VERSION 5.7 ;
  NOWIREEXTENSIONATPIN ON ;
  DIVIDERCHAR "/" ;
  BUSBITCHARS "[]" ;
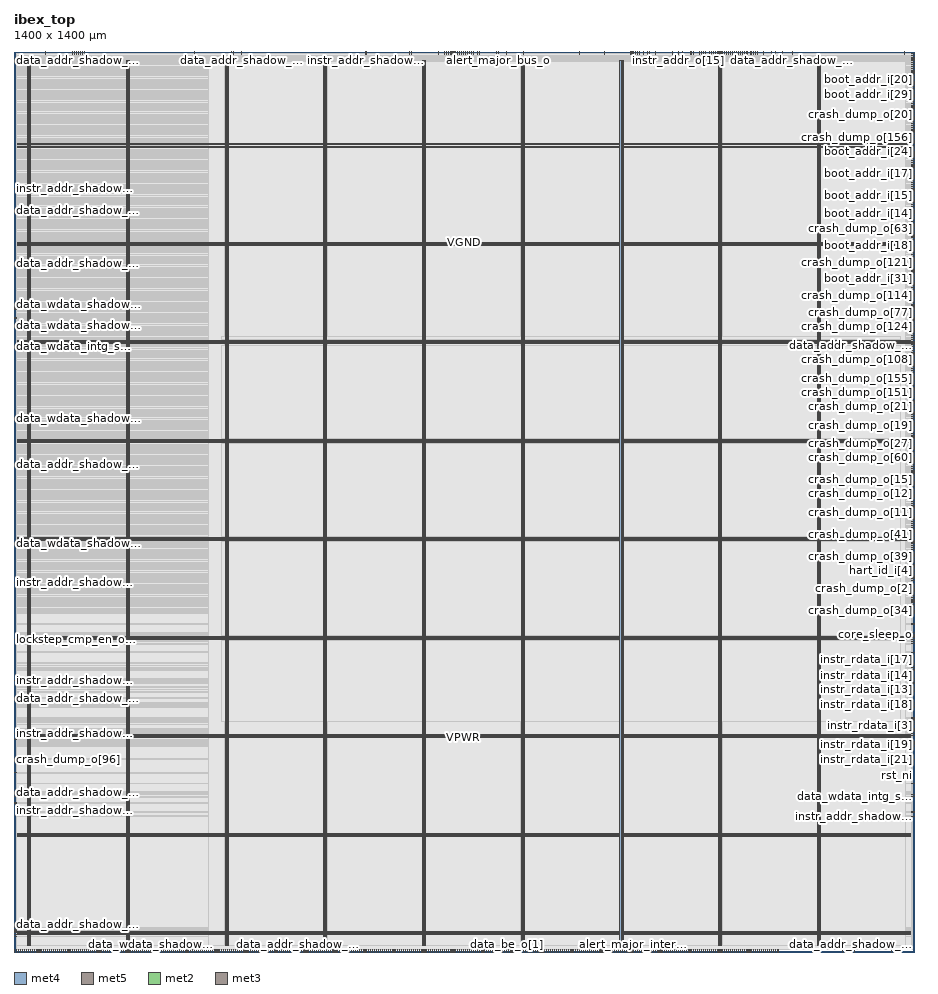
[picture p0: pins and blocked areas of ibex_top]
MACRO ibex_top
  CLASS BLOCK ;
  FOREIGN ibex_top ;
  ORIGIN 0.000 0.000 ;
  SIZE 1400.000 BY 1400.000 ;
  PIN VGND
    DIRECTION INOUT ;
    USE GROUND ;
    PORT
      LAYER met4 ;
        RECT 24.340 10.640 25.940 1387.440 ;
    END
    PORT
      LAYER met4 ;
        RECT 177.940 10.640 179.540 1387.440 ;
    END
    PORT
      LAYER met4 ;
        RECT 331.540 10.640 333.140 1387.440 ;
    END
    PORT
      LAYER met4 ;
        RECT 485.140 10.640 486.740 1387.440 ;
    END
    PORT
      LAYER met4 ;
        RECT 638.740 10.640 640.340 1387.440 ;
    END
    PORT
      LAYER met4 ;
        RECT 792.340 10.640 793.940 1387.440 ;
    END
    PORT
      LAYER met4 ;
        RECT 945.940 10.640 947.540 1387.440 ;
    END
    PORT
      LAYER met4 ;
        RECT 1099.540 10.640 1101.140 1387.440 ;
    END
    PORT
      LAYER met4 ;
        RECT 1253.140 10.640 1254.740 1387.440 ;
    END
    PORT
      LAYER met5 ;
        RECT 5.280 30.030 1394.500 31.630 ;
    END
    PORT
      LAYER met5 ;
        RECT 5.280 183.210 1394.500 184.810 ;
    END
    PORT
      LAYER met5 ;
        RECT 5.280 336.390 1394.500 337.990 ;
    END
    PORT
      LAYER met5 ;
        RECT 5.280 489.570 1394.500 491.170 ;
    END
    PORT
      LAYER met5 ;
        RECT 5.280 642.750 1394.500 644.350 ;
    END
    PORT
      LAYER met5 ;
        RECT 5.280 795.930 1394.500 797.530 ;
    END
    PORT
      LAYER met5 ;
        RECT 5.280 949.110 1394.500 950.710 ;
    END
    PORT
      LAYER met5 ;
        RECT 5.280 1102.290 1394.500 1103.890 ;
    END
    PORT
      LAYER met5 ;
        RECT 5.280 1255.470 1394.500 1257.070 ;
    END
  END VGND
  PIN VPWR
    DIRECTION INOUT ;
    USE POWER ;
    PORT
      LAYER met4 ;
        RECT 21.040 10.640 22.640 1387.440 ;
    END
    PORT
      LAYER met4 ;
        RECT 174.640 10.640 176.240 1387.440 ;
    END
    PORT
      LAYER met4 ;
        RECT 328.240 10.640 329.840 1387.440 ;
    END
    PORT
      LAYER met4 ;
        RECT 481.840 10.640 483.440 1387.440 ;
    END
    PORT
      LAYER met4 ;
        RECT 635.440 10.640 637.040 1387.440 ;
    END
    PORT
      LAYER met4 ;
        RECT 789.040 10.640 790.640 1387.440 ;
    END
    PORT
      LAYER met4 ;
        RECT 942.640 10.640 944.240 1387.440 ;
    END
    PORT
      LAYER met4 ;
        RECT 1096.240 10.640 1097.840 1387.440 ;
    END
    PORT
      LAYER met4 ;
        RECT 1249.840 10.640 1251.440 1387.440 ;
    END
    PORT
      LAYER met5 ;
        RECT 5.280 26.730 1394.500 28.330 ;
    END
    PORT
      LAYER met5 ;
        RECT 5.280 179.910 1394.500 181.510 ;
    END
    PORT
      LAYER met5 ;
        RECT 5.280 333.090 1394.500 334.690 ;
    END
    PORT
      LAYER met5 ;
        RECT 5.280 486.270 1394.500 487.870 ;
    END
    PORT
      LAYER met5 ;
        RECT 5.280 639.450 1394.500 641.050 ;
    END
    PORT
      LAYER met5 ;
        RECT 5.280 792.630 1394.500 794.230 ;
    END
    PORT
      LAYER met5 ;
        RECT 5.280 945.810 1394.500 947.410 ;
    END
    PORT
      LAYER met5 ;
        RECT 5.280 1098.990 1394.500 1100.590 ;
    END
    PORT
      LAYER met5 ;
        RECT 5.280 1252.170 1394.500 1253.770 ;
    END
  END VPWR
  PIN alert_major_bus_o
    DIRECTION OUTPUT ;
    USE SIGNAL ;
    PORT
      LAYER met2 ;
        RECT 753.570 1396.000 753.850 1400.000 ;
    END
  END alert_major_bus_o
  PIN alert_major_internal_o
    DIRECTION OUTPUT ;
    USE SIGNAL ;
    PORT
      LAYER met2 ;
        RECT 962.870 0.000 963.150 4.000 ;
    END
  END alert_major_internal_o
  PIN alert_minor_o
    DIRECTION OUTPUT ;
    USE SIGNAL ;
    PORT
      LAYER met3 ;
        RECT 0.000 278.840 4.000 279.440 ;
    END
  END alert_minor_o
  PIN boot_addr_i[0]
    DIRECTION INPUT ;
    USE SIGNAL ;
    PORT
      LAYER met2 ;
        RECT 9.750 0.000 10.030 4.000 ;
    END
  END boot_addr_i[0]
  PIN boot_addr_i[10]
    DIRECTION INPUT ;
    USE SIGNAL ;
    ANTENNAGATEAREA 0.647700 ;
    ANTENNADIFFAREA 0.434700 ;
    PORT
      LAYER met3 ;
        RECT 1396.000 877.240 1400.000 877.840 ;
    END
  END boot_addr_i[10]
  PIN boot_addr_i[11]
    DIRECTION INPUT ;
    USE SIGNAL ;
    ANTENNAGATEAREA 0.593700 ;
    ANTENNADIFFAREA 0.434700 ;
    PORT
      LAYER met3 ;
        RECT 1396.000 697.040 1400.000 697.640 ;
    END
  END boot_addr_i[11]
  PIN boot_addr_i[12]
    DIRECTION INPUT ;
    USE SIGNAL ;
    ANTENNAGATEAREA 0.647700 ;
    ANTENNADIFFAREA 0.434700 ;
    PORT
      LAYER met3 ;
        RECT 1396.000 945.240 1400.000 945.840 ;
    END
  END boot_addr_i[12]
  PIN boot_addr_i[13]
    DIRECTION INPUT ;
    USE SIGNAL ;
    ANTENNAGATEAREA 0.647700 ;
    ANTENNADIFFAREA 0.434700 ;
    PORT
      LAYER met3 ;
        RECT 1396.000 924.840 1400.000 925.440 ;
    END
  END boot_addr_i[13]
  PIN boot_addr_i[14]
    DIRECTION INPUT ;
    USE SIGNAL ;
    ANTENNAGATEAREA 0.647700 ;
    ANTENNADIFFAREA 0.434700 ;
    PORT
      LAYER met3 ;
        RECT 1396.000 1149.240 1400.000 1149.840 ;
    END
  END boot_addr_i[14]
  PIN boot_addr_i[15]
    DIRECTION INPUT ;
    USE SIGNAL ;
    ANTENNAGATEAREA 0.647700 ;
    ANTENNADIFFAREA 0.434700 ;
    PORT
      LAYER met3 ;
        RECT 1396.000 1176.440 1400.000 1177.040 ;
    END
  END boot_addr_i[15]
  PIN boot_addr_i[16]
    DIRECTION INPUT ;
    USE SIGNAL ;
    ANTENNAGATEAREA 0.682200 ;
    ANTENNADIFFAREA 0.434700 ;
    PORT
      LAYER met3 ;
        RECT 1396.000 1309.040 1400.000 1309.640 ;
    END
  END boot_addr_i[16]
  PIN boot_addr_i[17]
    DIRECTION INPUT ;
    USE SIGNAL ;
    ANTENNAGATEAREA 0.647700 ;
    ANTENNADIFFAREA 0.434700 ;
    PORT
      LAYER met3 ;
        RECT 1396.000 1210.440 1400.000 1211.040 ;
    END
  END boot_addr_i[17]
  PIN boot_addr_i[18]
    DIRECTION INPUT ;
    USE SIGNAL ;
    ANTENNAGATEAREA 0.593700 ;
    ANTENNADIFFAREA 0.434700 ;
    PORT
      LAYER met3 ;
        RECT 1396.000 1098.240 1400.000 1098.840 ;
    END
  END boot_addr_i[18]
  PIN boot_addr_i[19]
    DIRECTION INPUT ;
    USE SIGNAL ;
    ANTENNAGATEAREA 0.593700 ;
    ANTENNADIFFAREA 0.434700 ;
    PORT
      LAYER met3 ;
        RECT 1396.000 1016.640 1400.000 1017.240 ;
    END
  END boot_addr_i[19]
  PIN boot_addr_i[1]
    DIRECTION INPUT ;
    USE SIGNAL ;
    PORT
      LAYER met2 ;
        RECT 12.970 0.000 13.250 4.000 ;
    END
  END boot_addr_i[1]
  PIN boot_addr_i[20]
    DIRECTION INPUT ;
    USE SIGNAL ;
    ANTENNAGATEAREA 0.682200 ;
    ANTENNADIFFAREA 0.434700 ;
    PORT
      LAYER met3 ;
        RECT 1396.000 1356.640 1400.000 1357.240 ;
    END
  END boot_addr_i[20]
  PIN boot_addr_i[21]
    DIRECTION INPUT ;
    USE SIGNAL ;
    ANTENNAGATEAREA 0.682200 ;
    ANTENNADIFFAREA 0.434700 ;
    PORT
      LAYER met3 ;
        RECT 1396.000 1281.840 1400.000 1282.440 ;
    END
  END boot_addr_i[21]
  PIN boot_addr_i[22]
    DIRECTION INPUT ;
    USE SIGNAL ;
    ANTENNAGATEAREA 0.593700 ;
    ANTENNADIFFAREA 0.434700 ;
    PORT
      LAYER met3 ;
        RECT 1396.000 1003.040 1400.000 1003.640 ;
    END
  END boot_addr_i[22]
  PIN boot_addr_i[23]
    DIRECTION INPUT ;
    USE SIGNAL ;
    ANTENNAGATEAREA 0.647700 ;
    ANTENNADIFFAREA 0.434700 ;
    PORT
      LAYER met3 ;
        RECT 1396.000 918.040 1400.000 918.640 ;
    END
  END boot_addr_i[23]
  PIN boot_addr_i[24]
    DIRECTION INPUT ;
    USE SIGNAL ;
    ANTENNAGATEAREA 0.647700 ;
    ANTENNADIFFAREA 0.434700 ;
    PORT
      LAYER met3 ;
        RECT 1396.000 1244.440 1400.000 1245.040 ;
    END
  END boot_addr_i[24]
  PIN boot_addr_i[25]
    DIRECTION INPUT ;
    USE SIGNAL ;
    ANTENNAGATEAREA 0.593700 ;
    ANTENNADIFFAREA 0.434700 ;
    PORT
      LAYER met3 ;
        RECT 1396.000 809.240 1400.000 809.840 ;
    END
  END boot_addr_i[25]
  PIN boot_addr_i[26]
    DIRECTION INPUT ;
    USE SIGNAL ;
    ANTENNAGATEAREA 0.647700 ;
    ANTENNADIFFAREA 0.434700 ;
    PORT
      LAYER met3 ;
        RECT 1396.000 999.640 1400.000 1000.240 ;
    END
  END boot_addr_i[26]
  PIN boot_addr_i[27]
    DIRECTION INPUT ;
    USE SIGNAL ;
    ANTENNAGATEAREA 0.593700 ;
    ANTENNADIFFAREA 0.434700 ;
    PORT
      LAYER met3 ;
        RECT 1396.000 860.240 1400.000 860.840 ;
    END
  END boot_addr_i[27]
  PIN boot_addr_i[28]
    DIRECTION INPUT ;
    USE SIGNAL ;
    ANTENNAGATEAREA 0.647700 ;
    ANTENNADIFFAREA 0.434700 ;
    PORT
      LAYER met3 ;
        RECT 1396.000 744.640 1400.000 745.240 ;
    END
  END boot_addr_i[28]
  PIN boot_addr_i[29]
    DIRECTION INPUT ;
    USE SIGNAL ;
    ANTENNAGATEAREA 0.682200 ;
    ANTENNADIFFAREA 0.434700 ;
    PORT
      LAYER met3 ;
        RECT 1396.000 1346.440 1400.000 1347.040 ;
    END
  END boot_addr_i[29]
  PIN boot_addr_i[2]
    DIRECTION INPUT ;
    USE SIGNAL ;
    PORT
      LAYER met2 ;
        RECT 38.730 0.000 39.010 4.000 ;
    END
  END boot_addr_i[2]
  PIN boot_addr_i[30]
    DIRECTION INPUT ;
    USE SIGNAL ;
    ANTENNAGATEAREA 0.593700 ;
    ANTENNADIFFAREA 0.434700 ;
    PORT
      LAYER met3 ;
        RECT 1396.000 965.640 1400.000 966.240 ;
    END
  END boot_addr_i[30]
  PIN boot_addr_i[31]
    DIRECTION INPUT ;
    USE SIGNAL ;
    ANTENNAGATEAREA 0.647700 ;
    ANTENNADIFFAREA 0.434700 ;
    PORT
      LAYER met3 ;
        RECT 1396.000 1047.240 1400.000 1047.840 ;
    END
  END boot_addr_i[31]
  PIN boot_addr_i[3]
    DIRECTION INPUT ;
    USE SIGNAL ;
    PORT
      LAYER met2 ;
        RECT 315.650 0.000 315.930 4.000 ;
    END
  END boot_addr_i[3]
  PIN boot_addr_i[4]
    DIRECTION INPUT ;
    USE SIGNAL ;
    PORT
      LAYER met2 ;
        RECT 35.510 0.000 35.790 4.000 ;
    END
  END boot_addr_i[4]
  PIN boot_addr_i[5]
    DIRECTION INPUT ;
    USE SIGNAL ;
    PORT
      LAYER met2 ;
        RECT 19.410 0.000 19.690 4.000 ;
    END
  END boot_addr_i[5]
  PIN boot_addr_i[6]
    DIRECTION INPUT ;
    USE SIGNAL ;
    PORT
      LAYER met2 ;
        RECT 41.950 0.000 42.230 4.000 ;
    END
  END boot_addr_i[6]
  PIN boot_addr_i[7]
    DIRECTION INPUT ;
    USE SIGNAL ;
    PORT
      LAYER met2 ;
        RECT 25.850 0.000 26.130 4.000 ;
    END
  END boot_addr_i[7]
  PIN boot_addr_i[8]
    DIRECTION INPUT ;
    USE SIGNAL ;
    ANTENNAGATEAREA 0.682200 ;
    ANTENNADIFFAREA 0.434700 ;
    PORT
      LAYER met3 ;
        RECT 1396.000 1020.040 1400.000 1020.640 ;
    END
  END boot_addr_i[8]
  PIN boot_addr_i[9]
    DIRECTION INPUT ;
    USE SIGNAL ;
    ANTENNAGATEAREA 0.647700 ;
    ANTENNADIFFAREA 0.434700 ;
    PORT
      LAYER met3 ;
        RECT 1396.000 914.640 1400.000 915.240 ;
    END
  END boot_addr_i[9]
  PIN clk_i
    DIRECTION INPUT ;
    USE SIGNAL ;
    ANTENNAGATEAREA 1.286700 ;
    ANTENNADIFFAREA 0.434700 ;
    PORT
      LAYER met3 ;
        RECT 1396.000 482.840 1400.000 483.440 ;
    END
  END clk_i
  PIN core_sleep_o
    DIRECTION OUTPUT ;
    USE SIGNAL ;
    ANTENNADIFFAREA 0.445500 ;
    PORT
      LAYER met3 ;
        RECT 1396.000 493.040 1400.000 493.640 ;
    END
  END core_sleep_o
  PIN crash_dump_o[0]
    DIRECTION OUTPUT ;
    USE SIGNAL ;
    ANTENNADIFFAREA 0.445500 ;
    PORT
      LAYER met3 ;
        RECT 1396.000 622.240 1400.000 622.840 ;
    END
  END crash_dump_o[0]
  PIN crash_dump_o[100]
    DIRECTION OUTPUT ;
    USE SIGNAL ;
    ANTENNADIFFAREA 0.445500 ;
    PORT
      LAYER met2 ;
        RECT 969.310 0.000 969.590 4.000 ;
    END
  END crash_dump_o[100]
  PIN crash_dump_o[101]
    DIRECTION OUTPUT ;
    USE SIGNAL ;
    ANTENNADIFFAREA 0.445500 ;
    PORT
      LAYER met2 ;
        RECT 1043.370 0.000 1043.650 4.000 ;
    END
  END crash_dump_o[101]
  PIN crash_dump_o[102]
    DIRECTION OUTPUT ;
    USE SIGNAL ;
    ANTENNADIFFAREA 0.445500 ;
    PORT
      LAYER met2 ;
        RECT 972.530 0.000 972.810 4.000 ;
    END
  END crash_dump_o[102]
  PIN crash_dump_o[103]
    DIRECTION OUTPUT ;
    USE SIGNAL ;
    ANTENNADIFFAREA 0.445500 ;
    PORT
      LAYER met2 ;
        RECT 1024.050 0.000 1024.330 4.000 ;
    END
  END crash_dump_o[103]
  PIN crash_dump_o[104]
    DIRECTION OUTPUT ;
    USE SIGNAL ;
    ANTENNADIFFAREA 0.445500 ;
    PORT
      LAYER met3 ;
        RECT 1396.000 890.840 1400.000 891.440 ;
    END
  END crash_dump_o[104]
  PIN crash_dump_o[105]
    DIRECTION OUTPUT ;
    USE SIGNAL ;
    ANTENNADIFFAREA 0.445500 ;
    PORT
      LAYER met3 ;
        RECT 1396.000 901.040 1400.000 901.640 ;
    END
  END crash_dump_o[105]
  PIN crash_dump_o[106]
    DIRECTION OUTPUT ;
    USE SIGNAL ;
    ANTENNADIFFAREA 0.445500 ;
    PORT
      LAYER met3 ;
        RECT 1396.000 958.840 1400.000 959.440 ;
    END
  END crash_dump_o[106]
  PIN crash_dump_o[107]
    DIRECTION OUTPUT ;
    USE SIGNAL ;
    ANTENNADIFFAREA 0.445500 ;
    PORT
      LAYER met3 ;
        RECT 1396.000 931.640 1400.000 932.240 ;
    END
  END crash_dump_o[107]
  PIN crash_dump_o[108]
    DIRECTION OUTPUT ;
    USE SIGNAL ;
    ANTENNADIFFAREA 0.445500 ;
    PORT
      LAYER met3 ;
        RECT 1396.000 921.440 1400.000 922.040 ;
    END
  END crash_dump_o[108]
  PIN crash_dump_o[109]
    DIRECTION OUTPUT ;
    USE SIGNAL ;
    ANTENNADIFFAREA 0.445500 ;
    PORT
      LAYER met3 ;
        RECT 1396.000 1037.040 1400.000 1037.640 ;
    END
  END crash_dump_o[109]
  PIN crash_dump_o[10]
    DIRECTION OUTPUT ;
    USE SIGNAL ;
    ANTENNADIFFAREA 0.445500 ;
    PORT
      LAYER met3 ;
        RECT 1396.000 629.040 1400.000 629.640 ;
    END
  END crash_dump_o[10]
  PIN crash_dump_o[110]
    DIRECTION OUTPUT ;
    USE SIGNAL ;
    ANTENNADIFFAREA 0.445500 ;
    PORT
      LAYER met3 ;
        RECT 1396.000 1050.640 1400.000 1051.240 ;
    END
  END crash_dump_o[110]
  PIN crash_dump_o[111]
    DIRECTION OUTPUT ;
    USE SIGNAL ;
    ANTENNADIFFAREA 0.445500 ;
    PORT
      LAYER met3 ;
        RECT 1396.000 1101.640 1400.000 1102.240 ;
    END
  END crash_dump_o[111]
  PIN crash_dump_o[112]
    DIRECTION OUTPUT ;
    USE SIGNAL ;
    ANTENNADIFFAREA 0.445500 ;
    PORT
      LAYER met3 ;
        RECT 1396.000 1026.840 1400.000 1027.440 ;
    END
  END crash_dump_o[112]
  PIN crash_dump_o[113]
    DIRECTION OUTPUT ;
    USE SIGNAL ;
    ANTENNADIFFAREA 0.445500 ;
    PORT
      LAYER met3 ;
        RECT 1396.000 969.040 1400.000 969.640 ;
    END
  END crash_dump_o[113]
  PIN crash_dump_o[114]
    DIRECTION OUTPUT ;
    USE SIGNAL ;
    ANTENNADIFFAREA 0.445500 ;
    PORT
      LAYER met3 ;
        RECT 1396.000 1033.640 1400.000 1034.240 ;
    END
  END crash_dump_o[114]
  PIN crash_dump_o[115]
    DIRECTION OUTPUT ;
    USE SIGNAL ;
    ANTENNADIFFAREA 0.445500 ;
    PORT
      LAYER met3 ;
        RECT 1396.000 952.040 1400.000 952.640 ;
    END
  END crash_dump_o[115]
  PIN crash_dump_o[116]
    DIRECTION OUTPUT ;
    USE SIGNAL ;
    ANTENNADIFFAREA 0.445500 ;
    PORT
      LAYER met3 ;
        RECT 1396.000 1071.040 1400.000 1071.640 ;
    END
  END crash_dump_o[116]
  PIN crash_dump_o[117]
    DIRECTION OUTPUT ;
    USE SIGNAL ;
    ANTENNADIFFAREA 0.445500 ;
    PORT
      LAYER met3 ;
        RECT 1396.000 1105.040 1400.000 1105.640 ;
    END
  END crash_dump_o[117]
  PIN crash_dump_o[118]
    DIRECTION OUTPUT ;
    USE SIGNAL ;
    ANTENNADIFFAREA 0.445500 ;
    PORT
      LAYER met3 ;
        RECT 1396.000 992.840 1400.000 993.440 ;
    END
  END crash_dump_o[118]
  PIN crash_dump_o[119]
    DIRECTION OUTPUT ;
    USE SIGNAL ;
    ANTENNADIFFAREA 0.445500 ;
    PORT
      LAYER met3 ;
        RECT 1396.000 1258.040 1400.000 1258.640 ;
    END
  END crash_dump_o[119]
  PIN crash_dump_o[11]
    DIRECTION OUTPUT ;
    USE SIGNAL ;
    ANTENNADIFFAREA 0.445500 ;
    PORT
      LAYER met3 ;
        RECT 1396.000 683.440 1400.000 684.040 ;
    END
  END crash_dump_o[11]
  PIN crash_dump_o[120]
    DIRECTION OUTPUT ;
    USE SIGNAL ;
    ANTENNADIFFAREA 0.445500 ;
    PORT
      LAYER met3 ;
        RECT 1396.000 996.240 1400.000 996.840 ;
    END
  END crash_dump_o[120]
  PIN crash_dump_o[121]
    DIRECTION OUTPUT ;
    USE SIGNAL ;
    ANTENNADIFFAREA 0.445500 ;
    PORT
      LAYER met3 ;
        RECT 1396.000 1084.640 1400.000 1085.240 ;
    END
  END crash_dump_o[121]
  PIN crash_dump_o[122]
    DIRECTION OUTPUT ;
    USE SIGNAL ;
    ANTENNADIFFAREA 0.445500 ;
    PORT
      LAYER met3 ;
        RECT 1396.000 1186.640 1400.000 1187.240 ;
    END
  END crash_dump_o[122]
  PIN crash_dump_o[123]
    DIRECTION OUTPUT ;
    USE SIGNAL ;
    ANTENNADIFFAREA 0.445500 ;
    PORT
      LAYER met3 ;
        RECT 1396.000 1009.840 1400.000 1010.440 ;
    END
  END crash_dump_o[123]
  PIN crash_dump_o[124]
    DIRECTION OUTPUT ;
    USE SIGNAL ;
    ANTENNADIFFAREA 0.445500 ;
    PORT
      LAYER met3 ;
        RECT 1396.000 972.440 1400.000 973.040 ;
    END
  END crash_dump_o[124]
  PIN crash_dump_o[125]
    DIRECTION OUTPUT ;
    USE SIGNAL ;
    ANTENNADIFFAREA 0.445500 ;
    PORT
      LAYER met3 ;
        RECT 1396.000 1227.440 1400.000 1228.040 ;
    END
  END crash_dump_o[125]
  PIN crash_dump_o[126]
    DIRECTION OUTPUT ;
    USE SIGNAL ;
    ANTENNADIFFAREA 0.445500 ;
    PORT
      LAYER met3 ;
        RECT 1396.000 1057.440 1400.000 1058.040 ;
    END
  END crash_dump_o[126]
  PIN crash_dump_o[127]
    DIRECTION OUTPUT ;
    USE SIGNAL ;
    ANTENNADIFFAREA 0.445500 ;
    PORT
      LAYER met3 ;
        RECT 1396.000 1200.240 1400.000 1200.840 ;
    END
  END crash_dump_o[127]
  PIN crash_dump_o[128]
    DIRECTION OUTPUT ;
    USE SIGNAL ;
    PORT
      LAYER met3 ;
        RECT 1396.000 1377.040 1400.000 1377.640 ;
    END
  END crash_dump_o[128]
  PIN crash_dump_o[129]
    DIRECTION OUTPUT ;
    USE SIGNAL ;
    ANTENNADIFFAREA 0.445500 ;
    PORT
      LAYER met3 ;
        RECT 1396.000 533.840 1400.000 534.440 ;
    END
  END crash_dump_o[129]
  PIN crash_dump_o[12]
    DIRECTION OUTPUT ;
    USE SIGNAL ;
    ANTENNADIFFAREA 0.445500 ;
    PORT
      LAYER met3 ;
        RECT 1396.000 700.440 1400.000 701.040 ;
    END
  END crash_dump_o[12]
  PIN crash_dump_o[130]
    DIRECTION OUTPUT ;
    USE SIGNAL ;
    ANTENNADIFFAREA 0.445500 ;
    PORT
      LAYER met2 ;
        RECT 898.470 0.000 898.750 4.000 ;
    END
  END crash_dump_o[130]
  PIN crash_dump_o[131]
    DIRECTION OUTPUT ;
    USE SIGNAL ;
    ANTENNADIFFAREA 0.445500 ;
    PORT
      LAYER met2 ;
        RECT 901.690 0.000 901.970 4.000 ;
    END
  END crash_dump_o[131]
  PIN crash_dump_o[132]
    DIRECTION OUTPUT ;
    USE SIGNAL ;
    ANTENNADIFFAREA 0.445500 ;
    PORT
      LAYER met2 ;
        RECT 946.770 0.000 947.050 4.000 ;
    END
  END crash_dump_o[132]
  PIN crash_dump_o[133]
    DIRECTION OUTPUT ;
    USE SIGNAL ;
    ANTENNADIFFAREA 0.445500 ;
    PORT
      LAYER met3 ;
        RECT 1396.000 544.040 1400.000 544.640 ;
    END
  END crash_dump_o[133]
  PIN crash_dump_o[134]
    DIRECTION OUTPUT ;
    USE SIGNAL ;
    ANTENNADIFFAREA 0.445500 ;
    PORT
      LAYER met2 ;
        RECT 953.210 0.000 953.490 4.000 ;
    END
  END crash_dump_o[134]
  PIN crash_dump_o[135]
    DIRECTION OUTPUT ;
    USE SIGNAL ;
    ANTENNADIFFAREA 0.445500 ;
    PORT
      LAYER met2 ;
        RECT 1030.490 0.000 1030.770 4.000 ;
    END
  END crash_dump_o[135]
  PIN crash_dump_o[136]
    DIRECTION OUTPUT ;
    USE SIGNAL ;
    ANTENNADIFFAREA 0.445500 ;
    PORT
      LAYER met2 ;
        RECT 956.430 0.000 956.710 4.000 ;
    END
  END crash_dump_o[136]
  PIN crash_dump_o[137]
    DIRECTION OUTPUT ;
    USE SIGNAL ;
    ANTENNADIFFAREA 0.445500 ;
    PORT
      LAYER met2 ;
        RECT 940.330 0.000 940.610 4.000 ;
    END
  END crash_dump_o[137]
  PIN crash_dump_o[138]
    DIRECTION OUTPUT ;
    USE SIGNAL ;
    ANTENNADIFFAREA 0.445500 ;
    PORT
      LAYER met2 ;
        RECT 1033.710 0.000 1033.990 4.000 ;
    END
  END crash_dump_o[138]
  PIN crash_dump_o[139]
    DIRECTION OUTPUT ;
    USE SIGNAL ;
    ANTENNADIFFAREA 0.445500 ;
    PORT
      LAYER met2 ;
        RECT 1027.270 0.000 1027.550 4.000 ;
    END
  END crash_dump_o[139]
  PIN crash_dump_o[13]
    DIRECTION OUTPUT ;
    USE SIGNAL ;
    ANTENNADIFFAREA 0.445500 ;
    PORT
      LAYER met3 ;
        RECT 1396.000 717.440 1400.000 718.040 ;
    END
  END crash_dump_o[13]
  PIN crash_dump_o[140]
    DIRECTION OUTPUT ;
    USE SIGNAL ;
    ANTENNADIFFAREA 0.445500 ;
    PORT
      LAYER met2 ;
        RECT 949.990 0.000 950.270 4.000 ;
    END
  END crash_dump_o[140]
  PIN crash_dump_o[141]
    DIRECTION OUTPUT ;
    USE SIGNAL ;
    ANTENNADIFFAREA 0.445500 ;
    PORT
      LAYER met3 ;
        RECT 1396.000 737.840 1400.000 738.440 ;
    END
  END crash_dump_o[141]
  PIN crash_dump_o[142]
    DIRECTION OUTPUT ;
    USE SIGNAL ;
    ANTENNADIFFAREA 0.445500 ;
    PORT
      LAYER met3 ;
        RECT 1396.000 880.640 1400.000 881.240 ;
    END
  END crash_dump_o[142]
  PIN crash_dump_o[143]
    DIRECTION OUTPUT ;
    USE SIGNAL ;
    ANTENNADIFFAREA 0.445500 ;
    PORT
      LAYER met3 ;
        RECT 1396.000 873.840 1400.000 874.440 ;
    END
  END crash_dump_o[143]
  PIN crash_dump_o[144]
    DIRECTION OUTPUT ;
    USE SIGNAL ;
    ANTENNADIFFAREA 0.445500 ;
    PORT
      LAYER met3 ;
        RECT 1396.000 839.840 1400.000 840.440 ;
    END
  END crash_dump_o[144]
  PIN crash_dump_o[145]
    DIRECTION OUTPUT ;
    USE SIGNAL ;
    ANTENNADIFFAREA 0.445500 ;
    PORT
      LAYER met3 ;
        RECT 1396.000 911.240 1400.000 911.840 ;
    END
  END crash_dump_o[145]
  PIN crash_dump_o[146]
    DIRECTION OUTPUT ;
    USE SIGNAL ;
    ANTENNADIFFAREA 0.445500 ;
    PORT
      LAYER met3 ;
        RECT 1396.000 1122.040 1400.000 1122.640 ;
    END
  END crash_dump_o[146]
  PIN crash_dump_o[147]
    DIRECTION OUTPUT ;
    USE SIGNAL ;
    ANTENNADIFFAREA 0.445500 ;
    PORT
      LAYER met3 ;
        RECT 1396.000 979.240 1400.000 979.840 ;
    END
  END crash_dump_o[147]
  PIN crash_dump_o[148]
    DIRECTION OUTPUT ;
    USE SIGNAL ;
    ANTENNADIFFAREA 0.445500 ;
    PORT
      LAYER met3 ;
        RECT 1396.000 833.040 1400.000 833.640 ;
    END
  END crash_dump_o[148]
  PIN crash_dump_o[149]
    DIRECTION OUTPUT ;
    USE SIGNAL ;
    ANTENNADIFFAREA 0.445500 ;
    PORT
      LAYER met3 ;
        RECT 1396.000 948.640 1400.000 949.240 ;
    END
  END crash_dump_o[149]
  PIN crash_dump_o[14]
    DIRECTION OUTPUT ;
    USE SIGNAL ;
    ANTENNADIFFAREA 0.445500 ;
    PORT
      LAYER met3 ;
        RECT 1396.000 720.840 1400.000 721.440 ;
    END
  END crash_dump_o[14]
  PIN crash_dump_o[150]
    DIRECTION OUTPUT ;
    USE SIGNAL ;
    ANTENNADIFFAREA 0.445500 ;
    PORT
      LAYER met3 ;
        RECT 1396.000 1067.640 1400.000 1068.240 ;
    END
  END crash_dump_o[150]
  PIN crash_dump_o[151]
    DIRECTION OUTPUT ;
    USE SIGNAL ;
    ANTENNADIFFAREA 0.445500 ;
    PORT
      LAYER met3 ;
        RECT 1396.000 870.440 1400.000 871.040 ;
    END
  END crash_dump_o[151]
  PIN crash_dump_o[152]
    DIRECTION OUTPUT ;
    USE SIGNAL ;
    ANTENNADIFFAREA 0.445500 ;
    PORT
      LAYER met3 ;
        RECT 1396.000 907.840 1400.000 908.440 ;
    END
  END crash_dump_o[152]
  PIN crash_dump_o[153]
    DIRECTION OUTPUT ;
    USE SIGNAL ;
    ANTENNADIFFAREA 0.445500 ;
    PORT
      LAYER met3 ;
        RECT 1396.000 867.040 1400.000 867.640 ;
    END
  END crash_dump_o[153]
  PIN crash_dump_o[154]
    DIRECTION OUTPUT ;
    USE SIGNAL ;
    ANTENNADIFFAREA 0.445500 ;
    PORT
      LAYER met3 ;
        RECT 1396.000 1343.040 1400.000 1343.640 ;
    END
  END crash_dump_o[154]
  PIN crash_dump_o[155]
    DIRECTION OUTPUT ;
    USE SIGNAL ;
    ANTENNADIFFAREA 0.445500 ;
    PORT
      LAYER met3 ;
        RECT 1396.000 904.440 1400.000 905.040 ;
    END
  END crash_dump_o[155]
  PIN crash_dump_o[156]
    DIRECTION OUTPUT ;
    USE SIGNAL ;
    ANTENNADIFFAREA 0.445500 ;
    PORT
      LAYER met3 ;
        RECT 1396.000 1254.640 1400.000 1255.240 ;
    END
  END crash_dump_o[156]
  PIN crash_dump_o[157]
    DIRECTION OUTPUT ;
    USE SIGNAL ;
    ANTENNADIFFAREA 0.445500 ;
    PORT
      LAYER met3 ;
        RECT 1396.000 1077.840 1400.000 1078.440 ;
    END
  END crash_dump_o[157]
  PIN crash_dump_o[158]
    DIRECTION OUTPUT ;
    USE SIGNAL ;
    ANTENNADIFFAREA 0.445500 ;
    PORT
      LAYER met3 ;
        RECT 1396.000 1173.040 1400.000 1173.640 ;
    END
  END crash_dump_o[158]
  PIN crash_dump_o[159]
    DIRECTION OUTPUT ;
    USE SIGNAL ;
    ANTENNADIFFAREA 0.445500 ;
    PORT
      LAYER met3 ;
        RECT 1396.000 1196.840 1400.000 1197.440 ;
    END
  END crash_dump_o[159]
  PIN crash_dump_o[15]
    DIRECTION OUTPUT ;
    USE SIGNAL ;
    ANTENNADIFFAREA 0.445500 ;
    PORT
      LAYER met3 ;
        RECT 1396.000 734.440 1400.000 735.040 ;
    END
  END crash_dump_o[15]
  PIN crash_dump_o[16]
    DIRECTION OUTPUT ;
    USE SIGNAL ;
    ANTENNADIFFAREA 0.445500 ;
    PORT
      LAYER met3 ;
        RECT 1396.000 758.240 1400.000 758.840 ;
    END
  END crash_dump_o[16]
  PIN crash_dump_o[17]
    DIRECTION OUTPUT ;
    USE SIGNAL ;
    ANTENNADIFFAREA 0.445500 ;
    PORT
      LAYER met3 ;
        RECT 1396.000 778.640 1400.000 779.240 ;
    END
  END crash_dump_o[17]
  PIN crash_dump_o[18]
    DIRECTION OUTPUT ;
    USE SIGNAL ;
    ANTENNADIFFAREA 0.445500 ;
    PORT
      LAYER met3 ;
        RECT 1396.000 812.640 1400.000 813.240 ;
    END
  END crash_dump_o[18]
  PIN crash_dump_o[19]
    DIRECTION OUTPUT ;
    USE SIGNAL ;
    ANTENNADIFFAREA 0.445500 ;
    PORT
      LAYER met3 ;
        RECT 1396.000 819.440 1400.000 820.040 ;
    END
  END crash_dump_o[19]
  PIN crash_dump_o[1]
    DIRECTION OUTPUT ;
    USE SIGNAL ;
    ANTENNADIFFAREA 0.445500 ;
    PORT
      LAYER met3 ;
        RECT 1396.000 550.840 1400.000 551.440 ;
    END
  END crash_dump_o[1]
  PIN crash_dump_o[20]
    DIRECTION OUTPUT ;
    USE SIGNAL ;
    ANTENNADIFFAREA 0.445500 ;
    PORT
      LAYER met3 ;
        RECT 1396.000 1302.240 1400.000 1302.840 ;
    END
  END crash_dump_o[20]
  PIN crash_dump_o[21]
    DIRECTION OUTPUT ;
    USE SIGNAL ;
    ANTENNADIFFAREA 0.445500 ;
    PORT
      LAYER met3 ;
        RECT 1396.000 836.440 1400.000 837.040 ;
    END
  END crash_dump_o[21]
  PIN crash_dump_o[22]
    DIRECTION OUTPUT ;
    USE SIGNAL ;
    ANTENNADIFFAREA 0.445500 ;
    PORT
      LAYER met3 ;
        RECT 1396.000 1213.840 1400.000 1214.440 ;
    END
  END crash_dump_o[22]
  PIN crash_dump_o[23]
    DIRECTION OUTPUT ;
    USE SIGNAL ;
    ANTENNADIFFAREA 0.445500 ;
    PORT
      LAYER met3 ;
        RECT 1396.000 863.640 1400.000 864.240 ;
    END
  END crash_dump_o[23]
  PIN crash_dump_o[24]
    DIRECTION OUTPUT ;
    USE SIGNAL ;
    ANTENNADIFFAREA 0.445500 ;
    PORT
      LAYER met3 ;
        RECT 1396.000 795.640 1400.000 796.240 ;
    END
  END crash_dump_o[24]
  PIN crash_dump_o[25]
    DIRECTION OUTPUT ;
    USE SIGNAL ;
    ANTENNADIFFAREA 0.445500 ;
    PORT
      LAYER met3 ;
        RECT 1396.000 853.440 1400.000 854.040 ;
    END
  END crash_dump_o[25]
  PIN crash_dump_o[26]
    DIRECTION OUTPUT ;
    USE SIGNAL ;
    ANTENNADIFFAREA 0.445500 ;
    PORT
      LAYER met3 ;
        RECT 1396.000 1251.240 1400.000 1251.840 ;
    END
  END crash_dump_o[26]
  PIN crash_dump_o[27]
    DIRECTION OUTPUT ;
    USE SIGNAL ;
    ANTENNADIFFAREA 0.445500 ;
    PORT
      LAYER met3 ;
        RECT 1396.000 802.440 1400.000 803.040 ;
    END
  END crash_dump_o[27]
  PIN crash_dump_o[28]
    DIRECTION OUTPUT ;
    USE SIGNAL ;
    ANTENNADIFFAREA 0.445500 ;
    PORT
      LAYER met3 ;
        RECT 1396.000 727.640 1400.000 728.240 ;
    END
  END crash_dump_o[28]
  PIN crash_dump_o[29]
    DIRECTION OUTPUT ;
    USE SIGNAL ;
    ANTENNADIFFAREA 0.445500 ;
    PORT
      LAYER met3 ;
        RECT 1396.000 754.840 1400.000 755.440 ;
    END
  END crash_dump_o[29]
  PIN crash_dump_o[2]
    DIRECTION OUTPUT ;
    USE SIGNAL ;
    ANTENNADIFFAREA 0.445500 ;
    PORT
      LAYER met3 ;
        RECT 1396.000 564.440 1400.000 565.040 ;
    END
  END crash_dump_o[2]
  PIN crash_dump_o[30]
    DIRECTION OUTPUT ;
    USE SIGNAL ;
    ANTENNADIFFAREA 0.445500 ;
    PORT
      LAYER met3 ;
        RECT 1396.000 856.840 1400.000 857.440 ;
    END
  END crash_dump_o[30]
  PIN crash_dump_o[31]
    DIRECTION OUTPUT ;
    USE SIGNAL ;
    ANTENNADIFFAREA 0.445500 ;
    PORT
      LAYER met3 ;
        RECT 1396.000 846.640 1400.000 847.240 ;
    END
  END crash_dump_o[31]
  PIN crash_dump_o[32]
    DIRECTION OUTPUT ;
    USE SIGNAL ;
    ANTENNADIFFAREA 0.445500 ;
    PORT
      LAYER met3 ;
        RECT 1396.000 537.240 1400.000 537.840 ;
    END
  END crash_dump_o[32]
  PIN crash_dump_o[33]
    DIRECTION OUTPUT ;
    USE SIGNAL ;
    ANTENNADIFFAREA 0.445500 ;
    PORT
      LAYER met3 ;
        RECT 1396.000 527.040 1400.000 527.640 ;
    END
  END crash_dump_o[33]
  PIN crash_dump_o[34]
    DIRECTION OUTPUT ;
    USE SIGNAL ;
    ANTENNADIFFAREA 0.445500 ;
    PORT
      LAYER met3 ;
        RECT 1396.000 530.440 1400.000 531.040 ;
    END
  END crash_dump_o[34]
  PIN crash_dump_o[35]
    DIRECTION OUTPUT ;
    USE SIGNAL ;
    ANTENNADIFFAREA 0.445500 ;
    PORT
      LAYER met3 ;
        RECT 1396.000 540.640 1400.000 541.240 ;
    END
  END crash_dump_o[35]
  PIN crash_dump_o[36]
    DIRECTION OUTPUT ;
    USE SIGNAL ;
    ANTENNADIFFAREA 0.445500 ;
    PORT
      LAYER met3 ;
        RECT 1396.000 510.040 1400.000 510.640 ;
    END
  END crash_dump_o[36]
  PIN crash_dump_o[37]
    DIRECTION OUTPUT ;
    USE SIGNAL ;
    ANTENNADIFFAREA 0.445500 ;
    PORT
      LAYER met3 ;
        RECT 1396.000 547.440 1400.000 548.040 ;
    END
  END crash_dump_o[37]
  PIN crash_dump_o[38]
    DIRECTION OUTPUT ;
    USE SIGNAL ;
    ANTENNADIFFAREA 0.445500 ;
    PORT
      LAYER met3 ;
        RECT 1396.000 561.040 1400.000 561.640 ;
    END
  END crash_dump_o[38]
  PIN crash_dump_o[39]
    DIRECTION OUTPUT ;
    USE SIGNAL ;
    ANTENNADIFFAREA 0.445500 ;
    PORT
      LAYER met3 ;
        RECT 1396.000 615.440 1400.000 616.040 ;
    END
  END crash_dump_o[39]
  PIN crash_dump_o[3]
    DIRECTION OUTPUT ;
    USE SIGNAL ;
    ANTENNADIFFAREA 0.445500 ;
    PORT
      LAYER met3 ;
        RECT 1396.000 567.840 1400.000 568.440 ;
    END
  END crash_dump_o[3]
  PIN crash_dump_o[40]
    DIRECTION OUTPUT ;
    USE SIGNAL ;
    ANTENNADIFFAREA 0.445500 ;
    PORT
      LAYER met3 ;
        RECT 1396.000 639.240 1400.000 639.840 ;
    END
  END crash_dump_o[40]
  PIN crash_dump_o[41]
    DIRECTION OUTPUT ;
    USE SIGNAL ;
    ANTENNADIFFAREA 0.445500 ;
    PORT
      LAYER met3 ;
        RECT 1396.000 649.440 1400.000 650.040 ;
    END
  END crash_dump_o[41]
  PIN crash_dump_o[42]
    DIRECTION OUTPUT ;
    USE SIGNAL ;
    ANTENNADIFFAREA 0.445500 ;
    PORT
      LAYER met3 ;
        RECT 1396.000 663.040 1400.000 663.640 ;
    END
  END crash_dump_o[42]
  PIN crash_dump_o[43]
    DIRECTION OUTPUT ;
    USE SIGNAL ;
    ANTENNADIFFAREA 0.445500 ;
    PORT
      LAYER met3 ;
        RECT 1396.000 690.240 1400.000 690.840 ;
    END
  END crash_dump_o[43]
  PIN crash_dump_o[44]
    DIRECTION OUTPUT ;
    USE SIGNAL ;
    ANTENNADIFFAREA 0.445500 ;
    PORT
      LAYER met3 ;
        RECT 1396.000 714.040 1400.000 714.640 ;
    END
  END crash_dump_o[44]
  PIN crash_dump_o[45]
    DIRECTION OUTPUT ;
    USE SIGNAL ;
    ANTENNADIFFAREA 0.445500 ;
    PORT
      LAYER met3 ;
        RECT 1396.000 775.240 1400.000 775.840 ;
    END
  END crash_dump_o[45]
  PIN crash_dump_o[46]
    DIRECTION OUTPUT ;
    USE SIGNAL ;
    ANTENNADIFFAREA 0.445500 ;
    PORT
      LAYER met3 ;
        RECT 1396.000 1030.240 1400.000 1030.840 ;
    END
  END crash_dump_o[46]
  PIN crash_dump_o[47]
    DIRECTION OUTPUT ;
    USE SIGNAL ;
    ANTENNADIFFAREA 0.445500 ;
    PORT
      LAYER met3 ;
        RECT 1396.000 935.040 1400.000 935.640 ;
    END
  END crash_dump_o[47]
  PIN crash_dump_o[48]
    DIRECTION OUTPUT ;
    USE SIGNAL ;
    ANTENNADIFFAREA 0.445500 ;
    PORT
      LAYER met3 ;
        RECT 1396.000 771.840 1400.000 772.440 ;
    END
  END crash_dump_o[48]
  PIN crash_dump_o[49]
    DIRECTION OUTPUT ;
    USE SIGNAL ;
    ANTENNADIFFAREA 0.445500 ;
    PORT
      LAYER met3 ;
        RECT 1396.000 1264.840 1400.000 1265.440 ;
    END
  END crash_dump_o[49]
  PIN crash_dump_o[4]
    DIRECTION OUTPUT ;
    USE SIGNAL ;
    ANTENNADIFFAREA 0.445500 ;
    PORT
      LAYER met3 ;
        RECT 1396.000 554.240 1400.000 554.840 ;
    END
  END crash_dump_o[4]
  PIN crash_dump_o[50]
    DIRECTION OUTPUT ;
    USE SIGNAL ;
    ANTENNADIFFAREA 0.445500 ;
    PORT
      LAYER met3 ;
        RECT 1396.000 1220.640 1400.000 1221.240 ;
    END
  END crash_dump_o[50]
  PIN crash_dump_o[51]
    DIRECTION OUTPUT ;
    USE SIGNAL ;
    ANTENNADIFFAREA 0.445500 ;
    PORT
      LAYER met3 ;
        RECT 1396.000 1183.240 1400.000 1183.840 ;
    END
  END crash_dump_o[51]
  PIN crash_dump_o[52]
    DIRECTION OUTPUT ;
    USE SIGNAL ;
    ANTENNADIFFAREA 0.445500 ;
    PORT
      LAYER met3 ;
        RECT 1396.000 826.240 1400.000 826.840 ;
    END
  END crash_dump_o[52]
  PIN crash_dump_o[53]
    DIRECTION OUTPUT ;
    USE SIGNAL ;
    ANTENNADIFFAREA 0.445500 ;
    PORT
      LAYER met3 ;
        RECT 1396.000 1241.040 1400.000 1241.640 ;
    END
  END crash_dump_o[53]
  PIN crash_dump_o[54]
    DIRECTION OUTPUT ;
    USE SIGNAL ;
    ANTENNADIFFAREA 0.445500 ;
    PORT
      LAYER met3 ;
        RECT 1396.000 986.040 1400.000 986.640 ;
    END
  END crash_dump_o[54]
  PIN crash_dump_o[55]
    DIRECTION OUTPUT ;
    USE SIGNAL ;
    ANTENNADIFFAREA 0.445500 ;
    PORT
      LAYER met3 ;
        RECT 1396.000 1118.640 1400.000 1119.240 ;
    END
  END crash_dump_o[55]
  PIN crash_dump_o[56]
    DIRECTION OUTPUT ;
    USE SIGNAL ;
    ANTENNADIFFAREA 0.445500 ;
    PORT
      LAYER met3 ;
        RECT 1396.000 941.840 1400.000 942.440 ;
    END
  END crash_dump_o[56]
  PIN crash_dump_o[57]
    DIRECTION OUTPUT ;
    USE SIGNAL ;
    ANTENNADIFFAREA 0.445500 ;
    PORT
      LAYER met3 ;
        RECT 1396.000 1319.240 1400.000 1319.840 ;
    END
  END crash_dump_o[57]
  PIN crash_dump_o[58]
    DIRECTION OUTPUT ;
    USE SIGNAL ;
    ANTENNADIFFAREA 0.445500 ;
    PORT
      LAYER met3 ;
        RECT 1396.000 1329.440 1400.000 1330.040 ;
    END
  END crash_dump_o[58]
  PIN crash_dump_o[59]
    DIRECTION OUTPUT ;
    USE SIGNAL ;
    ANTENNADIFFAREA 0.445500 ;
    PORT
      LAYER met3 ;
        RECT 1396.000 1091.440 1400.000 1092.040 ;
    END
  END crash_dump_o[59]
  PIN crash_dump_o[5]
    DIRECTION OUTPUT ;
    USE SIGNAL ;
    ANTENNADIFFAREA 0.445500 ;
    PORT
      LAYER met2 ;
        RECT 959.650 0.000 959.930 4.000 ;
    END
  END crash_dump_o[5]
  PIN crash_dump_o[60]
    DIRECTION OUTPUT ;
    USE SIGNAL ;
    ANTENNADIFFAREA 0.445500 ;
    PORT
      LAYER met3 ;
        RECT 1396.000 768.440 1400.000 769.040 ;
    END
  END crash_dump_o[60]
  PIN crash_dump_o[61]
    DIRECTION OUTPUT ;
    USE SIGNAL ;
    ANTENNADIFFAREA 0.445500 ;
    PORT
      LAYER met3 ;
        RECT 1396.000 975.840 1400.000 976.440 ;
    END
  END crash_dump_o[61]
  PIN crash_dump_o[62]
    DIRECTION OUTPUT ;
    USE SIGNAL ;
    ANTENNADIFFAREA 0.445500 ;
    PORT
      LAYER met3 ;
        RECT 1396.000 1275.040 1400.000 1275.640 ;
    END
  END crash_dump_o[62]
  PIN crash_dump_o[63]
    DIRECTION OUTPUT ;
    USE SIGNAL ;
    ANTENNADIFFAREA 0.445500 ;
    PORT
      LAYER met3 ;
        RECT 1396.000 1125.440 1400.000 1126.040 ;
    END
  END crash_dump_o[63]
  PIN crash_dump_o[64]
    DIRECTION OUTPUT ;
    USE SIGNAL ;
    ANTENNADIFFAREA 0.445500 ;
    PORT
      LAYER met2 ;
        RECT 908.130 0.000 908.410 4.000 ;
    END
  END crash_dump_o[64]
  PIN crash_dump_o[65]
    DIRECTION OUTPUT ;
    USE SIGNAL ;
    ANTENNADIFFAREA 0.445500 ;
    PORT
      LAYER met2 ;
        RECT 911.350 0.000 911.630 4.000 ;
    END
  END crash_dump_o[65]
  PIN crash_dump_o[66]
    DIRECTION OUTPUT ;
    USE SIGNAL ;
    ANTENNADIFFAREA 0.445500 ;
    PORT
      LAYER met2 ;
        RECT 917.790 0.000 918.070 4.000 ;
    END
  END crash_dump_o[66]
  PIN crash_dump_o[67]
    DIRECTION OUTPUT ;
    USE SIGNAL ;
    ANTENNADIFFAREA 0.445500 ;
    PORT
      LAYER met2 ;
        RECT 904.910 0.000 905.190 4.000 ;
    END
  END crash_dump_o[67]
  PIN crash_dump_o[68]
    DIRECTION OUTPUT ;
    USE SIGNAL ;
    ANTENNADIFFAREA 0.445500 ;
    PORT
      LAYER met2 ;
        RECT 914.570 0.000 914.850 4.000 ;
    END
  END crash_dump_o[68]
  PIN crash_dump_o[69]
    DIRECTION OUTPUT ;
    USE SIGNAL ;
    ANTENNADIFFAREA 0.445500 ;
    PORT
      LAYER met2 ;
        RECT 930.670 0.000 930.950 4.000 ;
    END
  END crash_dump_o[69]
  PIN crash_dump_o[6]
    DIRECTION OUTPUT ;
    USE SIGNAL ;
    ANTENNADIFFAREA 0.445500 ;
    PORT
      LAYER met3 ;
        RECT 1396.000 595.040 1400.000 595.640 ;
    END
  END crash_dump_o[6]
  PIN crash_dump_o[70]
    DIRECTION OUTPUT ;
    USE SIGNAL ;
    ANTENNADIFFAREA 0.445500 ;
    PORT
      LAYER met2 ;
        RECT 933.890 0.000 934.170 4.000 ;
    END
  END crash_dump_o[70]
  PIN crash_dump_o[71]
    DIRECTION OUTPUT ;
    USE SIGNAL ;
    ANTENNADIFFAREA 0.445500 ;
    PORT
      LAYER met2 ;
        RECT 924.230 0.000 924.510 4.000 ;
    END
  END crash_dump_o[71]
  PIN crash_dump_o[72]
    DIRECTION OUTPUT ;
    USE SIGNAL ;
    ANTENNADIFFAREA 0.445500 ;
    PORT
      LAYER met2 ;
        RECT 927.450 0.000 927.730 4.000 ;
    END
  END crash_dump_o[72]
  PIN crash_dump_o[73]
    DIRECTION OUTPUT ;
    USE SIGNAL ;
    ANTENNADIFFAREA 0.445500 ;
    PORT
      LAYER met2 ;
        RECT 921.010 0.000 921.290 4.000 ;
    END
  END crash_dump_o[73]
  PIN crash_dump_o[74]
    DIRECTION OUTPUT ;
    USE SIGNAL ;
    ANTENNADIFFAREA 0.445500 ;
    PORT
      LAYER met2 ;
        RECT 943.550 0.000 943.830 4.000 ;
    END
  END crash_dump_o[74]
  PIN crash_dump_o[75]
    DIRECTION OUTPUT ;
    USE SIGNAL ;
    ANTENNADIFFAREA 0.445500 ;
    PORT
      LAYER met2 ;
        RECT 937.110 0.000 937.390 4.000 ;
    END
  END crash_dump_o[75]
  PIN crash_dump_o[76]
    DIRECTION OUTPUT ;
    USE SIGNAL ;
    ANTENNADIFFAREA 0.445500 ;
    PORT
      LAYER met3 ;
        RECT 1396.000 884.040 1400.000 884.640 ;
    END
  END crash_dump_o[76]
  PIN crash_dump_o[77]
    DIRECTION OUTPUT ;
    USE SIGNAL ;
    ANTENNADIFFAREA 0.445500 ;
    PORT
      LAYER met3 ;
        RECT 1396.000 1006.440 1400.000 1007.040 ;
    END
  END crash_dump_o[77]
  PIN crash_dump_o[78]
    DIRECTION OUTPUT ;
    USE SIGNAL ;
    ANTENNADIFFAREA 0.445500 ;
    PORT
      LAYER met3 ;
        RECT 1396.000 887.440 1400.000 888.040 ;
    END
  END crash_dump_o[78]
  PIN crash_dump_o[79]
    DIRECTION OUTPUT ;
    USE SIGNAL ;
    ANTENNADIFFAREA 0.445500 ;
    PORT
      LAYER met3 ;
        RECT 1396.000 761.640 1400.000 762.240 ;
    END
  END crash_dump_o[79]
  PIN crash_dump_o[7]
    DIRECTION OUTPUT ;
    USE SIGNAL ;
    ANTENNADIFFAREA 0.445500 ;
    PORT
      LAYER met2 ;
        RECT 1049.810 0.000 1050.090 4.000 ;
    END
  END crash_dump_o[7]
  PIN crash_dump_o[80]
    DIRECTION OUTPUT ;
    USE SIGNAL ;
    ANTENNADIFFAREA 0.445500 ;
    PORT
      LAYER met3 ;
        RECT 1396.000 785.440 1400.000 786.040 ;
    END
  END crash_dump_o[80]
  PIN crash_dump_o[81]
    DIRECTION OUTPUT ;
    USE SIGNAL ;
    ANTENNADIFFAREA 0.445500 ;
    PORT
      LAYER met3 ;
        RECT 1396.000 1179.840 1400.000 1180.440 ;
    END
  END crash_dump_o[81]
  PIN crash_dump_o[82]
    DIRECTION OUTPUT ;
    USE SIGNAL ;
    ANTENNADIFFAREA 0.445500 ;
    PORT
      LAYER met3 ;
        RECT 1396.000 799.040 1400.000 799.640 ;
    END
  END crash_dump_o[82]
  PIN crash_dump_o[83]
    DIRECTION OUTPUT ;
    USE SIGNAL ;
    ANTENNADIFFAREA 0.445500 ;
    PORT
      LAYER met3 ;
        RECT 1396.000 1040.440 1400.000 1041.040 ;
    END
  END crash_dump_o[83]
  PIN crash_dump_o[84]
    DIRECTION OUTPUT ;
    USE SIGNAL ;
    ANTENNADIFFAREA 0.445500 ;
    PORT
      LAYER met3 ;
        RECT 1396.000 1285.240 1400.000 1285.840 ;
    END
  END crash_dump_o[84]
  PIN crash_dump_o[85]
    DIRECTION OUTPUT ;
    USE SIGNAL ;
    ANTENNADIFFAREA 0.445500 ;
    PORT
      LAYER met3 ;
        RECT 1396.000 1353.240 1400.000 1353.840 ;
    END
  END crash_dump_o[85]
  PIN crash_dump_o[86]
    DIRECTION OUTPUT ;
    USE SIGNAL ;
    ANTENNADIFFAREA 0.445500 ;
    PORT
      LAYER met3 ;
        RECT 1396.000 1193.440 1400.000 1194.040 ;
    END
  END crash_dump_o[86]
  PIN crash_dump_o[87]
    DIRECTION OUTPUT ;
    USE SIGNAL ;
    ANTENNADIFFAREA 0.445500 ;
    PORT
      LAYER met3 ;
        RECT 1396.000 850.040 1400.000 850.640 ;
    END
  END crash_dump_o[87]
  PIN crash_dump_o[88]
    DIRECTION OUTPUT ;
    USE SIGNAL ;
    ANTENNADIFFAREA 0.445500 ;
    PORT
      LAYER met3 ;
        RECT 1396.000 1298.840 1400.000 1299.440 ;
    END
  END crash_dump_o[88]
  PIN crash_dump_o[89]
    DIRECTION OUTPUT ;
    USE SIGNAL ;
    ANTENNADIFFAREA 0.445500 ;
    PORT
      LAYER met3 ;
        RECT 1396.000 1043.840 1400.000 1044.440 ;
    END
  END crash_dump_o[89]
  PIN crash_dump_o[8]
    DIRECTION OUTPUT ;
    USE SIGNAL ;
    ANTENNADIFFAREA 0.445500 ;
    PORT
      LAYER met2 ;
        RECT 1046.590 0.000 1046.870 4.000 ;
    END
  END crash_dump_o[8]
  PIN crash_dump_o[90]
    DIRECTION OUTPUT ;
    USE SIGNAL ;
    ANTENNADIFFAREA 0.445500 ;
    PORT
      LAYER met3 ;
        RECT 1396.000 1261.440 1400.000 1262.040 ;
    END
  END crash_dump_o[90]
  PIN crash_dump_o[91]
    DIRECTION OUTPUT ;
    USE SIGNAL ;
    ANTENNADIFFAREA 0.445500 ;
    PORT
      LAYER met3 ;
        RECT 1396.000 1271.640 1400.000 1272.240 ;
    END
  END crash_dump_o[91]
  PIN crash_dump_o[92]
    DIRECTION OUTPUT ;
    USE SIGNAL ;
    ANTENNADIFFAREA 0.445500 ;
    PORT
      LAYER met3 ;
        RECT 1396.000 1190.040 1400.000 1190.640 ;
    END
  END crash_dump_o[92]
  PIN crash_dump_o[93]
    DIRECTION OUTPUT ;
    USE SIGNAL ;
    ANTENNADIFFAREA 0.445500 ;
    PORT
      LAYER met3 ;
        RECT 1396.000 897.640 1400.000 898.240 ;
    END
  END crash_dump_o[93]
  PIN crash_dump_o[94]
    DIRECTION OUTPUT ;
    USE SIGNAL ;
    ANTENNADIFFAREA 0.445500 ;
    PORT
      LAYER met3 ;
        RECT 1396.000 1278.440 1400.000 1279.040 ;
    END
  END crash_dump_o[94]
  PIN crash_dump_o[95]
    DIRECTION OUTPUT ;
    USE SIGNAL ;
    ANTENNADIFFAREA 0.445500 ;
    PORT
      LAYER met3 ;
        RECT 1396.000 1023.440 1400.000 1024.040 ;
    END
  END crash_dump_o[95]
  PIN crash_dump_o[96]
    DIRECTION OUTPUT ;
    USE SIGNAL ;
    PORT
      LAYER met3 ;
        RECT 0.000 299.240 4.000 299.840 ;
    END
  END crash_dump_o[96]
  PIN crash_dump_o[97]
    DIRECTION OUTPUT ;
    USE SIGNAL ;
    ANTENNADIFFAREA 0.445500 ;
    PORT
      LAYER met2 ;
        RECT 1056.250 0.000 1056.530 4.000 ;
    END
  END crash_dump_o[97]
  PIN crash_dump_o[98]
    DIRECTION OUTPUT ;
    USE SIGNAL ;
    ANTENNADIFFAREA 0.445500 ;
    PORT
      LAYER met2 ;
        RECT 1036.930 0.000 1037.210 4.000 ;
    END
  END crash_dump_o[98]
  PIN crash_dump_o[99]
    DIRECTION OUTPUT ;
    USE SIGNAL ;
    ANTENNADIFFAREA 0.445500 ;
    PORT
      LAYER met2 ;
        RECT 998.290 0.000 998.570 4.000 ;
    END
  END crash_dump_o[99]
  PIN crash_dump_o[9]
    DIRECTION OUTPUT ;
    USE SIGNAL ;
    ANTENNADIFFAREA 0.445500 ;
    PORT
      LAYER met3 ;
        RECT 1396.000 652.840 1400.000 653.440 ;
    END
  END crash_dump_o[9]
  PIN data_addr_o[0]
    DIRECTION OUTPUT ;
    USE SIGNAL ;
    PORT
      LAYER met2 ;
        RECT 615.110 1396.000 615.390 1400.000 ;
    END
  END data_addr_o[0]
  PIN data_addr_o[10]
    DIRECTION OUTPUT ;
    USE SIGNAL ;
    ANTENNADIFFAREA 0.445500 ;
    PORT
      LAYER met3 ;
        RECT 1396.000 1132.240 1400.000 1132.840 ;
    END
  END data_addr_o[10]
  PIN data_addr_o[11]
    DIRECTION OUTPUT ;
    USE SIGNAL ;
    ANTENNADIFFAREA 0.445500 ;
    PORT
      LAYER met3 ;
        RECT 1396.000 1152.640 1400.000 1153.240 ;
    END
  END data_addr_o[11]
  PIN data_addr_o[12]
    DIRECTION OUTPUT ;
    USE SIGNAL ;
    ANTENNADIFFAREA 0.445500 ;
    PORT
      LAYER met3 ;
        RECT 1396.000 1166.240 1400.000 1166.840 ;
    END
  END data_addr_o[12]
  PIN data_addr_o[13]
    DIRECTION OUTPUT ;
    USE SIGNAL ;
    ANTENNADIFFAREA 0.445500 ;
    PORT
      LAYER met3 ;
        RECT 1396.000 1169.640 1400.000 1170.240 ;
    END
  END data_addr_o[13]
  PIN data_addr_o[14]
    DIRECTION OUTPUT ;
    USE SIGNAL ;
    ANTENNADIFFAREA 0.445500 ;
    PORT
      LAYER met3 ;
        RECT 1396.000 1234.240 1400.000 1234.840 ;
    END
  END data_addr_o[14]
  PIN data_addr_o[15]
    DIRECTION OUTPUT ;
    USE SIGNAL ;
    ANTENNADIFFAREA 0.445500 ;
    PORT
      LAYER met3 ;
        RECT 1396.000 1162.840 1400.000 1163.440 ;
    END
  END data_addr_o[15]
  PIN data_addr_o[16]
    DIRECTION OUTPUT ;
    USE SIGNAL ;
    ANTENNADIFFAREA 0.445500 ;
    PORT
      LAYER met3 ;
        RECT 1396.000 1088.040 1400.000 1088.640 ;
    END
  END data_addr_o[16]
  PIN data_addr_o[17]
    DIRECTION OUTPUT ;
    USE SIGNAL ;
    ANTENNADIFFAREA 0.445500 ;
    PORT
      LAYER met3 ;
        RECT 1396.000 1217.240 1400.000 1217.840 ;
    END
  END data_addr_o[17]
  PIN data_addr_o[18]
    DIRECTION OUTPUT ;
    USE SIGNAL ;
    ANTENNADIFFAREA 0.445500 ;
    PORT
      LAYER met3 ;
        RECT 1396.000 1064.240 1400.000 1064.840 ;
    END
  END data_addr_o[18]
  PIN data_addr_o[19]
    DIRECTION OUTPUT ;
    USE SIGNAL ;
    ANTENNADIFFAREA 0.445500 ;
    PORT
      LAYER met3 ;
        RECT 1396.000 1312.440 1400.000 1313.040 ;
    END
  END data_addr_o[19]
  PIN data_addr_o[1]
    DIRECTION OUTPUT ;
    USE SIGNAL ;
    PORT
      LAYER met3 ;
        RECT 1396.000 792.240 1400.000 792.840 ;
    END
  END data_addr_o[1]
  PIN data_addr_o[20]
    DIRECTION OUTPUT ;
    USE SIGNAL ;
    ANTENNADIFFAREA 0.445500 ;
    PORT
      LAYER met3 ;
        RECT 1396.000 1054.040 1400.000 1054.640 ;
    END
  END data_addr_o[20]
  PIN data_addr_o[21]
    DIRECTION OUTPUT ;
    USE SIGNAL ;
    ANTENNADIFFAREA 0.445500 ;
    PORT
      LAYER met3 ;
        RECT 1396.000 1135.640 1400.000 1136.240 ;
    END
  END data_addr_o[21]
  PIN data_addr_o[22]
    DIRECTION OUTPUT ;
    USE SIGNAL ;
    ANTENNADIFFAREA 0.445500 ;
    PORT
      LAYER met3 ;
        RECT 1396.000 1247.840 1400.000 1248.440 ;
    END
  END data_addr_o[22]
  PIN data_addr_o[23]
    DIRECTION OUTPUT ;
    USE SIGNAL ;
    ANTENNADIFFAREA 0.445500 ;
    PORT
      LAYER met3 ;
        RECT 1396.000 1332.840 1400.000 1333.440 ;
    END
  END data_addr_o[23]
  PIN data_addr_o[24]
    DIRECTION OUTPUT ;
    USE SIGNAL ;
    ANTENNADIFFAREA 0.445500 ;
    PORT
      LAYER met3 ;
        RECT 1396.000 1142.440 1400.000 1143.040 ;
    END
  END data_addr_o[24]
  PIN data_addr_o[25]
    DIRECTION OUTPUT ;
    USE SIGNAL ;
    ANTENNADIFFAREA 0.445500 ;
    PORT
      LAYER met3 ;
        RECT 1396.000 1207.040 1400.000 1207.640 ;
    END
  END data_addr_o[25]
  PIN data_addr_o[26]
    DIRECTION OUTPUT ;
    USE SIGNAL ;
    ANTENNADIFFAREA 0.445500 ;
    PORT
      LAYER met3 ;
        RECT 1396.000 1060.840 1400.000 1061.440 ;
    END
  END data_addr_o[26]
  PIN data_addr_o[27]
    DIRECTION OUTPUT ;
    USE SIGNAL ;
    ANTENNADIFFAREA 0.445500 ;
    PORT
      LAYER met3 ;
        RECT 1396.000 1094.840 1400.000 1095.440 ;
    END
  END data_addr_o[27]
  PIN data_addr_o[28]
    DIRECTION OUTPUT ;
    USE SIGNAL ;
    ANTENNADIFFAREA 0.445500 ;
    PORT
      LAYER met3 ;
        RECT 1396.000 1145.840 1400.000 1146.440 ;
    END
  END data_addr_o[28]
  PIN data_addr_o[29]
    DIRECTION OUTPUT ;
    USE SIGNAL ;
    ANTENNADIFFAREA 0.445500 ;
    PORT
      LAYER met3 ;
        RECT 1396.000 1081.240 1400.000 1081.840 ;
    END
  END data_addr_o[29]
  PIN data_addr_o[2]
    DIRECTION OUTPUT ;
    USE SIGNAL ;
    ANTENNADIFFAREA 0.445500 ;
    PORT
      LAYER met3 ;
        RECT 1396.000 1139.040 1400.000 1139.640 ;
    END
  END data_addr_o[2]
  PIN data_addr_o[30]
    DIRECTION OUTPUT ;
    USE SIGNAL ;
    ANTENNADIFFAREA 0.445500 ;
    PORT
      LAYER met3 ;
        RECT 1396.000 1336.240 1400.000 1336.840 ;
    END
  END data_addr_o[30]
  PIN data_addr_o[31]
    DIRECTION OUTPUT ;
    USE SIGNAL ;
    ANTENNADIFFAREA 0.445500 ;
    PORT
      LAYER met3 ;
        RECT 1396.000 1322.640 1400.000 1323.240 ;
    END
  END data_addr_o[31]
  PIN data_addr_o[3]
    DIRECTION OUTPUT ;
    USE SIGNAL ;
    ANTENNADIFFAREA 0.445500 ;
    PORT
      LAYER met3 ;
        RECT 1396.000 1288.640 1400.000 1289.240 ;
    END
  END data_addr_o[3]
  PIN data_addr_o[4]
    DIRECTION OUTPUT ;
    USE SIGNAL ;
    ANTENNADIFFAREA 0.445500 ;
    PORT
      LAYER met3 ;
        RECT 1396.000 1326.040 1400.000 1326.640 ;
    END
  END data_addr_o[4]
  PIN data_addr_o[5]
    DIRECTION OUTPUT ;
    USE SIGNAL ;
    ANTENNADIFFAREA 0.445500 ;
    PORT
      LAYER met3 ;
        RECT 1396.000 1339.640 1400.000 1340.240 ;
    END
  END data_addr_o[5]
  PIN data_addr_o[6]
    DIRECTION OUTPUT ;
    USE SIGNAL ;
    ANTENNADIFFAREA 0.445500 ;
    PORT
      LAYER met3 ;
        RECT 1396.000 928.240 1400.000 928.840 ;
    END
  END data_addr_o[6]
  PIN data_addr_o[7]
    DIRECTION OUTPUT ;
    USE SIGNAL ;
    ANTENNADIFFAREA 0.445500 ;
    PORT
      LAYER met3 ;
        RECT 1396.000 894.240 1400.000 894.840 ;
    END
  END data_addr_o[7]
  PIN data_addr_o[8]
    DIRECTION OUTPUT ;
    USE SIGNAL ;
    ANTENNADIFFAREA 0.445500 ;
    PORT
      LAYER met3 ;
        RECT 1396.000 1268.240 1400.000 1268.840 ;
    END
  END data_addr_o[8]
  PIN data_addr_o[9]
    DIRECTION OUTPUT ;
    USE SIGNAL ;
    ANTENNADIFFAREA 0.445500 ;
    PORT
      LAYER met3 ;
        RECT 1396.000 989.440 1400.000 990.040 ;
    END
  END data_addr_o[9]
  PIN data_addr_shadow_o[0]
    DIRECTION OUTPUT ;
    USE SIGNAL ;
    PORT
      LAYER met3 ;
        RECT 0.000 394.440 4.000 395.040 ;
    END
  END data_addr_shadow_o[0]
  PIN data_addr_shadow_o[10]
    DIRECTION OUTPUT ;
    USE SIGNAL ;
    PORT
      LAYER met3 ;
        RECT 1396.000 1230.840 1400.000 1231.440 ;
    END
  END data_addr_shadow_o[10]
  PIN data_addr_shadow_o[11]
    DIRECTION OUTPUT ;
    USE SIGNAL ;
    PORT
      LAYER met2 ;
        RECT 1004.730 0.000 1005.010 4.000 ;
    END
  END data_addr_shadow_o[11]
  PIN data_addr_shadow_o[12]
    DIRECTION OUTPUT ;
    USE SIGNAL ;
    PORT
      LAYER met3 ;
        RECT 0.000 329.840 4.000 330.440 ;
    END
  END data_addr_shadow_o[12]
  PIN data_addr_shadow_o[13]
    DIRECTION OUTPUT ;
    USE SIGNAL ;
    PORT
      LAYER met3 ;
        RECT 0.000 1152.640 4.000 1153.240 ;
    END
  END data_addr_shadow_o[13]
  PIN data_addr_shadow_o[14]
    DIRECTION OUTPUT ;
    USE SIGNAL ;
    PORT
      LAYER met3 ;
        RECT 0.000 248.240 4.000 248.840 ;
    END
  END data_addr_shadow_o[14]
  PIN data_addr_shadow_o[15]
    DIRECTION OUTPUT ;
    USE SIGNAL ;
    PORT
      LAYER met2 ;
        RECT 441.230 0.000 441.510 4.000 ;
    END
  END data_addr_shadow_o[15]
  PIN data_addr_shadow_o[16]
    DIRECTION OUTPUT ;
    USE SIGNAL ;
    PORT
      LAYER met2 ;
        RECT 1304.190 0.000 1304.470 4.000 ;
    END
  END data_addr_shadow_o[16]
  PIN data_addr_shadow_o[17]
    DIRECTION OUTPUT ;
    USE SIGNAL ;
    PORT
      LAYER met2 ;
        RECT 1210.810 1396.000 1211.090 1400.000 ;
    END
  END data_addr_shadow_o[17]
  PIN data_addr_shadow_o[18]
    DIRECTION OUTPUT ;
    USE SIGNAL ;
    PORT
      LAYER met2 ;
        RECT 331.750 0.000 332.030 4.000 ;
    END
  END data_addr_shadow_o[18]
  PIN data_addr_shadow_o[19]
    DIRECTION OUTPUT ;
    USE SIGNAL ;
    PORT
      LAYER met3 ;
        RECT 1396.000 486.240 1400.000 486.840 ;
    END
  END data_addr_shadow_o[19]
  PIN data_addr_shadow_o[1]
    DIRECTION OUTPUT ;
    USE SIGNAL ;
    PORT
      LAYER met3 ;
        RECT 1396.000 1315.840 1400.000 1316.440 ;
    END
  END data_addr_shadow_o[1]
  PIN data_addr_shadow_o[20]
    DIRECTION OUTPUT ;
    USE SIGNAL ;
    PORT
      LAYER met2 ;
        RECT 354.290 1396.000 354.570 1400.000 ;
    END
  END data_addr_shadow_o[20]
  PIN data_addr_shadow_o[21]
    DIRECTION OUTPUT ;
    USE SIGNAL ;
    PORT
      LAYER met3 ;
        RECT 1396.000 1108.440 1400.000 1109.040 ;
    END
  END data_addr_shadow_o[21]
  PIN data_addr_shadow_o[22]
    DIRECTION OUTPUT ;
    USE SIGNAL ;
    PORT
      LAYER met3 ;
        RECT 1396.000 1390.640 1400.000 1391.240 ;
    END
  END data_addr_shadow_o[22]
  PIN data_addr_shadow_o[23]
    DIRECTION OUTPUT ;
    USE SIGNAL ;
    PORT
      LAYER met3 ;
        RECT 0.000 1071.040 4.000 1071.640 ;
    END
  END data_addr_shadow_o[23]
  PIN data_addr_shadow_o[24]
    DIRECTION OUTPUT ;
    USE SIGNAL ;
    PORT
      LAYER met2 ;
        RECT 1185.050 1396.000 1185.330 1400.000 ;
    END
  END data_addr_shadow_o[24]
  PIN data_addr_shadow_o[25]
    DIRECTION OUTPUT ;
    USE SIGNAL ;
    PORT
      LAYER met3 ;
        RECT 1396.000 1128.840 1400.000 1129.440 ;
    END
  END data_addr_shadow_o[25]
  PIN data_addr_shadow_o[26]
    DIRECTION OUTPUT ;
    USE SIGNAL ;
    PORT
      LAYER met3 ;
        RECT 1396.000 217.640 1400.000 218.240 ;
    END
  END data_addr_shadow_o[26]
  PIN data_addr_shadow_o[27]
    DIRECTION OUTPUT ;
    USE SIGNAL ;
    PORT
      LAYER met3 ;
        RECT 1396.000 1203.640 1400.000 1204.240 ;
    END
  END data_addr_shadow_o[27]
  PIN data_addr_shadow_o[28]
    DIRECTION OUTPUT ;
    USE SIGNAL ;
    PORT
      LAYER met2 ;
        RECT 1291.310 0.000 1291.590 4.000 ;
    END
  END data_addr_shadow_o[28]
  PIN data_addr_shadow_o[29]
    DIRECTION OUTPUT ;
    USE SIGNAL ;
    PORT
      LAYER met2 ;
        RECT 660.190 1396.000 660.470 1400.000 ;
    END
  END data_addr_shadow_o[29]
  PIN data_addr_shadow_o[2]
    DIRECTION OUTPUT ;
    USE SIGNAL ;
    PORT
      LAYER met2 ;
        RECT 280.230 1396.000 280.510 1400.000 ;
    END
  END data_addr_shadow_o[2]
  PIN data_addr_shadow_o[30]
    DIRECTION OUTPUT ;
    USE SIGNAL ;
    PORT
      LAYER met2 ;
        RECT 1139.970 1396.000 1140.250 1400.000 ;
    END
  END data_addr_shadow_o[30]
  PIN data_addr_shadow_o[31]
    DIRECTION OUTPUT ;
    USE SIGNAL ;
    PORT
      LAYER met3 ;
        RECT 0.000 758.240 4.000 758.840 ;
    END
  END data_addr_shadow_o[31]
  PIN data_addr_shadow_o[3]
    DIRECTION OUTPUT ;
    USE SIGNAL ;
    PORT
      LAYER met2 ;
        RECT 90.250 1396.000 90.530 1400.000 ;
    END
  END data_addr_shadow_o[3]
  PIN data_addr_shadow_o[4]
    DIRECTION OUTPUT ;
    USE SIGNAL ;
    PORT
      LAYER met3 ;
        RECT 0.000 23.840 4.000 24.440 ;
    END
  END data_addr_shadow_o[4]
  PIN data_addr_shadow_o[5]
    DIRECTION OUTPUT ;
    USE SIGNAL ;
    PORT
      LAYER met3 ;
        RECT 1396.000 955.440 1400.000 956.040 ;
    END
  END data_addr_shadow_o[5]
  PIN data_addr_shadow_o[6]
    DIRECTION OUTPUT ;
    USE SIGNAL ;
    PORT
      LAYER met3 ;
        RECT 0.000 30.640 4.000 31.240 ;
    END
  END data_addr_shadow_o[6]
  PIN data_addr_shadow_o[7]
    DIRECTION OUTPUT ;
    USE SIGNAL ;
    PORT
      LAYER met3 ;
        RECT 0.000 999.640 4.000 1000.240 ;
    END
  END data_addr_shadow_o[7]
  PIN data_addr_shadow_o[8]
    DIRECTION OUTPUT ;
    USE SIGNAL ;
    PORT
      LAYER met3 ;
        RECT 1396.000 1349.840 1400.000 1350.440 ;
    END
  END data_addr_shadow_o[8]
  PIN data_addr_shadow_o[9]
    DIRECTION OUTPUT ;
    USE SIGNAL ;
    PORT
      LAYER met2 ;
        RECT 875.930 0.000 876.210 4.000 ;
    END
  END data_addr_shadow_o[9]
  PIN data_be_o[0]
    DIRECTION OUTPUT ;
    USE SIGNAL ;
    ANTENNADIFFAREA 0.445500 ;
    PORT
      LAYER met2 ;
        RECT 676.290 0.000 676.570 4.000 ;
    END
  END data_be_o[0]
  PIN data_be_o[1]
    DIRECTION OUTPUT ;
    USE SIGNAL ;
    ANTENNADIFFAREA 0.445500 ;
    PORT
      LAYER met2 ;
        RECT 766.450 0.000 766.730 4.000 ;
    END
  END data_be_o[1]
  PIN data_be_o[2]
    DIRECTION OUTPUT ;
    USE SIGNAL ;
    ANTENNADIFFAREA 0.445500 ;
    PORT
      LAYER met2 ;
        RECT 760.010 0.000 760.290 4.000 ;
    END
  END data_be_o[2]
  PIN data_be_o[3]
    DIRECTION OUTPUT ;
    USE SIGNAL ;
    ANTENNADIFFAREA 0.445500 ;
    PORT
      LAYER met2 ;
        RECT 776.110 0.000 776.390 4.000 ;
    END
  END data_be_o[3]
  PIN data_be_shadow_o[0]
    DIRECTION OUTPUT ;
    USE SIGNAL ;
    PORT
      LAYER met2 ;
        RECT 170.750 0.000 171.030 4.000 ;
    END
  END data_be_shadow_o[0]
  PIN data_be_shadow_o[1]
    DIRECTION OUTPUT ;
    USE SIGNAL ;
    PORT
      LAYER met2 ;
        RECT 743.910 0.000 744.190 4.000 ;
    END
  END data_be_shadow_o[1]
  PIN data_be_shadow_o[2]
    DIRECTION OUTPUT ;
    USE SIGNAL ;
    PORT
      LAYER met2 ;
        RECT 756.790 0.000 757.070 4.000 ;
    END
  END data_be_shadow_o[2]
  PIN data_be_shadow_o[3]
    DIRECTION OUTPUT ;
    USE SIGNAL ;
    PORT
      LAYER met3 ;
        RECT 1396.000 1373.640 1400.000 1374.240 ;
    END
  END data_be_shadow_o[3]
  PIN data_err_i
    DIRECTION INPUT ;
    USE SIGNAL ;
    ANTENNAGATEAREA 0.682200 ;
    ANTENNADIFFAREA 0.434700 ;
    PORT
      LAYER met2 ;
        RECT 872.710 0.000 872.990 4.000 ;
    END
  END data_err_i
  PIN data_gnt_i
    DIRECTION INPUT ;
    USE SIGNAL ;
    ANTENNAGATEAREA 0.682200 ;
    ANTENNADIFFAREA 0.434700 ;
    PORT
      LAYER met2 ;
        RECT 882.370 0.000 882.650 4.000 ;
    END
  END data_gnt_i
  PIN data_rdata_i[0]
    DIRECTION INPUT ;
    USE SIGNAL ;
    ANTENNAGATEAREA 0.647700 ;
    ANTENNADIFFAREA 0.434700 ;
    PORT
      LAYER met2 ;
        RECT 837.290 0.000 837.570 4.000 ;
    END
  END data_rdata_i[0]
  PIN data_rdata_i[10]
    DIRECTION INPUT ;
    USE SIGNAL ;
    ANTENNAGATEAREA 0.647700 ;
    ANTENNADIFFAREA 0.434700 ;
    PORT
      LAYER met2 ;
        RECT 685.950 0.000 686.230 4.000 ;
    END
  END data_rdata_i[10]
  PIN data_rdata_i[11]
    DIRECTION INPUT ;
    USE SIGNAL ;
    ANTENNAGATEAREA 0.593700 ;
    ANTENNADIFFAREA 0.434700 ;
    PORT
      LAYER met2 ;
        RECT 792.210 0.000 792.490 4.000 ;
    END
  END data_rdata_i[11]
  PIN data_rdata_i[12]
    DIRECTION INPUT ;
    USE SIGNAL ;
    ANTENNAGATEAREA 0.647700 ;
    ANTENNADIFFAREA 0.434700 ;
    PORT
      LAYER met2 ;
        RECT 863.050 0.000 863.330 4.000 ;
    END
  END data_rdata_i[12]
  PIN data_rdata_i[13]
    DIRECTION INPUT ;
    USE SIGNAL ;
    ANTENNAGATEAREA 0.593700 ;
    ANTENNADIFFAREA 0.434700 ;
    PORT
      LAYER met2 ;
        RECT 782.550 0.000 782.830 4.000 ;
    END
  END data_rdata_i[13]
  PIN data_rdata_i[14]
    DIRECTION INPUT ;
    USE SIGNAL ;
    ANTENNAGATEAREA 0.593700 ;
    ANTENNADIFFAREA 0.434700 ;
    PORT
      LAYER met2 ;
        RECT 843.730 0.000 844.010 4.000 ;
    END
  END data_rdata_i[14]
  PIN data_rdata_i[15]
    DIRECTION INPUT ;
    USE SIGNAL ;
    ANTENNAGATEAREA 0.647700 ;
    ANTENNADIFFAREA 0.434700 ;
    PORT
      LAYER met2 ;
        RECT 830.850 0.000 831.130 4.000 ;
    END
  END data_rdata_i[15]
  PIN data_rdata_i[16]
    DIRECTION INPUT ;
    USE SIGNAL ;
    ANTENNAGATEAREA 0.593700 ;
    ANTENNADIFFAREA 0.434700 ;
    PORT
      LAYER met2 ;
        RECT 811.530 0.000 811.810 4.000 ;
    END
  END data_rdata_i[16]
  PIN data_rdata_i[17]
    DIRECTION INPUT ;
    USE SIGNAL ;
    ANTENNAGATEAREA 0.593700 ;
    ANTENNADIFFAREA 0.434700 ;
    PORT
      LAYER met2 ;
        RECT 805.090 0.000 805.370 4.000 ;
    END
  END data_rdata_i[17]
  PIN data_rdata_i[18]
    DIRECTION INPUT ;
    USE SIGNAL ;
    ANTENNAGATEAREA 0.593700 ;
    ANTENNADIFFAREA 0.434700 ;
    PORT
      LAYER met2 ;
        RECT 763.230 0.000 763.510 4.000 ;
    END
  END data_rdata_i[18]
  PIN data_rdata_i[19]
    DIRECTION INPUT ;
    USE SIGNAL ;
    ANTENNAGATEAREA 0.593700 ;
    ANTENNADIFFAREA 0.434700 ;
    PORT
      LAYER met2 ;
        RECT 788.990 0.000 789.270 4.000 ;
    END
  END data_rdata_i[19]
  PIN data_rdata_i[1]
    DIRECTION INPUT ;
    USE SIGNAL ;
    ANTENNAGATEAREA 0.647700 ;
    ANTENNADIFFAREA 0.434700 ;
    PORT
      LAYER met2 ;
        RECT 817.970 0.000 818.250 4.000 ;
    END
  END data_rdata_i[1]
  PIN data_rdata_i[20]
    DIRECTION INPUT ;
    USE SIGNAL ;
    ANTENNAGATEAREA 0.593700 ;
    ANTENNADIFFAREA 0.434700 ;
    PORT
      LAYER met2 ;
        RECT 850.170 0.000 850.450 4.000 ;
    END
  END data_rdata_i[20]
  PIN data_rdata_i[21]
    DIRECTION INPUT ;
    USE SIGNAL ;
    ANTENNAGATEAREA 0.593700 ;
    ANTENNADIFFAREA 0.434700 ;
    PORT
      LAYER met2 ;
        RECT 785.770 0.000 786.050 4.000 ;
    END
  END data_rdata_i[21]
  PIN data_rdata_i[22]
    DIRECTION INPUT ;
    USE SIGNAL ;
    ANTENNAGATEAREA 0.647700 ;
    ANTENNADIFFAREA 0.434700 ;
    PORT
      LAYER met2 ;
        RECT 856.610 0.000 856.890 4.000 ;
    END
  END data_rdata_i[22]
  PIN data_rdata_i[23]
    DIRECTION INPUT ;
    USE SIGNAL ;
    ANTENNAGATEAREA 0.647700 ;
    ANTENNADIFFAREA 0.434700 ;
    PORT
      LAYER met2 ;
        RECT 827.630 0.000 827.910 4.000 ;
    END
  END data_rdata_i[23]
  PIN data_rdata_i[24]
    DIRECTION INPUT ;
    USE SIGNAL ;
    ANTENNAGATEAREA 0.593700 ;
    ANTENNADIFFAREA 0.434700 ;
    PORT
      LAYER met2 ;
        RECT 821.190 0.000 821.470 4.000 ;
    END
  END data_rdata_i[24]
  PIN data_rdata_i[25]
    DIRECTION INPUT ;
    USE SIGNAL ;
    ANTENNAGATEAREA 0.593700 ;
    ANTENNADIFFAREA 0.434700 ;
    PORT
      LAYER met2 ;
        RECT 814.750 0.000 815.030 4.000 ;
    END
  END data_rdata_i[25]
  PIN data_rdata_i[26]
    DIRECTION INPUT ;
    USE SIGNAL ;
    ANTENNAGATEAREA 0.593700 ;
    ANTENNADIFFAREA 0.434700 ;
    PORT
      LAYER met2 ;
        RECT 753.570 0.000 753.850 4.000 ;
    END
  END data_rdata_i[26]
  PIN data_rdata_i[27]
    DIRECTION INPUT ;
    USE SIGNAL ;
    ANTENNAGATEAREA 0.593700 ;
    ANTENNADIFFAREA 0.434700 ;
    PORT
      LAYER met2 ;
        RECT 798.650 0.000 798.930 4.000 ;
    END
  END data_rdata_i[27]
  PIN data_rdata_i[28]
    DIRECTION INPUT ;
    USE SIGNAL ;
    ANTENNAGATEAREA 0.593700 ;
    ANTENNADIFFAREA 0.434700 ;
    PORT
      LAYER met2 ;
        RECT 859.830 0.000 860.110 4.000 ;
    END
  END data_rdata_i[28]
  PIN data_rdata_i[29]
    DIRECTION INPUT ;
    USE SIGNAL ;
    ANTENNAGATEAREA 0.647700 ;
    ANTENNADIFFAREA 0.434700 ;
    PORT
      LAYER met2 ;
        RECT 740.690 0.000 740.970 4.000 ;
    END
  END data_rdata_i[29]
  PIN data_rdata_i[2]
    DIRECTION INPUT ;
    USE SIGNAL ;
    ANTENNAGATEAREA 0.593700 ;
    ANTENNADIFFAREA 0.434700 ;
    PORT
      LAYER met2 ;
        RECT 779.330 0.000 779.610 4.000 ;
    END
  END data_rdata_i[2]
  PIN data_rdata_i[30]
    DIRECTION INPUT ;
    USE SIGNAL ;
    ANTENNAGATEAREA 0.593700 ;
    ANTENNADIFFAREA 0.434700 ;
    PORT
      LAYER met2 ;
        RECT 869.490 0.000 869.770 4.000 ;
    END
  END data_rdata_i[30]
  PIN data_rdata_i[31]
    DIRECTION INPUT ;
    USE SIGNAL ;
    ANTENNAGATEAREA 0.647700 ;
    ANTENNADIFFAREA 0.434700 ;
    PORT
      LAYER met2 ;
        RECT 853.390 0.000 853.670 4.000 ;
    END
  END data_rdata_i[31]
  PIN data_rdata_i[3]
    DIRECTION INPUT ;
    USE SIGNAL ;
    ANTENNAGATEAREA 0.593700 ;
    ANTENNADIFFAREA 0.434700 ;
    PORT
      LAYER met2 ;
        RECT 795.430 0.000 795.710 4.000 ;
    END
  END data_rdata_i[3]
  PIN data_rdata_i[4]
    DIRECTION INPUT ;
    USE SIGNAL ;
    ANTENNAGATEAREA 0.593700 ;
    ANTENNADIFFAREA 0.434700 ;
    PORT
      LAYER met2 ;
        RECT 834.070 0.000 834.350 4.000 ;
    END
  END data_rdata_i[4]
  PIN data_rdata_i[5]
    DIRECTION INPUT ;
    USE SIGNAL ;
    ANTENNAGATEAREA 0.593700 ;
    ANTENNADIFFAREA 0.434700 ;
    PORT
      LAYER met2 ;
        RECT 769.670 0.000 769.950 4.000 ;
    END
  END data_rdata_i[5]
  PIN data_rdata_i[6]
    DIRECTION INPUT ;
    USE SIGNAL ;
    ANTENNAGATEAREA 0.647700 ;
    ANTENNADIFFAREA 0.434700 ;
    PORT
      LAYER met2 ;
        RECT 840.510 0.000 840.790 4.000 ;
    END
  END data_rdata_i[6]
  PIN data_rdata_i[7]
    DIRECTION INPUT ;
    USE SIGNAL ;
    ANTENNAGATEAREA 0.593700 ;
    ANTENNADIFFAREA 0.434700 ;
    PORT
      LAYER met2 ;
        RECT 824.410 0.000 824.690 4.000 ;
    END
  END data_rdata_i[7]
  PIN data_rdata_i[8]
    DIRECTION INPUT ;
    USE SIGNAL ;
    ANTENNAGATEAREA 0.593700 ;
    ANTENNADIFFAREA 0.434700 ;
    PORT
      LAYER met2 ;
        RECT 808.310 0.000 808.590 4.000 ;
    END
  END data_rdata_i[8]
  PIN data_rdata_i[9]
    DIRECTION INPUT ;
    USE SIGNAL ;
    ANTENNAGATEAREA 0.593700 ;
    ANTENNADIFFAREA 0.434700 ;
    PORT
      LAYER met2 ;
        RECT 801.870 0.000 802.150 4.000 ;
    END
  END data_rdata_i[9]
  PIN data_rdata_intg_i[0]
    DIRECTION INPUT ;
    USE SIGNAL ;
    PORT
      LAYER met2 ;
        RECT 29.070 0.000 29.350 4.000 ;
    END
  END data_rdata_intg_i[0]
  PIN data_rdata_intg_i[1]
    DIRECTION INPUT ;
    USE SIGNAL ;
    PORT
      LAYER met2 ;
        RECT 32.290 0.000 32.570 4.000 ;
    END
  END data_rdata_intg_i[1]
  PIN data_rdata_intg_i[2]
    DIRECTION INPUT ;
    USE SIGNAL ;
    PORT
      LAYER met2 ;
        RECT 51.610 0.000 51.890 4.000 ;
    END
  END data_rdata_intg_i[2]
  PIN data_rdata_intg_i[3]
    DIRECTION INPUT ;
    USE SIGNAL ;
    PORT
      LAYER met2 ;
        RECT 180.410 0.000 180.690 4.000 ;
    END
  END data_rdata_intg_i[3]
  PIN data_rdata_intg_i[4]
    DIRECTION INPUT ;
    USE SIGNAL ;
    PORT
      LAYER met2 ;
        RECT 61.270 0.000 61.550 4.000 ;
    END
  END data_rdata_intg_i[4]
  PIN data_rdata_intg_i[5]
    DIRECTION INPUT ;
    USE SIGNAL ;
    PORT
      LAYER met2 ;
        RECT 45.170 0.000 45.450 4.000 ;
    END
  END data_rdata_intg_i[5]
  PIN data_rdata_intg_i[6]
    DIRECTION INPUT ;
    USE SIGNAL ;
    PORT
      LAYER met2 ;
        RECT 48.390 0.000 48.670 4.000 ;
    END
  END data_rdata_intg_i[6]
  PIN data_req_o
    DIRECTION OUTPUT ;
    USE SIGNAL ;
    ANTENNADIFFAREA 0.445500 ;
    PORT
      LAYER met2 ;
        RECT 879.150 0.000 879.430 4.000 ;
    END
  END data_req_o
  PIN data_req_shadow_o
    DIRECTION OUTPUT ;
    USE SIGNAL ;
    PORT
      LAYER met2 ;
        RECT 93.470 1396.000 93.750 1400.000 ;
    END
  END data_req_shadow_o
  PIN data_rvalid_i
    DIRECTION INPUT ;
    USE SIGNAL ;
    ANTENNAGATEAREA 0.593700 ;
    ANTENNADIFFAREA 0.434700 ;
    PORT
      LAYER met2 ;
        RECT 885.590 0.000 885.870 4.000 ;
    END
  END data_rvalid_i
  PIN data_wdata_intg_o[0]
    DIRECTION OUTPUT ;
    USE SIGNAL ;
    PORT
      LAYER met2 ;
        RECT 483.090 0.000 483.370 4.000 ;
    END
  END data_wdata_intg_o[0]
  PIN data_wdata_intg_o[1]
    DIRECTION OUTPUT ;
    USE SIGNAL ;
    PORT
      LAYER met3 ;
        RECT 1396.000 1295.440 1400.000 1296.040 ;
    END
  END data_wdata_intg_o[1]
  PIN data_wdata_intg_o[2]
    DIRECTION OUTPUT ;
    USE SIGNAL ;
    PORT
      LAYER met3 ;
        RECT 1396.000 938.440 1400.000 939.040 ;
    END
  END data_wdata_intg_o[2]
  PIN data_wdata_intg_o[3]
    DIRECTION OUTPUT ;
    USE SIGNAL ;
    PORT
      LAYER met2 ;
        RECT 721.370 1396.000 721.650 1400.000 ;
    END
  END data_wdata_intg_o[3]
  PIN data_wdata_intg_o[4]
    DIRECTION OUTPUT ;
    USE SIGNAL ;
    PORT
      LAYER met2 ;
        RECT 438.010 0.000 438.290 4.000 ;
    END
  END data_wdata_intg_o[4]
  PIN data_wdata_intg_o[5]
    DIRECTION OUTPUT ;
    USE SIGNAL ;
    PORT
      LAYER met3 ;
        RECT 0.000 241.440 4.000 242.040 ;
    END
  END data_wdata_intg_o[5]
  PIN data_wdata_intg_o[6]
    DIRECTION OUTPUT ;
    USE SIGNAL ;
    PORT
      LAYER met2 ;
        RECT 1365.370 0.000 1365.650 4.000 ;
    END
  END data_wdata_intg_o[6]
  PIN data_wdata_intg_shadow_o[0]
    DIRECTION OUTPUT ;
    USE SIGNAL ;
    PORT
      LAYER met3 ;
        RECT 1396.000 686.840 1400.000 687.440 ;
    END
  END data_wdata_intg_shadow_o[0]
  PIN data_wdata_intg_shadow_o[1]
    DIRECTION OUTPUT ;
    USE SIGNAL ;
    PORT
      LAYER met3 ;
        RECT 0.000 941.840 4.000 942.440 ;
    END
  END data_wdata_intg_shadow_o[1]
  PIN data_wdata_intg_shadow_o[2]
    DIRECTION OUTPUT ;
    USE SIGNAL ;
    PORT
      LAYER met3 ;
        RECT 0.000 37.440 4.000 38.040 ;
    END
  END data_wdata_intg_shadow_o[2]
  PIN data_wdata_intg_shadow_o[3]
    DIRECTION OUTPUT ;
    USE SIGNAL ;
    PORT
      LAYER met3 ;
        RECT 0.000 1003.040 4.000 1003.640 ;
    END
  END data_wdata_intg_shadow_o[3]
  PIN data_wdata_intg_shadow_o[4]
    DIRECTION OUTPUT ;
    USE SIGNAL ;
    PORT
      LAYER met3 ;
        RECT 1396.000 693.640 1400.000 694.240 ;
    END
  END data_wdata_intg_shadow_o[4]
  PIN data_wdata_intg_shadow_o[5]
    DIRECTION OUTPUT ;
    USE SIGNAL ;
    PORT
      LAYER met3 ;
        RECT 1396.000 241.440 1400.000 242.040 ;
    END
  END data_wdata_intg_shadow_o[5]
  PIN data_wdata_intg_shadow_o[6]
    DIRECTION OUTPUT ;
    USE SIGNAL ;
    PORT
      LAYER met2 ;
        RECT 1178.610 1396.000 1178.890 1400.000 ;
    END
  END data_wdata_intg_shadow_o[6]
  PIN data_wdata_o[0]
    DIRECTION OUTPUT ;
    USE SIGNAL ;
    ANTENNADIFFAREA 0.445500 ;
    PORT
      LAYER met2 ;
        RECT 698.830 1396.000 699.110 1400.000 ;
    END
  END data_wdata_o[0]
  PIN data_wdata_o[10]
    DIRECTION OUTPUT ;
    USE SIGNAL ;
    ANTENNADIFFAREA 0.445500 ;
    PORT
      LAYER met2 ;
        RECT 669.850 1396.000 670.130 1400.000 ;
    END
  END data_wdata_o[10]
  PIN data_wdata_o[11]
    DIRECTION OUTPUT ;
    USE SIGNAL ;
    ANTENNADIFFAREA 0.445500 ;
    PORT
      LAYER met2 ;
        RECT 689.170 0.000 689.450 4.000 ;
    END
  END data_wdata_o[11]
  PIN data_wdata_o[12]
    DIRECTION OUTPUT ;
    USE SIGNAL ;
    ANTENNADIFFAREA 0.445500 ;
    PORT
      LAYER met2 ;
        RECT 692.390 1396.000 692.670 1400.000 ;
    END
  END data_wdata_o[12]
  PIN data_wdata_o[13]
    DIRECTION OUTPUT ;
    USE SIGNAL ;
    ANTENNADIFFAREA 0.445500 ;
    PORT
      LAYER met2 ;
        RECT 692.390 0.000 692.670 4.000 ;
    END
  END data_wdata_o[13]
  PIN data_wdata_o[14]
    DIRECTION OUTPUT ;
    USE SIGNAL ;
    ANTENNADIFFAREA 0.445500 ;
    PORT
      LAYER met2 ;
        RECT 711.710 1396.000 711.990 1400.000 ;
    END
  END data_wdata_o[14]
  PIN data_wdata_o[15]
    DIRECTION OUTPUT ;
    USE SIGNAL ;
    ANTENNADIFFAREA 0.445500 ;
    PORT
      LAYER met2 ;
        RECT 705.270 0.000 705.550 4.000 ;
    END
  END data_wdata_o[15]
  PIN data_wdata_o[16]
    DIRECTION OUTPUT ;
    USE SIGNAL ;
    ANTENNADIFFAREA 0.445500 ;
    PORT
      LAYER met2 ;
        RECT 673.070 1396.000 673.350 1400.000 ;
    END
  END data_wdata_o[16]
  PIN data_wdata_o[17]
    DIRECTION OUTPUT ;
    USE SIGNAL ;
    ANTENNADIFFAREA 0.445500 ;
    PORT
      LAYER met2 ;
        RECT 724.590 0.000 724.870 4.000 ;
    END
  END data_wdata_o[17]
  PIN data_wdata_o[18]
    DIRECTION OUTPUT ;
    USE SIGNAL ;
    ANTENNADIFFAREA 0.445500 ;
    PORT
      LAYER met2 ;
        RECT 682.730 1396.000 683.010 1400.000 ;
    END
  END data_wdata_o[18]
  PIN data_wdata_o[19]
    DIRECTION OUTPUT ;
    USE SIGNAL ;
    ANTENNADIFFAREA 0.445500 ;
    PORT
      LAYER met2 ;
        RECT 747.130 0.000 747.410 4.000 ;
    END
  END data_wdata_o[19]
  PIN data_wdata_o[1]
    DIRECTION OUTPUT ;
    USE SIGNAL ;
    ANTENNADIFFAREA 0.445500 ;
    PORT
      LAYER met2 ;
        RECT 705.270 1396.000 705.550 1400.000 ;
    END
  END data_wdata_o[1]
  PIN data_wdata_o[20]
    DIRECTION OUTPUT ;
    USE SIGNAL ;
    ANTENNADIFFAREA 0.445500 ;
    PORT
      LAYER met2 ;
        RECT 679.510 1396.000 679.790 1400.000 ;
    END
  END data_wdata_o[20]
  PIN data_wdata_o[21]
    DIRECTION OUTPUT ;
    USE SIGNAL ;
    ANTENNADIFFAREA 0.445500 ;
    PORT
      LAYER met2 ;
        RECT 679.510 0.000 679.790 4.000 ;
    END
  END data_wdata_o[21]
  PIN data_wdata_o[22]
    DIRECTION OUTPUT ;
    USE SIGNAL ;
    ANTENNADIFFAREA 0.445500 ;
    PORT
      LAYER met2 ;
        RECT 685.950 1396.000 686.230 1400.000 ;
    END
  END data_wdata_o[22]
  PIN data_wdata_o[23]
    DIRECTION OUTPUT ;
    USE SIGNAL ;
    ANTENNADIFFAREA 0.445500 ;
    PORT
      LAYER met2 ;
        RECT 708.490 1396.000 708.770 1400.000 ;
    END
  END data_wdata_o[23]
  PIN data_wdata_o[24]
    DIRECTION OUTPUT ;
    USE SIGNAL ;
    ANTENNADIFFAREA 0.445500 ;
    PORT
      LAYER met2 ;
        RECT 695.610 1396.000 695.890 1400.000 ;
    END
  END data_wdata_o[24]
  PIN data_wdata_o[25]
    DIRECTION OUTPUT ;
    USE SIGNAL ;
    ANTENNADIFFAREA 0.445500 ;
    PORT
      LAYER met2 ;
        RECT 721.370 0.000 721.650 4.000 ;
    END
  END data_wdata_o[25]
  PIN data_wdata_o[26]
    DIRECTION OUTPUT ;
    USE SIGNAL ;
    ANTENNADIFFAREA 0.445500 ;
    PORT
      LAYER met2 ;
        RECT 698.830 0.000 699.110 4.000 ;
    END
  END data_wdata_o[26]
  PIN data_wdata_o[27]
    DIRECTION OUTPUT ;
    USE SIGNAL ;
    ANTENNADIFFAREA 0.445500 ;
    PORT
      LAYER met2 ;
        RECT 737.470 0.000 737.750 4.000 ;
    END
  END data_wdata_o[27]
  PIN data_wdata_o[28]
    DIRECTION OUTPUT ;
    USE SIGNAL ;
    ANTENNADIFFAREA 0.445500 ;
    PORT
      LAYER met2 ;
        RECT 734.250 0.000 734.530 4.000 ;
    END
  END data_wdata_o[28]
  PIN data_wdata_o[29]
    DIRECTION OUTPUT ;
    USE SIGNAL ;
    ANTENNADIFFAREA 0.445500 ;
    PORT
      LAYER met2 ;
        RECT 708.490 0.000 708.770 4.000 ;
    END
  END data_wdata_o[29]
  PIN data_wdata_o[2]
    DIRECTION OUTPUT ;
    USE SIGNAL ;
    ANTENNADIFFAREA 0.445500 ;
    PORT
      LAYER met2 ;
        RECT 695.610 0.000 695.890 4.000 ;
    END
  END data_wdata_o[2]
  PIN data_wdata_o[30]
    DIRECTION OUTPUT ;
    USE SIGNAL ;
    ANTENNADIFFAREA 0.445500 ;
    PORT
      LAYER met2 ;
        RECT 714.930 1396.000 715.210 1400.000 ;
    END
  END data_wdata_o[30]
  PIN data_wdata_o[31]
    DIRECTION OUTPUT ;
    USE SIGNAL ;
    ANTENNADIFFAREA 0.445500 ;
    PORT
      LAYER met2 ;
        RECT 711.710 0.000 711.990 4.000 ;
    END
  END data_wdata_o[31]
  PIN data_wdata_o[3]
    DIRECTION OUTPUT ;
    USE SIGNAL ;
    ANTENNADIFFAREA 0.445500 ;
    PORT
      LAYER met2 ;
        RECT 731.030 0.000 731.310 4.000 ;
    END
  END data_wdata_o[3]
  PIN data_wdata_o[4]
    DIRECTION OUTPUT ;
    USE SIGNAL ;
    ANTENNADIFFAREA 0.445500 ;
    PORT
      LAYER met2 ;
        RECT 689.170 1396.000 689.450 1400.000 ;
    END
  END data_wdata_o[4]
  PIN data_wdata_o[5]
    DIRECTION OUTPUT ;
    USE SIGNAL ;
    ANTENNADIFFAREA 0.445500 ;
    PORT
      LAYER met2 ;
        RECT 682.730 0.000 683.010 4.000 ;
    END
  END data_wdata_o[5]
  PIN data_wdata_o[6]
    DIRECTION OUTPUT ;
    USE SIGNAL ;
    ANTENNADIFFAREA 0.445500 ;
    PORT
      LAYER met2 ;
        RECT 727.810 0.000 728.090 4.000 ;
    END
  END data_wdata_o[6]
  PIN data_wdata_o[7]
    DIRECTION OUTPUT ;
    USE SIGNAL ;
    ANTENNADIFFAREA 0.445500 ;
    PORT
      LAYER met2 ;
        RECT 702.050 1396.000 702.330 1400.000 ;
    END
  END data_wdata_o[7]
  PIN data_wdata_o[8]
    DIRECTION OUTPUT ;
    USE SIGNAL ;
    ANTENNADIFFAREA 0.445500 ;
    PORT
      LAYER met2 ;
        RECT 676.290 1396.000 676.570 1400.000 ;
    END
  END data_wdata_o[8]
  PIN data_wdata_o[9]
    DIRECTION OUTPUT ;
    USE SIGNAL ;
    ANTENNADIFFAREA 0.445500 ;
    PORT
      LAYER met2 ;
        RECT 714.930 0.000 715.210 4.000 ;
    END
  END data_wdata_o[9]
  PIN data_wdata_shadow_o[0]
    DIRECTION OUTPUT ;
    USE SIGNAL ;
    PORT
      LAYER met2 ;
        RECT 212.610 0.000 212.890 4.000 ;
    END
  END data_wdata_shadow_o[0]
  PIN data_wdata_shadow_o[10]
    DIRECTION OUTPUT ;
    USE SIGNAL ;
    PORT
      LAYER met3 ;
        RECT 1396.000 244.840 1400.000 245.440 ;
    END
  END data_wdata_shadow_o[10]
  PIN data_wdata_shadow_o[11]
    DIRECTION OUTPUT ;
    USE SIGNAL ;
    PORT
      LAYER met2 ;
        RECT 766.450 1396.000 766.730 1400.000 ;
    END
  END data_wdata_shadow_o[11]
  PIN data_wdata_shadow_o[12]
    DIRECTION OUTPUT ;
    USE SIGNAL ;
    PORT
      LAYER met3 ;
        RECT 0.000 244.840 4.000 245.440 ;
    END
  END data_wdata_shadow_o[12]
  PIN data_wdata_shadow_o[13]
    DIRECTION OUTPUT ;
    USE SIGNAL ;
    PORT
      LAYER met2 ;
        RECT 772.890 0.000 773.170 4.000 ;
    END
  END data_wdata_shadow_o[13]
  PIN data_wdata_shadow_o[14]
    DIRECTION OUTPUT ;
    USE SIGNAL ;
    PORT
      LAYER met3 ;
        RECT 1396.000 557.640 1400.000 558.240 ;
    END
  END data_wdata_shadow_o[14]
  PIN data_wdata_shadow_o[15]
    DIRECTION OUTPUT ;
    USE SIGNAL ;
    PORT
      LAYER met3 ;
        RECT 0.000 1006.440 4.000 1007.040 ;
    END
  END data_wdata_shadow_o[15]
  PIN data_wdata_shadow_o[16]
    DIRECTION OUTPUT ;
    USE SIGNAL ;
    PORT
      LAYER met2 ;
        RECT 792.210 1396.000 792.490 1400.000 ;
    END
  END data_wdata_shadow_o[16]
  PIN data_wdata_shadow_o[17]
    DIRECTION OUTPUT ;
    USE SIGNAL ;
    PORT
      LAYER met2 ;
        RECT 106.350 1396.000 106.630 1400.000 ;
    END
  END data_wdata_shadow_o[17]
  PIN data_wdata_shadow_o[18]
    DIRECTION OUTPUT ;
    USE SIGNAL ;
    PORT
      LAYER met2 ;
        RECT 1371.810 0.000 1372.090 4.000 ;
    END
  END data_wdata_shadow_o[18]
  PIN data_wdata_shadow_o[19]
    DIRECTION OUTPUT ;
    USE SIGNAL ;
    PORT
      LAYER met3 ;
        RECT 1396.000 353.640 1400.000 354.240 ;
    END
  END data_wdata_shadow_o[19]
  PIN data_wdata_shadow_o[1]
    DIRECTION OUTPUT ;
    USE SIGNAL ;
    PORT
      LAYER met3 ;
        RECT 1396.000 445.440 1400.000 446.040 ;
    END
  END data_wdata_shadow_o[1]
  PIN data_wdata_shadow_o[20]
    DIRECTION OUTPUT ;
    USE SIGNAL ;
    PORT
      LAYER met2 ;
        RECT 1307.410 0.000 1307.690 4.000 ;
    END
  END data_wdata_shadow_o[20]
  PIN data_wdata_shadow_o[21]
    DIRECTION OUTPUT ;
    USE SIGNAL ;
    PORT
      LAYER met3 ;
        RECT 0.000 829.640 4.000 830.240 ;
    END
  END data_wdata_shadow_o[21]
  PIN data_wdata_shadow_o[22]
    DIRECTION OUTPUT ;
    USE SIGNAL ;
    PORT
      LAYER met3 ;
        RECT 1396.000 343.440 1400.000 344.040 ;
    END
  END data_wdata_shadow_o[22]
  PIN data_wdata_shadow_o[23]
    DIRECTION OUTPUT ;
    USE SIGNAL ;
    PORT
      LAYER met3 ;
        RECT 0.000 635.840 4.000 636.440 ;
    END
  END data_wdata_shadow_o[23]
  PIN data_wdata_shadow_o[24]
    DIRECTION OUTPUT ;
    USE SIGNAL ;
    PORT
      LAYER met2 ;
        RECT 1297.750 0.000 1298.030 4.000 ;
    END
  END data_wdata_shadow_o[24]
  PIN data_wdata_shadow_o[25]
    DIRECTION OUTPUT ;
    USE SIGNAL ;
    PORT
      LAYER met2 ;
        RECT 48.390 1396.000 48.670 1400.000 ;
    END
  END data_wdata_shadow_o[25]
  PIN data_wdata_shadow_o[26]
    DIRECTION OUTPUT ;
    USE SIGNAL ;
    PORT
      LAYER met2 ;
        RECT 879.150 1396.000 879.430 1400.000 ;
    END
  END data_wdata_shadow_o[26]
  PIN data_wdata_shadow_o[27]
    DIRECTION OUTPUT ;
    USE SIGNAL ;
    PORT
      LAYER met2 ;
        RECT 1194.710 1396.000 1194.990 1400.000 ;
    END
  END data_wdata_shadow_o[27]
  PIN data_wdata_shadow_o[28]
    DIRECTION OUTPUT ;
    USE SIGNAL ;
    PORT
      LAYER met3 ;
        RECT 0.000 34.040 4.000 34.640 ;
    END
  END data_wdata_shadow_o[28]
  PIN data_wdata_shadow_o[29]
    DIRECTION OUTPUT ;
    USE SIGNAL ;
    PORT
      LAYER met2 ;
        RECT 985.410 1396.000 985.690 1400.000 ;
    END
  END data_wdata_shadow_o[29]
  PIN data_wdata_shadow_o[2]
    DIRECTION OUTPUT ;
    USE SIGNAL ;
    PORT
      LAYER met2 ;
        RECT 338.190 1396.000 338.470 1400.000 ;
    END
  END data_wdata_shadow_o[2]
  PIN data_wdata_shadow_o[30]
    DIRECTION OUTPUT ;
    USE SIGNAL ;
    PORT
      LAYER met2 ;
        RECT 1069.130 1396.000 1069.410 1400.000 ;
    END
  END data_wdata_shadow_o[30]
  PIN data_wdata_shadow_o[31]
    DIRECTION OUTPUT ;
    USE SIGNAL ;
    PORT
      LAYER met2 ;
        RECT 975.750 0.000 976.030 4.000 ;
    END
  END data_wdata_shadow_o[31]
  PIN data_wdata_shadow_o[3]
    DIRECTION OUTPUT ;
    USE SIGNAL ;
    PORT
      LAYER met3 ;
        RECT 0.000 27.240 4.000 27.840 ;
    END
  END data_wdata_shadow_o[3]
  PIN data_wdata_shadow_o[4]
    DIRECTION OUTPUT ;
    USE SIGNAL ;
    PORT
      LAYER met3 ;
        RECT 1396.000 982.640 1400.000 983.240 ;
    END
  END data_wdata_shadow_o[4]
  PIN data_wdata_shadow_o[5]
    DIRECTION OUTPUT ;
    USE SIGNAL ;
    PORT
      LAYER met3 ;
        RECT 1396.000 1394.040 1400.000 1394.640 ;
    END
  END data_wdata_shadow_o[5]
  PIN data_wdata_shadow_o[6]
    DIRECTION OUTPUT ;
    USE SIGNAL ;
    PORT
      LAYER met3 ;
        RECT 1396.000 748.040 1400.000 748.640 ;
    END
  END data_wdata_shadow_o[6]
  PIN data_wdata_shadow_o[7]
    DIRECTION OUTPUT ;
    USE SIGNAL ;
    PORT
      LAYER met3 ;
        RECT 0.000 986.040 4.000 986.640 ;
    END
  END data_wdata_shadow_o[7]
  PIN data_wdata_shadow_o[8]
    DIRECTION OUTPUT ;
    USE SIGNAL ;
    PORT
      LAYER met2 ;
        RECT 1091.670 0.000 1091.950 4.000 ;
    END
  END data_wdata_shadow_o[8]
  PIN data_wdata_shadow_o[9]
    DIRECTION OUTPUT ;
    USE SIGNAL ;
    PORT
      LAYER met3 ;
        RECT 1396.000 1387.240 1400.000 1387.840 ;
    END
  END data_wdata_shadow_o[9]
  PIN data_we_o
    DIRECTION OUTPUT ;
    USE SIGNAL ;
    ANTENNADIFFAREA 0.445500 ;
    PORT
      LAYER met2 ;
        RECT 866.270 0.000 866.550 4.000 ;
    END
  END data_we_o
  PIN data_we_shadow_o
    DIRECTION OUTPUT ;
    USE SIGNAL ;
    PORT
      LAYER met3 ;
        RECT 1396.000 1115.240 1400.000 1115.840 ;
    END
  END data_we_shadow_o
  PIN debug_req_i
    DIRECTION INPUT ;
    USE SIGNAL ;
    ANTENNAGATEAREA 0.631200 ;
    ANTENNADIFFAREA 0.434700 ;
    PORT
      LAYER met3 ;
        RECT 1396.000 496.440 1400.000 497.040 ;
    END
  END debug_req_i
  PIN double_fault_seen_o
    DIRECTION OUTPUT ;
    USE SIGNAL ;
    ANTENNADIFFAREA 0.445500 ;
    PORT
      LAYER met3 ;
        RECT 1396.000 591.640 1400.000 592.240 ;
    END
  END double_fault_seen_o
  PIN fetch_enable_i[0]
    DIRECTION INPUT ;
    USE SIGNAL ;
    ANTENNAGATEAREA 0.682200 ;
    ANTENNADIFFAREA 0.434700 ;
    PORT
      LAYER met2 ;
        RECT 988.630 0.000 988.910 4.000 ;
    END
  END fetch_enable_i[0]
  PIN fetch_enable_i[1]
    DIRECTION INPUT ;
    USE SIGNAL ;
    PORT
      LAYER met2 ;
        RECT 64.490 0.000 64.770 4.000 ;
    END
  END fetch_enable_i[1]
  PIN fetch_enable_i[2]
    DIRECTION INPUT ;
    USE SIGNAL ;
    PORT
      LAYER met2 ;
        RECT 112.790 0.000 113.070 4.000 ;
    END
  END fetch_enable_i[2]
  PIN fetch_enable_i[3]
    DIRECTION INPUT ;
    USE SIGNAL ;
    PORT
      LAYER met2 ;
        RECT 116.010 0.000 116.290 4.000 ;
    END
  END fetch_enable_i[3]
  PIN hart_id_i[0]
    DIRECTION INPUT ;
    USE SIGNAL ;
    ANTENNAGATEAREA 0.647700 ;
    ANTENNADIFFAREA 0.434700 ;
    PORT
      LAYER met3 ;
        RECT 1396.000 618.840 1400.000 619.440 ;
    END
  END hart_id_i[0]
  PIN hart_id_i[10]
    DIRECTION INPUT ;
    USE SIGNAL ;
    ANTENNAGATEAREA 0.631200 ;
    ANTENNADIFFAREA 0.434700 ;
    PORT
      LAYER met3 ;
        RECT 1396.000 680.040 1400.000 680.640 ;
    END
  END hart_id_i[10]
  PIN hart_id_i[11]
    DIRECTION INPUT ;
    USE SIGNAL ;
    ANTENNAGATEAREA 0.647700 ;
    ANTENNADIFFAREA 0.434700 ;
    PORT
      LAYER met3 ;
        RECT 1396.000 707.240 1400.000 707.840 ;
    END
  END hart_id_i[11]
  PIN hart_id_i[12]
    DIRECTION INPUT ;
    USE SIGNAL ;
    ANTENNAGATEAREA 0.631200 ;
    ANTENNADIFFAREA 0.434700 ;
    PORT
      LAYER met3 ;
        RECT 1396.000 669.840 1400.000 670.440 ;
    END
  END hart_id_i[12]
  PIN hart_id_i[13]
    DIRECTION INPUT ;
    USE SIGNAL ;
    ANTENNAGATEAREA 0.560700 ;
    ANTENNADIFFAREA 0.434700 ;
    PORT
      LAYER met3 ;
        RECT 1396.000 703.840 1400.000 704.440 ;
    END
  END hart_id_i[13]
  PIN hart_id_i[14]
    DIRECTION INPUT ;
    USE SIGNAL ;
    ANTENNAGATEAREA 0.631200 ;
    ANTENNADIFFAREA 0.434700 ;
    PORT
      LAYER met3 ;
        RECT 1396.000 724.240 1400.000 724.840 ;
    END
  END hart_id_i[14]
  PIN hart_id_i[15]
    DIRECTION INPUT ;
    USE SIGNAL ;
    ANTENNAGATEAREA 0.560700 ;
    ANTENNADIFFAREA 0.434700 ;
    PORT
      LAYER met3 ;
        RECT 1396.000 731.040 1400.000 731.640 ;
    END
  END hart_id_i[15]
  PIN hart_id_i[16]
    DIRECTION INPUT ;
    USE SIGNAL ;
    ANTENNAGATEAREA 0.560700 ;
    ANTENNADIFFAREA 0.434700 ;
    PORT
      LAYER met3 ;
        RECT 1396.000 765.040 1400.000 765.640 ;
    END
  END hart_id_i[16]
  PIN hart_id_i[17]
    DIRECTION INPUT ;
    USE SIGNAL ;
    ANTENNAGATEAREA 0.560700 ;
    ANTENNADIFFAREA 0.434700 ;
    PORT
      LAYER met3 ;
        RECT 1396.000 782.040 1400.000 782.640 ;
    END
  END hart_id_i[17]
  PIN hart_id_i[18]
    DIRECTION INPUT ;
    USE SIGNAL ;
    ANTENNAGATEAREA 0.647700 ;
    ANTENNADIFFAREA 0.434700 ;
    PORT
      LAYER met3 ;
        RECT 1396.000 962.240 1400.000 962.840 ;
    END
  END hart_id_i[18]
  PIN hart_id_i[19]
    DIRECTION INPUT ;
    USE SIGNAL ;
    ANTENNAGATEAREA 0.560700 ;
    ANTENNADIFFAREA 0.434700 ;
    PORT
      LAYER met3 ;
        RECT 1396.000 822.840 1400.000 823.440 ;
    END
  END hart_id_i[19]
  PIN hart_id_i[1]
    DIRECTION INPUT ;
    USE SIGNAL ;
    ANTENNAGATEAREA 0.647700 ;
    ANTENNADIFFAREA 0.434700 ;
    PORT
      LAYER met3 ;
        RECT 1396.000 612.040 1400.000 612.640 ;
    END
  END hart_id_i[1]
  PIN hart_id_i[20]
    DIRECTION INPUT ;
    USE SIGNAL ;
    ANTENNAGATEAREA 0.631200 ;
    ANTENNADIFFAREA 0.434700 ;
    PORT
      LAYER met3 ;
        RECT 1396.000 843.240 1400.000 843.840 ;
    END
  END hart_id_i[20]
  PIN hart_id_i[21]
    DIRECTION INPUT ;
    USE SIGNAL ;
    ANTENNAGATEAREA 0.647700 ;
    ANTENNADIFFAREA 0.434700 ;
    PORT
      LAYER met3 ;
        RECT 1396.000 1305.640 1400.000 1306.240 ;
    END
  END hart_id_i[21]
  PIN hart_id_i[22]
    DIRECTION INPUT ;
    USE SIGNAL ;
    ANTENNAGATEAREA 0.647700 ;
    ANTENNADIFFAREA 0.434700 ;
    PORT
      LAYER met3 ;
        RECT 1396.000 1292.040 1400.000 1292.640 ;
    END
  END hart_id_i[22]
  PIN hart_id_i[23]
    DIRECTION INPUT ;
    USE SIGNAL ;
    ANTENNAGATEAREA 0.593700 ;
    ANTENNADIFFAREA 0.434700 ;
    PORT
      LAYER met3 ;
        RECT 1396.000 1074.440 1400.000 1075.040 ;
    END
  END hart_id_i[23]
  PIN hart_id_i[24]
    DIRECTION INPUT ;
    USE SIGNAL ;
    ANTENNAGATEAREA 0.560700 ;
    ANTENNADIFFAREA 0.434700 ;
    PORT
      LAYER met3 ;
        RECT 1396.000 788.840 1400.000 789.440 ;
    END
  END hart_id_i[24]
  PIN hart_id_i[25]
    DIRECTION INPUT ;
    USE SIGNAL ;
    ANTENNAGATEAREA 0.647700 ;
    ANTENNADIFFAREA 0.434700 ;
    PORT
      LAYER met3 ;
        RECT 1396.000 829.640 1400.000 830.240 ;
    END
  END hart_id_i[25]
  PIN hart_id_i[26]
    DIRECTION INPUT ;
    USE SIGNAL ;
    ANTENNAGATEAREA 0.647700 ;
    ANTENNADIFFAREA 0.434700 ;
    PORT
      LAYER met3 ;
        RECT 1396.000 751.440 1400.000 752.040 ;
    END
  END hart_id_i[26]
  PIN hart_id_i[27]
    DIRECTION INPUT ;
    USE SIGNAL ;
    ANTENNAGATEAREA 0.647700 ;
    ANTENNADIFFAREA 0.434700 ;
    PORT
      LAYER met3 ;
        RECT 1396.000 805.840 1400.000 806.440 ;
    END
  END hart_id_i[27]
  PIN hart_id_i[28]
    DIRECTION INPUT ;
    USE SIGNAL ;
    ANTENNAGATEAREA 0.647700 ;
    ANTENNADIFFAREA 0.434700 ;
    PORT
      LAYER met3 ;
        RECT 1396.000 741.240 1400.000 741.840 ;
    END
  END hart_id_i[28]
  PIN hart_id_i[29]
    DIRECTION INPUT ;
    USE SIGNAL ;
    ANTENNAGATEAREA 0.647700 ;
    ANTENNADIFFAREA 0.434700 ;
    PORT
      LAYER met3 ;
        RECT 1396.000 710.640 1400.000 711.240 ;
    END
  END hart_id_i[29]
  PIN hart_id_i[2]
    DIRECTION INPUT ;
    USE SIGNAL ;
    ANTENNAGATEAREA 0.560700 ;
    ANTENNADIFFAREA 0.434700 ;
    PORT
      LAYER met3 ;
        RECT 1396.000 578.040 1400.000 578.640 ;
    END
  END hart_id_i[2]
  PIN hart_id_i[30]
    DIRECTION INPUT ;
    USE SIGNAL ;
    ANTENNAGATEAREA 0.647700 ;
    ANTENNADIFFAREA 0.434700 ;
    PORT
      LAYER met3 ;
        RECT 1396.000 816.040 1400.000 816.640 ;
    END
  END hart_id_i[30]
  PIN hart_id_i[31]
    DIRECTION INPUT ;
    USE SIGNAL ;
    ANTENNAGATEAREA 0.647700 ;
    ANTENNADIFFAREA 0.434700 ;
    PORT
      LAYER met3 ;
        RECT 1396.000 1013.240 1400.000 1013.840 ;
    END
  END hart_id_i[31]
  PIN hart_id_i[3]
    DIRECTION INPUT ;
    USE SIGNAL ;
    ANTENNAGATEAREA 0.631200 ;
    ANTENNADIFFAREA 0.434700 ;
    PORT
      LAYER met3 ;
        RECT 1396.000 588.240 1400.000 588.840 ;
    END
  END hart_id_i[3]
  PIN hart_id_i[4]
    DIRECTION INPUT ;
    USE SIGNAL ;
    ANTENNAGATEAREA 0.631200 ;
    ANTENNADIFFAREA 0.434700 ;
    PORT
      LAYER met3 ;
        RECT 1396.000 581.440 1400.000 582.040 ;
    END
  END hart_id_i[4]
  PIN hart_id_i[5]
    DIRECTION INPUT ;
    USE SIGNAL ;
    ANTENNAGATEAREA 0.631200 ;
    ANTENNADIFFAREA 0.434700 ;
    PORT
      LAYER met3 ;
        RECT 1396.000 584.840 1400.000 585.440 ;
    END
  END hart_id_i[5]
  PIN hart_id_i[6]
    DIRECTION INPUT ;
    USE SIGNAL ;
    ANTENNAGATEAREA 0.560700 ;
    ANTENNADIFFAREA 0.434700 ;
    PORT
      LAYER met3 ;
        RECT 1396.000 601.840 1400.000 602.440 ;
    END
  END hart_id_i[6]
  PIN hart_id_i[7]
    DIRECTION INPUT ;
    USE SIGNAL ;
    ANTENNAGATEAREA 0.647700 ;
    ANTENNADIFFAREA 0.434700 ;
    PORT
      LAYER met3 ;
        RECT 1396.000 605.240 1400.000 605.840 ;
    END
  END hart_id_i[7]
  PIN hart_id_i[8]
    DIRECTION INPUT ;
    USE SIGNAL ;
    ANTENNAGATEAREA 0.631200 ;
    ANTENNADIFFAREA 0.434700 ;
    PORT
      LAYER met3 ;
        RECT 1396.000 646.040 1400.000 646.640 ;
    END
  END hart_id_i[8]
  PIN hart_id_i[9]
    DIRECTION INPUT ;
    USE SIGNAL ;
    ANTENNAGATEAREA 0.631200 ;
    ANTENNADIFFAREA 0.434700 ;
    PORT
      LAYER met3 ;
        RECT 1396.000 656.240 1400.000 656.840 ;
    END
  END hart_id_i[9]
  PIN instr_addr_o[0]
    DIRECTION OUTPUT ;
    USE SIGNAL ;
    PORT
      LAYER met2 ;
        RECT 99.910 1396.000 100.190 1400.000 ;
    END
  END instr_addr_o[0]
  PIN instr_addr_o[10]
    DIRECTION OUTPUT ;
    USE SIGNAL ;
    ANTENNADIFFAREA 0.445500 ;
    PORT
      LAYER met3 ;
        RECT 1396.000 1156.040 1400.000 1156.640 ;
    END
  END instr_addr_o[10]
  PIN instr_addr_o[11]
    DIRECTION OUTPUT ;
    USE SIGNAL ;
    ANTENNADIFFAREA 0.445500 ;
    PORT
      LAYER met3 ;
        RECT 1396.000 1237.640 1400.000 1238.240 ;
    END
  END instr_addr_o[11]
  PIN instr_addr_o[12]
    DIRECTION OUTPUT ;
    USE SIGNAL ;
    ANTENNADIFFAREA 0.445500 ;
    PORT
      LAYER met3 ;
        RECT 1396.000 1111.840 1400.000 1112.440 ;
    END
  END instr_addr_o[12]
  PIN instr_addr_o[13]
    DIRECTION OUTPUT ;
    USE SIGNAL ;
    ANTENNADIFFAREA 0.445500 ;
    PORT
      LAYER met3 ;
        RECT 1396.000 1224.040 1400.000 1224.640 ;
    END
  END instr_addr_o[13]
  PIN instr_addr_o[14]
    DIRECTION OUTPUT ;
    USE SIGNAL ;
    ANTENNADIFFAREA 0.445500 ;
    PORT
      LAYER met3 ;
        RECT 1396.000 1159.440 1400.000 1160.040 ;
    END
  END instr_addr_o[14]
  PIN instr_addr_o[15]
    DIRECTION OUTPUT ;
    USE SIGNAL ;
    ANTENNADIFFAREA 0.445500 ;
    PORT
      LAYER met2 ;
        RECT 1033.710 1396.000 1033.990 1400.000 ;
    END
  END instr_addr_o[15]
  PIN instr_addr_o[16]
    DIRECTION OUTPUT ;
    USE SIGNAL ;
    ANTENNADIFFAREA 0.445500 ;
    PORT
      LAYER met2 ;
        RECT 1040.150 1396.000 1040.430 1400.000 ;
    END
  END instr_addr_o[16]
  PIN instr_addr_o[17]
    DIRECTION OUTPUT ;
    USE SIGNAL ;
    ANTENNADIFFAREA 0.445500 ;
    PORT
      LAYER met2 ;
        RECT 1053.030 1396.000 1053.310 1400.000 ;
    END
  END instr_addr_o[17]
  PIN instr_addr_o[18]
    DIRECTION OUTPUT ;
    USE SIGNAL ;
    ANTENNADIFFAREA 0.445500 ;
    PORT
      LAYER met2 ;
        RECT 1056.250 1396.000 1056.530 1400.000 ;
    END
  END instr_addr_o[18]
  PIN instr_addr_o[19]
    DIRECTION OUTPUT ;
    USE SIGNAL ;
    ANTENNADIFFAREA 0.445500 ;
    PORT
      LAYER met2 ;
        RECT 1065.910 1396.000 1066.190 1400.000 ;
    END
  END instr_addr_o[19]
  PIN instr_addr_o[1]
    DIRECTION OUTPUT ;
    USE SIGNAL ;
    PORT
      LAYER met2 ;
        RECT 209.390 0.000 209.670 4.000 ;
    END
  END instr_addr_o[1]
  PIN instr_addr_o[20]
    DIRECTION OUTPUT ;
    USE SIGNAL ;
    ANTENNADIFFAREA 0.445500 ;
    PORT
      LAYER met2 ;
        RECT 1075.570 1396.000 1075.850 1400.000 ;
    END
  END instr_addr_o[20]
  PIN instr_addr_o[21]
    DIRECTION OUTPUT ;
    USE SIGNAL ;
    ANTENNADIFFAREA 0.445500 ;
    PORT
      LAYER met2 ;
        RECT 1072.350 1396.000 1072.630 1400.000 ;
    END
  END instr_addr_o[21]
  PIN instr_addr_o[22]
    DIRECTION OUTPUT ;
    USE SIGNAL ;
    ANTENNADIFFAREA 0.445500 ;
    PORT
      LAYER met2 ;
        RECT 1130.310 1396.000 1130.590 1400.000 ;
    END
  END instr_addr_o[22]
  PIN instr_addr_o[23]
    DIRECTION OUTPUT ;
    USE SIGNAL ;
    ANTENNADIFFAREA 0.795200 ;
    PORT
      LAYER met2 ;
        RECT 1149.630 1396.000 1149.910 1400.000 ;
    END
  END instr_addr_o[23]
  PIN instr_addr_o[24]
    DIRECTION OUTPUT ;
    USE SIGNAL ;
    ANTENNADIFFAREA 0.445500 ;
    PORT
      LAYER met2 ;
        RECT 1146.410 1396.000 1146.690 1400.000 ;
    END
  END instr_addr_o[24]
  PIN instr_addr_o[25]
    DIRECTION OUTPUT ;
    USE SIGNAL ;
    ANTENNADIFFAREA 0.445500 ;
    PORT
      LAYER met2 ;
        RECT 1156.070 1396.000 1156.350 1400.000 ;
    END
  END instr_addr_o[25]
  PIN instr_addr_o[26]
    DIRECTION OUTPUT ;
    USE SIGNAL ;
    ANTENNADIFFAREA 0.445500 ;
    PORT
      LAYER met2 ;
        RECT 1152.850 1396.000 1153.130 1400.000 ;
    END
  END instr_addr_o[26]
  PIN instr_addr_o[27]
    DIRECTION OUTPUT ;
    USE SIGNAL ;
    ANTENNADIFFAREA 0.445500 ;
    PORT
      LAYER met2 ;
        RECT 1114.210 1396.000 1114.490 1400.000 ;
    END
  END instr_addr_o[27]
  PIN instr_addr_o[28]
    DIRECTION OUTPUT ;
    USE SIGNAL ;
    ANTENNADIFFAREA 0.445500 ;
    PORT
      LAYER met2 ;
        RECT 1098.110 1396.000 1098.390 1400.000 ;
    END
  END instr_addr_o[28]
  PIN instr_addr_o[29]
    DIRECTION OUTPUT ;
    USE SIGNAL ;
    ANTENNADIFFAREA 0.445500 ;
    PORT
      LAYER met2 ;
        RECT 1117.430 1396.000 1117.710 1400.000 ;
    END
  END instr_addr_o[29]
  PIN instr_addr_o[2]
    DIRECTION OUTPUT ;
    USE SIGNAL ;
    ANTENNADIFFAREA 0.445500 ;
    PORT
      LAYER met2 ;
        RECT 959.650 1396.000 959.930 1400.000 ;
    END
  END instr_addr_o[2]
  PIN instr_addr_o[30]
    DIRECTION OUTPUT ;
    USE SIGNAL ;
    ANTENNADIFFAREA 0.445500 ;
    PORT
      LAYER met2 ;
        RECT 1104.550 1396.000 1104.830 1400.000 ;
    END
  END instr_addr_o[30]
  PIN instr_addr_o[31]
    DIRECTION OUTPUT ;
    USE SIGNAL ;
    ANTENNADIFFAREA 0.445500 ;
    PORT
      LAYER met2 ;
        RECT 1085.230 1396.000 1085.510 1400.000 ;
    END
  END instr_addr_o[31]
  PIN instr_addr_o[3]
    DIRECTION OUTPUT ;
    USE SIGNAL ;
    ANTENNADIFFAREA 0.445500 ;
    PORT
      LAYER met2 ;
        RECT 966.090 1396.000 966.370 1400.000 ;
    END
  END instr_addr_o[3]
  PIN instr_addr_o[4]
    DIRECTION OUTPUT ;
    USE SIGNAL ;
    ANTENNADIFFAREA 0.445500 ;
    PORT
      LAYER met2 ;
        RECT 962.870 1396.000 963.150 1400.000 ;
    END
  END instr_addr_o[4]
  PIN instr_addr_o[5]
    DIRECTION OUTPUT ;
    USE SIGNAL ;
    ANTENNADIFFAREA 0.445500 ;
    PORT
      LAYER met2 ;
        RECT 969.310 1396.000 969.590 1400.000 ;
    END
  END instr_addr_o[5]
  PIN instr_addr_o[6]
    DIRECTION OUTPUT ;
    USE SIGNAL ;
    ANTENNADIFFAREA 0.445500 ;
    PORT
      LAYER met2 ;
        RECT 972.530 1396.000 972.810 1400.000 ;
    END
  END instr_addr_o[6]
  PIN instr_addr_o[7]
    DIRECTION OUTPUT ;
    USE SIGNAL ;
    ANTENNADIFFAREA 0.445500 ;
    PORT
      LAYER met2 ;
        RECT 978.970 1396.000 979.250 1400.000 ;
    END
  END instr_addr_o[7]
  PIN instr_addr_o[8]
    DIRECTION OUTPUT ;
    USE SIGNAL ;
    ANTENNADIFFAREA 0.445500 ;
    PORT
      LAYER met2 ;
        RECT 988.630 1396.000 988.910 1400.000 ;
    END
  END instr_addr_o[8]
  PIN instr_addr_o[9]
    DIRECTION OUTPUT ;
    USE SIGNAL ;
    ANTENNADIFFAREA 0.445500 ;
    PORT
      LAYER met2 ;
        RECT 998.290 1396.000 998.570 1400.000 ;
    END
  END instr_addr_o[9]
  PIN instr_addr_shadow_o[0]
    DIRECTION OUTPUT ;
    USE SIGNAL ;
    PORT
      LAYER met2 ;
        RECT 103.130 1396.000 103.410 1400.000 ;
    END
  END instr_addr_shadow_o[0]
  PIN instr_addr_shadow_o[10]
    DIRECTION OUTPUT ;
    USE SIGNAL ;
    PORT
      LAYER met2 ;
        RECT 454.110 0.000 454.390 4.000 ;
    END
  END instr_addr_shadow_o[10]
  PIN instr_addr_shadow_o[11]
    DIRECTION OUTPUT ;
    USE SIGNAL ;
    PORT
      LAYER met3 ;
        RECT 1396.000 1383.840 1400.000 1384.440 ;
    END
  END instr_addr_shadow_o[11]
  PIN instr_addr_shadow_o[12]
    DIRECTION OUTPUT ;
    USE SIGNAL ;
    PORT
      LAYER met2 ;
        RECT 917.790 1396.000 918.070 1400.000 ;
    END
  END instr_addr_shadow_o[12]
  PIN instr_addr_shadow_o[13]
    DIRECTION OUTPUT ;
    USE SIGNAL ;
    PORT
      LAYER met3 ;
        RECT 1396.000 1380.440 1400.000 1381.040 ;
    END
  END instr_addr_shadow_o[13]
  PIN instr_addr_shadow_o[14]
    DIRECTION OUTPUT ;
    USE SIGNAL ;
    PORT
      LAYER met3 ;
        RECT 1396.000 1370.240 1400.000 1370.840 ;
    END
  END instr_addr_shadow_o[14]
  PIN instr_addr_shadow_o[15]
    DIRECTION OUTPUT ;
    USE SIGNAL ;
    PORT
      LAYER met2 ;
        RECT 1294.530 0.000 1294.810 4.000 ;
    END
  END instr_addr_shadow_o[15]
  PIN instr_addr_shadow_o[16]
    DIRECTION OUTPUT ;
    USE SIGNAL ;
    PORT
      LAYER met2 ;
        RECT 1288.090 0.000 1288.370 4.000 ;
    END
  END instr_addr_shadow_o[16]
  PIN instr_addr_shadow_o[17]
    DIRECTION OUTPUT ;
    USE SIGNAL ;
    PORT
      LAYER met2 ;
        RECT 750.350 0.000 750.630 4.000 ;
    END
  END instr_addr_shadow_o[17]
  PIN instr_addr_shadow_o[18]
    DIRECTION OUTPUT ;
    USE SIGNAL ;
    PORT
      LAYER met3 ;
        RECT 0.000 340.040 4.000 340.640 ;
    END
  END instr_addr_shadow_o[18]
  PIN instr_addr_shadow_o[19]
    DIRECTION OUTPUT ;
    USE SIGNAL ;
    PORT
      LAYER met2 ;
        RECT 109.570 1396.000 109.850 1400.000 ;
    END
  END instr_addr_shadow_o[19]
  PIN instr_addr_shadow_o[1]
    DIRECTION OUTPUT ;
    USE SIGNAL ;
    PORT
      LAYER met3 ;
        RECT 0.000 421.640 4.000 422.240 ;
    END
  END instr_addr_shadow_o[1]
  PIN instr_addr_shadow_o[20]
    DIRECTION OUTPUT ;
    USE SIGNAL ;
    PORT
      LAYER met2 ;
        RECT 547.490 1396.000 547.770 1400.000 ;
    END
  END instr_addr_shadow_o[20]
  PIN instr_addr_shadow_o[21]
    DIRECTION OUTPUT ;
    USE SIGNAL ;
    PORT
      LAYER met3 ;
        RECT 1396.000 1397.440 1400.000 1398.040 ;
    END
  END instr_addr_shadow_o[21]
  PIN instr_addr_shadow_o[22]
    DIRECTION OUTPUT ;
    USE SIGNAL ;
    PORT
      LAYER met2 ;
        RECT 566.810 0.000 567.090 4.000 ;
    END
  END instr_addr_shadow_o[22]
  PIN instr_addr_shadow_o[23]
    DIRECTION OUTPUT ;
    USE SIGNAL ;
    PORT
      LAYER met3 ;
        RECT 1396.000 1360.040 1400.000 1360.640 ;
    END
  END instr_addr_shadow_o[23]
  PIN instr_addr_shadow_o[24]
    DIRECTION OUTPUT ;
    USE SIGNAL ;
    PORT
      LAYER met2 ;
        RECT 592.570 0.000 592.850 4.000 ;
    END
  END instr_addr_shadow_o[24]
  PIN instr_addr_shadow_o[25]
    DIRECTION OUTPUT ;
    USE SIGNAL ;
    PORT
      LAYER met2 ;
        RECT 750.350 1396.000 750.630 1400.000 ;
    END
  END instr_addr_shadow_o[25]
  PIN instr_addr_shadow_o[26]
    DIRECTION OUTPUT ;
    USE SIGNAL ;
    PORT
      LAYER met3 ;
        RECT 1396.000 673.240 1400.000 673.840 ;
    END
  END instr_addr_shadow_o[26]
  PIN instr_addr_shadow_o[27]
    DIRECTION OUTPUT ;
    USE SIGNAL ;
    PORT
      LAYER met3 ;
        RECT 1396.000 336.640 1400.000 337.240 ;
    END
  END instr_addr_shadow_o[27]
  PIN instr_addr_shadow_o[28]
    DIRECTION OUTPUT ;
    USE SIGNAL ;
    PORT
      LAYER met2 ;
        RECT 618.330 1396.000 618.610 1400.000 ;
    END
  END instr_addr_shadow_o[28]
  PIN instr_addr_shadow_o[29]
    DIRECTION OUTPUT ;
    USE SIGNAL ;
    PORT
      LAYER met3 ;
        RECT 1396.000 210.840 1400.000 211.440 ;
    END
  END instr_addr_shadow_o[29]
  PIN instr_addr_shadow_o[2]
    DIRECTION OUTPUT ;
    USE SIGNAL ;
    PORT
      LAYER met2 ;
        RECT 702.050 0.000 702.330 4.000 ;
    END
  END instr_addr_shadow_o[2]
  PIN instr_addr_shadow_o[30]
    DIRECTION OUTPUT ;
    USE SIGNAL ;
    PORT
      LAYER met2 ;
        RECT 1091.670 1396.000 1091.950 1400.000 ;
    END
  END instr_addr_shadow_o[30]
  PIN instr_addr_shadow_o[31]
    DIRECTION OUTPUT ;
    USE SIGNAL ;
    PORT
      LAYER met3 ;
        RECT 0.000 1186.640 4.000 1187.240 ;
    END
  END instr_addr_shadow_o[31]
  PIN instr_addr_shadow_o[3]
    DIRECTION OUTPUT ;
    USE SIGNAL ;
    PORT
      LAYER met3 ;
        RECT 1396.000 1366.840 1400.000 1367.440 ;
    END
  END instr_addr_shadow_o[3]
  PIN instr_addr_shadow_o[4]
    DIRECTION OUTPUT ;
    USE SIGNAL ;
    PORT
      LAYER met2 ;
        RECT 1082.010 1396.000 1082.290 1400.000 ;
    END
  END instr_addr_shadow_o[4]
  PIN instr_addr_shadow_o[5]
    DIRECTION OUTPUT ;
    USE SIGNAL ;
    PORT
      LAYER met2 ;
        RECT 1300.970 0.000 1301.250 4.000 ;
    END
  END instr_addr_shadow_o[5]
  PIN instr_addr_shadow_o[6]
    DIRECTION OUTPUT ;
    USE SIGNAL ;
    PORT
      LAYER met2 ;
        RECT 846.950 0.000 847.230 4.000 ;
    END
  END instr_addr_shadow_o[6]
  PIN instr_addr_shadow_o[7]
    DIRECTION OUTPUT ;
    USE SIGNAL ;
    PORT
      LAYER met3 ;
        RECT 0.000 231.240 4.000 231.840 ;
    END
  END instr_addr_shadow_o[7]
  PIN instr_addr_shadow_o[8]
    DIRECTION OUTPUT ;
    USE SIGNAL ;
    PORT
      LAYER met3 ;
        RECT 0.000 574.640 4.000 575.240 ;
    END
  END instr_addr_shadow_o[8]
  PIN instr_addr_shadow_o[9]
    DIRECTION OUTPUT ;
    USE SIGNAL ;
    PORT
      LAYER met2 ;
        RECT 724.590 1396.000 724.870 1400.000 ;
    END
  END instr_addr_shadow_o[9]
  PIN instr_err_i
    DIRECTION INPUT ;
    USE SIGNAL ;
    ANTENNAGATEAREA 0.682200 ;
    ANTENNADIFFAREA 0.434700 ;
    PORT
      LAYER met2 ;
        RECT 1007.950 0.000 1008.230 4.000 ;
    END
  END instr_err_i
  PIN instr_gnt_i
    DIRECTION INPUT ;
    USE SIGNAL ;
    ANTENNAGATEAREA 1.177200 ;
    ANTENNADIFFAREA 0.434700 ;
    PORT
      LAYER met2 ;
        RECT 1024.050 1396.000 1024.330 1400.000 ;
    END
  END instr_gnt_i
  PIN instr_rdata_i[0]
    DIRECTION INPUT ;
    USE SIGNAL ;
    ANTENNAGATEAREA 0.647700 ;
    ANTENNADIFFAREA 0.434700 ;
    PORT
      LAYER met3 ;
        RECT 1396.000 448.840 1400.000 449.440 ;
    END
  END instr_rdata_i[0]
  PIN instr_rdata_i[10]
    DIRECTION INPUT ;
    USE SIGNAL ;
    ANTENNAGATEAREA 0.647700 ;
    ANTENNADIFFAREA 0.434700 ;
    PORT
      LAYER met2 ;
        RECT 985.410 0.000 985.690 4.000 ;
    END
  END instr_rdata_i[10]
  PIN instr_rdata_i[11]
    DIRECTION INPUT ;
    USE SIGNAL ;
    ANTENNAGATEAREA 0.647700 ;
    ANTENNADIFFAREA 0.434700 ;
    PORT
      LAYER met2 ;
        RECT 991.850 0.000 992.130 4.000 ;
    END
  END instr_rdata_i[11]
  PIN instr_rdata_i[12]
    DIRECTION INPUT ;
    USE SIGNAL ;
    ANTENNAGATEAREA 0.647700 ;
    ANTENNADIFFAREA 0.434700 ;
    PORT
      LAYER met3 ;
        RECT 1396.000 387.640 1400.000 388.240 ;
    END
  END instr_rdata_i[12]
  PIN instr_rdata_i[13]
    DIRECTION INPUT ;
    USE SIGNAL ;
    ANTENNAGATEAREA 0.647700 ;
    ANTENNADIFFAREA 0.434700 ;
    PORT
      LAYER met3 ;
        RECT 1396.000 408.040 1400.000 408.640 ;
    END
  END instr_rdata_i[13]
  PIN instr_rdata_i[14]
    DIRECTION INPUT ;
    USE SIGNAL ;
    ANTENNAGATEAREA 0.647700 ;
    ANTENNADIFFAREA 0.434700 ;
    PORT
      LAYER met3 ;
        RECT 1396.000 418.240 1400.000 418.840 ;
    END
  END instr_rdata_i[14]
  PIN instr_rdata_i[15]
    DIRECTION INPUT ;
    USE SIGNAL ;
    ANTENNAGATEAREA 0.647700 ;
    ANTENNADIFFAREA 0.434700 ;
    PORT
      LAYER met3 ;
        RECT 1396.000 421.640 1400.000 422.240 ;
    END
  END instr_rdata_i[15]
  PIN instr_rdata_i[16]
    DIRECTION INPUT ;
    USE SIGNAL ;
    ANTENNAGATEAREA 0.647700 ;
    ANTENNADIFFAREA 0.434700 ;
    PORT
      LAYER met3 ;
        RECT 1396.000 438.640 1400.000 439.240 ;
    END
  END instr_rdata_i[16]
  PIN instr_rdata_i[17]
    DIRECTION INPUT ;
    USE SIGNAL ;
    ANTENNAGATEAREA 0.647700 ;
    ANTENNADIFFAREA 0.434700 ;
    PORT
      LAYER met3 ;
        RECT 1396.000 442.040 1400.000 442.640 ;
    END
  END instr_rdata_i[17]
  PIN instr_rdata_i[18]
    DIRECTION INPUT ;
    USE SIGNAL ;
    ANTENNAGATEAREA 0.647700 ;
    ANTENNADIFFAREA 0.434700 ;
    PORT
      LAYER met3 ;
        RECT 1396.000 384.240 1400.000 384.840 ;
    END
  END instr_rdata_i[18]
  PIN instr_rdata_i[19]
    DIRECTION INPUT ;
    USE SIGNAL ;
    ANTENNAGATEAREA 0.647700 ;
    ANTENNADIFFAREA 0.434700 ;
    PORT
      LAYER met3 ;
        RECT 1396.000 323.040 1400.000 323.640 ;
    END
  END instr_rdata_i[19]
  PIN instr_rdata_i[1]
    DIRECTION INPUT ;
    USE SIGNAL ;
    ANTENNAGATEAREA 0.593700 ;
    ANTENNADIFFAREA 0.434700 ;
    PORT
      LAYER met2 ;
        RECT 1017.610 0.000 1017.890 4.000 ;
    END
  END instr_rdata_i[1]
  PIN instr_rdata_i[20]
    DIRECTION INPUT ;
    USE SIGNAL ;
    ANTENNAGATEAREA 0.647700 ;
    ANTENNADIFFAREA 0.434700 ;
    PORT
      LAYER met3 ;
        RECT 1396.000 363.840 1400.000 364.440 ;
    END
  END instr_rdata_i[20]
  PIN instr_rdata_i[21]
    DIRECTION INPUT ;
    USE SIGNAL ;
    ANTENNAGATEAREA 0.647700 ;
    ANTENNADIFFAREA 0.434700 ;
    PORT
      LAYER met3 ;
        RECT 1396.000 299.240 1400.000 299.840 ;
    END
  END instr_rdata_i[21]
  PIN instr_rdata_i[22]
    DIRECTION INPUT ;
    USE SIGNAL ;
    ANTENNAGATEAREA 0.647700 ;
    ANTENNADIFFAREA 0.434700 ;
    PORT
      LAYER met3 ;
        RECT 1396.000 319.640 1400.000 320.240 ;
    END
  END instr_rdata_i[22]
  PIN instr_rdata_i[23]
    DIRECTION INPUT ;
    USE SIGNAL ;
    ANTENNAGATEAREA 0.593700 ;
    ANTENNADIFFAREA 0.434700 ;
    PORT
      LAYER met2 ;
        RECT 966.090 0.000 966.370 4.000 ;
    END
  END instr_rdata_i[23]
  PIN instr_rdata_i[24]
    DIRECTION INPUT ;
    USE SIGNAL ;
    ANTENNAGATEAREA 0.593700 ;
    ANTENNADIFFAREA 0.434700 ;
    PORT
      LAYER met2 ;
        RECT 1020.830 0.000 1021.110 4.000 ;
    END
  END instr_rdata_i[24]
  PIN instr_rdata_i[25]
    DIRECTION INPUT ;
    USE SIGNAL ;
    ANTENNAGATEAREA 0.647700 ;
    ANTENNADIFFAREA 0.434700 ;
    PORT
      LAYER met3 ;
        RECT 1396.000 346.840 1400.000 347.440 ;
    END
  END instr_rdata_i[25]
  PIN instr_rdata_i[26]
    DIRECTION INPUT ;
    USE SIGNAL ;
    ANTENNAGATEAREA 0.593700 ;
    ANTENNADIFFAREA 0.434700 ;
    PORT
      LAYER met2 ;
        RECT 1014.390 0.000 1014.670 4.000 ;
    END
  END instr_rdata_i[26]
  PIN instr_rdata_i[27]
    DIRECTION INPUT ;
    USE SIGNAL ;
    ANTENNAGATEAREA 0.647700 ;
    ANTENNADIFFAREA 0.434700 ;
    PORT
      LAYER met3 ;
        RECT 1396.000 360.440 1400.000 361.040 ;
    END
  END instr_rdata_i[27]
  PIN instr_rdata_i[28]
    DIRECTION INPUT ;
    USE SIGNAL ;
    ANTENNAGATEAREA 0.647700 ;
    ANTENNADIFFAREA 0.434700 ;
    PORT
      LAYER met3 ;
        RECT 1396.000 380.840 1400.000 381.440 ;
    END
  END instr_rdata_i[28]
  PIN instr_rdata_i[29]
    DIRECTION INPUT ;
    USE SIGNAL ;
    ANTENNAGATEAREA 0.647700 ;
    ANTENNADIFFAREA 0.434700 ;
    PORT
      LAYER met3 ;
        RECT 1396.000 404.640 1400.000 405.240 ;
    END
  END instr_rdata_i[29]
  PIN instr_rdata_i[2]
    DIRECTION INPUT ;
    USE SIGNAL ;
    ANTENNAGATEAREA 0.647700 ;
    ANTENNADIFFAREA 0.434700 ;
    PORT
      LAYER met2 ;
        RECT 1001.510 0.000 1001.790 4.000 ;
    END
  END instr_rdata_i[2]
  PIN instr_rdata_i[30]
    DIRECTION INPUT ;
    USE SIGNAL ;
    ANTENNAGATEAREA 0.647700 ;
    ANTENNADIFFAREA 0.434700 ;
    PORT
      LAYER met3 ;
        RECT 1396.000 411.440 1400.000 412.040 ;
    END
  END instr_rdata_i[30]
  PIN instr_rdata_i[31]
    DIRECTION INPUT ;
    USE SIGNAL ;
    ANTENNAGATEAREA 0.647700 ;
    ANTENNADIFFAREA 0.434700 ;
    PORT
      LAYER met3 ;
        RECT 1396.000 425.040 1400.000 425.640 ;
    END
  END instr_rdata_i[31]
  PIN instr_rdata_i[3]
    DIRECTION INPUT ;
    USE SIGNAL ;
    ANTENNAGATEAREA 0.647700 ;
    ANTENNADIFFAREA 0.434700 ;
    PORT
      LAYER met3 ;
        RECT 1396.000 340.040 1400.000 340.640 ;
    END
  END instr_rdata_i[3]
  PIN instr_rdata_i[4]
    DIRECTION INPUT ;
    USE SIGNAL ;
    ANTENNAGATEAREA 0.647700 ;
    ANTENNADIFFAREA 0.434700 ;
    PORT
      LAYER met2 ;
        RECT 1011.170 0.000 1011.450 4.000 ;
    END
  END instr_rdata_i[4]
  PIN instr_rdata_i[5]
    DIRECTION INPUT ;
    USE SIGNAL ;
    ANTENNAGATEAREA 0.647700 ;
    ANTENNADIFFAREA 0.434700 ;
    PORT
      LAYER met2 ;
        RECT 982.190 0.000 982.470 4.000 ;
    END
  END instr_rdata_i[5]
  PIN instr_rdata_i[6]
    DIRECTION INPUT ;
    USE SIGNAL ;
    ANTENNAGATEAREA 0.647700 ;
    ANTENNADIFFAREA 0.434700 ;
    PORT
      LAYER met2 ;
        RECT 995.070 0.000 995.350 4.000 ;
    END
  END instr_rdata_i[6]
  PIN instr_rdata_i[7]
    DIRECTION INPUT ;
    USE SIGNAL ;
    ANTENNAGATEAREA 0.593700 ;
    ANTENNADIFFAREA 0.434700 ;
    PORT
      LAYER met2 ;
        RECT 978.970 0.000 979.250 4.000 ;
    END
  END instr_rdata_i[7]
  PIN instr_rdata_i[8]
    DIRECTION INPUT ;
    USE SIGNAL ;
    ANTENNAGATEAREA 0.593700 ;
    ANTENNADIFFAREA 0.434700 ;
    PORT
      LAYER met2 ;
        RECT 1040.150 0.000 1040.430 4.000 ;
    END
  END instr_rdata_i[8]
  PIN instr_rdata_i[9]
    DIRECTION INPUT ;
    USE SIGNAL ;
    ANTENNAGATEAREA 0.647700 ;
    ANTENNADIFFAREA 0.434700 ;
    PORT
      LAYER met3 ;
        RECT 1396.000 357.040 1400.000 357.640 ;
    END
  END instr_rdata_i[9]
  PIN instr_rdata_intg_i[0]
    DIRECTION INPUT ;
    USE SIGNAL ;
    PORT
      LAYER met2 ;
        RECT 80.590 0.000 80.870 4.000 ;
    END
  END instr_rdata_intg_i[0]
  PIN instr_rdata_intg_i[1]
    DIRECTION INPUT ;
    USE SIGNAL ;
    PORT
      LAYER met2 ;
        RECT 74.150 0.000 74.430 4.000 ;
    END
  END instr_rdata_intg_i[1]
  PIN instr_rdata_intg_i[2]
    DIRECTION INPUT ;
    USE SIGNAL ;
    PORT
      LAYER met2 ;
        RECT 67.710 0.000 67.990 4.000 ;
    END
  END instr_rdata_intg_i[2]
  PIN instr_rdata_intg_i[3]
    DIRECTION INPUT ;
    USE SIGNAL ;
    PORT
      LAYER met2 ;
        RECT 70.930 0.000 71.210 4.000 ;
    END
  END instr_rdata_intg_i[3]
  PIN instr_rdata_intg_i[4]
    DIRECTION INPUT ;
    USE SIGNAL ;
    PORT
      LAYER met2 ;
        RECT 83.810 0.000 84.090 4.000 ;
    END
  END instr_rdata_intg_i[4]
  PIN instr_rdata_intg_i[5]
    DIRECTION INPUT ;
    USE SIGNAL ;
    PORT
      LAYER met2 ;
        RECT 77.370 0.000 77.650 4.000 ;
    END
  END instr_rdata_intg_i[5]
  PIN instr_rdata_intg_i[6]
    DIRECTION INPUT ;
    USE SIGNAL ;
    PORT
      LAYER met2 ;
        RECT 99.910 0.000 100.190 4.000 ;
    END
  END instr_rdata_intg_i[6]
  PIN instr_req_o
    DIRECTION OUTPUT ;
    USE SIGNAL ;
    ANTENNADIFFAREA 0.445500 ;
    PORT
      LAYER met3 ;
        RECT 1396.000 479.440 1400.000 480.040 ;
    END
  END instr_req_o
  PIN instr_req_shadow_o
    DIRECTION OUTPUT ;
    USE SIGNAL ;
    PORT
      LAYER met2 ;
        RECT 96.690 1396.000 96.970 1400.000 ;
    END
  END instr_req_shadow_o
  PIN instr_rvalid_i
    DIRECTION INPUT ;
    USE SIGNAL ;
    ANTENNAGATEAREA 0.647700 ;
    ANTENNADIFFAREA 0.434700 ;
    PORT
      LAYER met3 ;
        RECT 1396.000 465.840 1400.000 466.440 ;
    END
  END instr_rvalid_i
  PIN irq_external_i
    DIRECTION INPUT ;
    USE SIGNAL ;
    ANTENNAGATEAREA 0.593700 ;
    ANTENNADIFFAREA 0.434700 ;
    PORT
      LAYER met3 ;
        RECT 1396.000 625.640 1400.000 626.240 ;
    END
  END irq_external_i
  PIN irq_fast_i[0]
    DIRECTION INPUT ;
    USE SIGNAL ;
    ANTENNAGATEAREA 0.860700 ;
    ANTENNADIFFAREA 0.434700 ;
    PORT
      LAYER met2 ;
        RECT 1094.890 1396.000 1095.170 1400.000 ;
    END
  END irq_fast_i[0]
  PIN irq_fast_i[10]
    DIRECTION INPUT ;
    USE SIGNAL ;
    ANTENNAGATEAREA 0.647700 ;
    ANTENNADIFFAREA 0.434700 ;
    PORT
      LAYER met3 ;
        RECT 1396.000 676.640 1400.000 677.240 ;
    END
  END irq_fast_i[10]
  PIN irq_fast_i[11]
    DIRECTION INPUT ;
    USE SIGNAL ;
    ANTENNAGATEAREA 0.682200 ;
    ANTENNADIFFAREA 0.434700 ;
    PORT
      LAYER met2 ;
        RECT 1127.090 1396.000 1127.370 1400.000 ;
    END
  END irq_fast_i[11]
  PIN irq_fast_i[12]
    DIRECTION INPUT ;
    USE SIGNAL ;
    ANTENNAGATEAREA 0.647700 ;
    ANTENNADIFFAREA 0.434700 ;
    PORT
      LAYER met3 ;
        RECT 1396.000 659.640 1400.000 660.240 ;
    END
  END irq_fast_i[12]
  PIN irq_fast_i[13]
    DIRECTION INPUT ;
    USE SIGNAL ;
    ANTENNAGATEAREA 0.647700 ;
    ANTENNADIFFAREA 0.434700 ;
    PORT
      LAYER met3 ;
        RECT 1396.000 642.640 1400.000 643.240 ;
    END
  END irq_fast_i[13]
  PIN irq_fast_i[14]
    DIRECTION INPUT ;
    USE SIGNAL ;
    ANTENNAGATEAREA 0.682200 ;
    ANTENNADIFFAREA 0.434700 ;
    PORT
      LAYER met2 ;
        RECT 1120.650 1396.000 1120.930 1400.000 ;
    END
  END irq_fast_i[14]
  PIN irq_fast_i[1]
    DIRECTION INPUT ;
    USE SIGNAL ;
    ANTENNAGATEAREA 0.682200 ;
    ANTENNADIFFAREA 0.434700 ;
    PORT
      LAYER met2 ;
        RECT 1101.330 1396.000 1101.610 1400.000 ;
    END
  END irq_fast_i[1]
  PIN irq_fast_i[2]
    DIRECTION INPUT ;
    USE SIGNAL ;
    ANTENNAGATEAREA 0.682200 ;
    ANTENNADIFFAREA 0.434700 ;
    PORT
      LAYER met2 ;
        RECT 1110.990 1396.000 1111.270 1400.000 ;
    END
  END irq_fast_i[2]
  PIN irq_fast_i[3]
    DIRECTION INPUT ;
    USE SIGNAL ;
    ANTENNAGATEAREA 0.682200 ;
    ANTENNADIFFAREA 0.434700 ;
    PORT
      LAYER met2 ;
        RECT 1165.730 1396.000 1166.010 1400.000 ;
    END
  END irq_fast_i[3]
  PIN irq_fast_i[4]
    DIRECTION INPUT ;
    USE SIGNAL ;
    ANTENNAGATEAREA 0.682200 ;
    ANTENNADIFFAREA 0.434700 ;
    PORT
      LAYER met2 ;
        RECT 1088.450 1396.000 1088.730 1400.000 ;
    END
  END irq_fast_i[4]
  PIN irq_fast_i[5]
    DIRECTION INPUT ;
    USE SIGNAL ;
    ANTENNAGATEAREA 0.682200 ;
    ANTENNADIFFAREA 0.434700 ;
    PORT
      LAYER met2 ;
        RECT 1107.770 1396.000 1108.050 1400.000 ;
    END
  END irq_fast_i[5]
  PIN irq_fast_i[6]
    DIRECTION INPUT ;
    USE SIGNAL ;
    ANTENNAGATEAREA 0.682200 ;
    ANTENNADIFFAREA 0.434700 ;
    PORT
      LAYER met2 ;
        RECT 1133.530 1396.000 1133.810 1400.000 ;
    END
  END irq_fast_i[6]
  PIN irq_fast_i[7]
    DIRECTION INPUT ;
    USE SIGNAL ;
    ANTENNAGATEAREA 0.682200 ;
    ANTENNADIFFAREA 0.434700 ;
    PORT
      LAYER met2 ;
        RECT 1136.750 1396.000 1137.030 1400.000 ;
    END
  END irq_fast_i[7]
  PIN irq_fast_i[8]
    DIRECTION INPUT ;
    USE SIGNAL ;
    ANTENNAGATEAREA 0.647700 ;
    ANTENNADIFFAREA 0.434700 ;
    PORT
      LAYER met3 ;
        RECT 1396.000 635.840 1400.000 636.440 ;
    END
  END irq_fast_i[8]
  PIN irq_fast_i[9]
    DIRECTION INPUT ;
    USE SIGNAL ;
    ANTENNAGATEAREA 0.682200 ;
    ANTENNADIFFAREA 0.434700 ;
    PORT
      LAYER met2 ;
        RECT 1123.870 1396.000 1124.150 1400.000 ;
    END
  END irq_fast_i[9]
  PIN irq_nm_i
    DIRECTION INPUT ;
    USE SIGNAL ;
    ANTENNAGATEAREA 0.647700 ;
    ANTENNADIFFAREA 0.434700 ;
    PORT
      LAYER met3 ;
        RECT 1396.000 571.240 1400.000 571.840 ;
    END
  END irq_nm_i
  PIN irq_software_i
    DIRECTION INPUT ;
    USE SIGNAL ;
    ANTENNAGATEAREA 0.593700 ;
    ANTENNADIFFAREA 0.434700 ;
    PORT
      LAYER met3 ;
        RECT 1396.000 598.440 1400.000 599.040 ;
    END
  END irq_software_i
  PIN irq_timer_i
    DIRECTION INPUT ;
    USE SIGNAL ;
    ANTENNAGATEAREA 0.593700 ;
    ANTENNADIFFAREA 0.434700 ;
    PORT
      LAYER met3 ;
        RECT 1396.000 608.640 1400.000 609.240 ;
    END
  END irq_timer_i
  PIN lockstep_cmp_en_o[0]
    DIRECTION OUTPUT ;
    USE SIGNAL ;
    PORT
      LAYER met3 ;
        RECT 1396.000 666.440 1400.000 667.040 ;
    END
  END lockstep_cmp_en_o[0]
  PIN lockstep_cmp_en_o[1]
    DIRECTION OUTPUT ;
    USE SIGNAL ;
    PORT
      LAYER met3 ;
        RECT 0.000 486.240 4.000 486.840 ;
    END
  END lockstep_cmp_en_o[1]
  PIN lockstep_cmp_en_o[2]
    DIRECTION OUTPUT ;
    USE SIGNAL ;
    PORT
      LAYER met2 ;
        RECT 341.410 1396.000 341.690 1400.000 ;
    END
  END lockstep_cmp_en_o[2]
  PIN lockstep_cmp_en_o[3]
    DIRECTION OUTPUT ;
    USE SIGNAL ;
    PORT
      LAYER met2 ;
        RECT 289.890 0.000 290.170 4.000 ;
    END
  END lockstep_cmp_en_o[3]
  PIN ram_cfg_icache_data_i[0]
    DIRECTION INPUT ;
    USE SIGNAL ;
    PORT
      LAYER met2 ;
        RECT 90.250 0.000 90.530 4.000 ;
    END
  END ram_cfg_icache_data_i[0]
  PIN ram_cfg_icache_data_i[10]
    DIRECTION INPUT ;
    USE SIGNAL ;
    PORT
      LAYER met2 ;
        RECT 87.030 0.000 87.310 4.000 ;
    END
  END ram_cfg_icache_data_i[10]
  PIN ram_cfg_icache_data_i[11]
    DIRECTION INPUT ;
    USE SIGNAL ;
    PORT
      LAYER met2 ;
        RECT 96.690 0.000 96.970 4.000 ;
    END
  END ram_cfg_icache_data_i[11]
  PIN ram_cfg_icache_data_i[1]
    DIRECTION INPUT ;
    USE SIGNAL ;
    PORT
      LAYER met2 ;
        RECT 93.470 0.000 93.750 4.000 ;
    END
  END ram_cfg_icache_data_i[1]
  PIN ram_cfg_icache_data_i[2]
    DIRECTION INPUT ;
    USE SIGNAL ;
    PORT
      LAYER met2 ;
        RECT 103.130 0.000 103.410 4.000 ;
    END
  END ram_cfg_icache_data_i[2]
  PIN ram_cfg_icache_data_i[3]
    DIRECTION INPUT ;
    USE SIGNAL ;
    PORT
      LAYER met2 ;
        RECT 119.230 0.000 119.510 4.000 ;
    END
  END ram_cfg_icache_data_i[3]
  PIN ram_cfg_icache_data_i[4]
    DIRECTION INPUT ;
    USE SIGNAL ;
    PORT
      LAYER met2 ;
        RECT 231.930 0.000 232.210 4.000 ;
    END
  END ram_cfg_icache_data_i[4]
  PIN ram_cfg_icache_data_i[5]
    DIRECTION INPUT ;
    USE SIGNAL ;
    PORT
      LAYER met2 ;
        RECT 106.350 0.000 106.630 4.000 ;
    END
  END ram_cfg_icache_data_i[5]
  PIN ram_cfg_icache_data_i[6]
    DIRECTION INPUT ;
    USE SIGNAL ;
    PORT
      LAYER met2 ;
        RECT 109.570 0.000 109.850 4.000 ;
    END
  END ram_cfg_icache_data_i[6]
  PIN ram_cfg_icache_data_i[7]
    DIRECTION INPUT ;
    USE SIGNAL ;
    PORT
      LAYER met2 ;
        RECT 164.310 0.000 164.590 4.000 ;
    END
  END ram_cfg_icache_data_i[7]
  PIN ram_cfg_icache_data_i[8]
    DIRECTION INPUT ;
    USE SIGNAL ;
    PORT
      LAYER met2 ;
        RECT 0.090 0.000 0.370 4.000 ;
    END
  END ram_cfg_icache_data_i[8]
  PIN ram_cfg_icache_data_i[9]
    DIRECTION INPUT ;
    USE SIGNAL ;
    PORT
      LAYER met2 ;
        RECT 257.690 0.000 257.970 4.000 ;
    END
  END ram_cfg_icache_data_i[9]
  PIN ram_cfg_icache_tag_i[0]
    DIRECTION INPUT ;
    USE SIGNAL ;
    PORT
      LAYER met2 ;
        RECT 122.450 0.000 122.730 4.000 ;
    END
  END ram_cfg_icache_tag_i[0]
  PIN ram_cfg_icache_tag_i[10]
    DIRECTION INPUT ;
    USE SIGNAL ;
    PORT
      LAYER met2 ;
        RECT 125.670 0.000 125.950 4.000 ;
    END
  END ram_cfg_icache_tag_i[10]
  PIN ram_cfg_icache_tag_i[11]
    DIRECTION INPUT ;
    USE SIGNAL ;
    PORT
      LAYER met2 ;
        RECT 128.890 0.000 129.170 4.000 ;
    END
  END ram_cfg_icache_tag_i[11]
  PIN ram_cfg_icache_tag_i[1]
    DIRECTION INPUT ;
    USE SIGNAL ;
    PORT
      LAYER met2 ;
        RECT 132.110 0.000 132.390 4.000 ;
    END
  END ram_cfg_icache_tag_i[1]
  PIN ram_cfg_icache_tag_i[2]
    DIRECTION INPUT ;
    USE SIGNAL ;
    PORT
      LAYER met2 ;
        RECT 135.330 0.000 135.610 4.000 ;
    END
  END ram_cfg_icache_tag_i[2]
  PIN ram_cfg_icache_tag_i[3]
    DIRECTION INPUT ;
    USE SIGNAL ;
    PORT
      LAYER met2 ;
        RECT 157.870 0.000 158.150 4.000 ;
    END
  END ram_cfg_icache_tag_i[3]
  PIN ram_cfg_icache_tag_i[4]
    DIRECTION INPUT ;
    USE SIGNAL ;
    PORT
      LAYER met2 ;
        RECT 141.770 0.000 142.050 4.000 ;
    END
  END ram_cfg_icache_tag_i[4]
  PIN ram_cfg_icache_tag_i[5]
    DIRECTION INPUT ;
    USE SIGNAL ;
    PORT
      LAYER met2 ;
        RECT 144.990 0.000 145.270 4.000 ;
    END
  END ram_cfg_icache_tag_i[5]
  PIN ram_cfg_icache_tag_i[6]
    DIRECTION INPUT ;
    USE SIGNAL ;
    PORT
      LAYER met2 ;
        RECT 148.210 0.000 148.490 4.000 ;
    END
  END ram_cfg_icache_tag_i[6]
  PIN ram_cfg_icache_tag_i[7]
    DIRECTION INPUT ;
    USE SIGNAL ;
    PORT
      LAYER met2 ;
        RECT 151.430 0.000 151.710 4.000 ;
    END
  END ram_cfg_icache_tag_i[7]
  PIN ram_cfg_icache_tag_i[8]
    DIRECTION INPUT ;
    USE SIGNAL ;
    PORT
      LAYER met2 ;
        RECT 154.650 0.000 154.930 4.000 ;
    END
  END ram_cfg_icache_tag_i[8]
  PIN ram_cfg_icache_tag_i[9]
    DIRECTION INPUT ;
    USE SIGNAL ;
    PORT
      LAYER met2 ;
        RECT 177.190 0.000 177.470 4.000 ;
    END
  END ram_cfg_icache_tag_i[9]
  PIN ram_cfg_rsp_icache_data_o[0]
    DIRECTION OUTPUT ;
    USE SIGNAL ;
    PORT
      LAYER met3 ;
        RECT 1396.000 1363.440 1400.000 1364.040 ;
    END
  END ram_cfg_rsp_icache_data_o[0]
  PIN ram_cfg_rsp_icache_data_o[1]
    DIRECTION OUTPUT ;
    USE SIGNAL ;
    PORT
      LAYER met2 ;
        RECT 1384.690 1396.000 1384.970 1400.000 ;
    END
  END ram_cfg_rsp_icache_data_o[1]
  PIN ram_cfg_rsp_icache_tag_o[0]
    DIRECTION OUTPUT ;
    USE SIGNAL ;
    PORT
      LAYER met2 ;
        RECT 718.150 0.000 718.430 4.000 ;
    END
  END ram_cfg_rsp_icache_tag_o[0]
  PIN ram_cfg_rsp_icache_tag_o[1]
    DIRECTION OUTPUT ;
    USE SIGNAL ;
    PORT
      LAYER met3 ;
        RECT 1396.000 632.440 1400.000 633.040 ;
    END
  END ram_cfg_rsp_icache_tag_o[1]
  PIN rst_ni
    DIRECTION INPUT ;
    USE SIGNAL ;
    ANTENNAGATEAREA 0.929700 ;
    ANTENNADIFFAREA 0.434700 ;
    PORT
      LAYER met3 ;
        RECT 1396.000 261.840 1400.000 262.440 ;
    END
  END rst_ni
  PIN scan_rst_ni
    DIRECTION INPUT ;
    USE SIGNAL ;
    PORT
      LAYER met2 ;
        RECT 161.090 0.000 161.370 4.000 ;
    END
  END scan_rst_ni
  PIN scramble_key_i[0]
    DIRECTION INPUT ;
    USE SIGNAL ;
    PORT
      LAYER met2 ;
        RECT 215.830 0.000 216.110 4.000 ;
    END
  END scramble_key_i[0]
  PIN scramble_key_i[100]
    DIRECTION INPUT ;
    USE SIGNAL ;
    PORT
      LAYER met2 ;
        RECT 167.530 0.000 167.810 4.000 ;
    END
  END scramble_key_i[100]
  PIN scramble_key_i[101]
    DIRECTION INPUT ;
    USE SIGNAL ;
    PORT
      LAYER met2 ;
        RECT 225.490 0.000 225.770 4.000 ;
    END
  END scramble_key_i[101]
  PIN scramble_key_i[102]
    DIRECTION INPUT ;
    USE SIGNAL ;
    PORT
      LAYER met2 ;
        RECT 173.970 0.000 174.250 4.000 ;
    END
  END scramble_key_i[102]
  PIN scramble_key_i[103]
    DIRECTION INPUT ;
    USE SIGNAL ;
    PORT
      LAYER met2 ;
        RECT 196.510 0.000 196.790 4.000 ;
    END
  END scramble_key_i[103]
  PIN scramble_key_i[104]
    DIRECTION INPUT ;
    USE SIGNAL ;
    PORT
      LAYER met2 ;
        RECT 322.090 0.000 322.370 4.000 ;
    END
  END scramble_key_i[104]
  PIN scramble_key_i[105]
    DIRECTION INPUT ;
    USE SIGNAL ;
    PORT
      LAYER met2 ;
        RECT 183.630 0.000 183.910 4.000 ;
    END
  END scramble_key_i[105]
  PIN scramble_key_i[106]
    DIRECTION INPUT ;
    USE SIGNAL ;
    PORT
      LAYER met2 ;
        RECT 186.850 0.000 187.130 4.000 ;
    END
  END scramble_key_i[106]
  PIN scramble_key_i[107]
    DIRECTION INPUT ;
    USE SIGNAL ;
    PORT
      LAYER met2 ;
        RECT 190.070 0.000 190.350 4.000 ;
    END
  END scramble_key_i[107]
  PIN scramble_key_i[108]
    DIRECTION INPUT ;
    USE SIGNAL ;
    PORT
      LAYER met2 ;
        RECT 193.290 0.000 193.570 4.000 ;
    END
  END scramble_key_i[108]
  PIN scramble_key_i[109]
    DIRECTION INPUT ;
    USE SIGNAL ;
    PORT
      LAYER met2 ;
        RECT 248.030 0.000 248.310 4.000 ;
    END
  END scramble_key_i[109]
  PIN scramble_key_i[10]
    DIRECTION INPUT ;
    USE SIGNAL ;
    PORT
      LAYER met2 ;
        RECT 199.730 0.000 200.010 4.000 ;
    END
  END scramble_key_i[10]
  PIN scramble_key_i[110]
    DIRECTION INPUT ;
    USE SIGNAL ;
    PORT
      LAYER met2 ;
        RECT 202.950 0.000 203.230 4.000 ;
    END
  END scramble_key_i[110]
  PIN scramble_key_i[111]
    DIRECTION INPUT ;
    USE SIGNAL ;
    PORT
      LAYER met2 ;
        RECT 206.170 0.000 206.450 4.000 ;
    END
  END scramble_key_i[111]
  PIN scramble_key_i[112]
    DIRECTION INPUT ;
    USE SIGNAL ;
    PORT
      LAYER met2 ;
        RECT 58.050 0.000 58.330 4.000 ;
    END
  END scramble_key_i[112]
  PIN scramble_key_i[113]
    DIRECTION INPUT ;
    USE SIGNAL ;
    PORT
      LAYER met2 ;
        RECT 16.190 0.000 16.470 4.000 ;
    END
  END scramble_key_i[113]
  PIN scramble_key_i[114]
    DIRECTION INPUT ;
    USE SIGNAL ;
    PORT
      LAYER met2 ;
        RECT 235.150 0.000 235.430 4.000 ;
    END
  END scramble_key_i[114]
  PIN scramble_key_i[115]
    DIRECTION INPUT ;
    USE SIGNAL ;
    PORT
      LAYER met2 ;
        RECT 219.050 0.000 219.330 4.000 ;
    END
  END scramble_key_i[115]
  PIN scramble_key_i[116]
    DIRECTION INPUT ;
    USE SIGNAL ;
    PORT
      LAYER met2 ;
        RECT 222.270 0.000 222.550 4.000 ;
    END
  END scramble_key_i[116]
  PIN scramble_key_i[117]
    DIRECTION INPUT ;
    USE SIGNAL ;
    PORT
      LAYER met2 ;
        RECT 280.230 0.000 280.510 4.000 ;
    END
  END scramble_key_i[117]
  PIN scramble_key_i[118]
    DIRECTION INPUT ;
    USE SIGNAL ;
    PORT
      LAYER met2 ;
        RECT 228.710 0.000 228.990 4.000 ;
    END
  END scramble_key_i[118]
  PIN scramble_key_i[119]
    DIRECTION INPUT ;
    USE SIGNAL ;
    PORT
      LAYER met2 ;
        RECT 360.730 0.000 361.010 4.000 ;
    END
  END scramble_key_i[119]
  PIN scramble_key_i[11]
    DIRECTION INPUT ;
    USE SIGNAL ;
    PORT
      LAYER met2 ;
        RECT 254.470 0.000 254.750 4.000 ;
    END
  END scramble_key_i[11]
  PIN scramble_key_i[120]
    DIRECTION INPUT ;
    USE SIGNAL ;
    PORT
      LAYER met2 ;
        RECT 238.370 0.000 238.650 4.000 ;
    END
  END scramble_key_i[120]
  PIN scramble_key_i[121]
    DIRECTION INPUT ;
    USE SIGNAL ;
    PORT
      LAYER met2 ;
        RECT 241.590 0.000 241.870 4.000 ;
    END
  END scramble_key_i[121]
  PIN scramble_key_i[122]
    DIRECTION INPUT ;
    USE SIGNAL ;
    PORT
      LAYER met2 ;
        RECT 244.810 0.000 245.090 4.000 ;
    END
  END scramble_key_i[122]
  PIN scramble_key_i[123]
    DIRECTION INPUT ;
    USE SIGNAL ;
    PORT
      LAYER met2 ;
        RECT 296.330 0.000 296.610 4.000 ;
    END
  END scramble_key_i[123]
  PIN scramble_key_i[124]
    DIRECTION INPUT ;
    USE SIGNAL ;
    PORT
      LAYER met2 ;
        RECT 251.250 0.000 251.530 4.000 ;
    END
  END scramble_key_i[124]
  PIN scramble_key_i[125]
    DIRECTION INPUT ;
    USE SIGNAL ;
    PORT
      LAYER met2 ;
        RECT 273.790 0.000 274.070 4.000 ;
    END
  END scramble_key_i[125]
  PIN scramble_key_i[126]
    DIRECTION INPUT ;
    USE SIGNAL ;
    PORT
      LAYER met2 ;
        RECT 396.150 0.000 396.430 4.000 ;
    END
  END scramble_key_i[126]
  PIN scramble_key_i[127]
    DIRECTION INPUT ;
    USE SIGNAL ;
    PORT
      LAYER met2 ;
        RECT 260.910 0.000 261.190 4.000 ;
    END
  END scramble_key_i[127]
  PIN scramble_key_i[12]
    DIRECTION INPUT ;
    USE SIGNAL ;
    PORT
      LAYER met2 ;
        RECT 264.130 0.000 264.410 4.000 ;
    END
  END scramble_key_i[12]
  PIN scramble_key_i[13]
    DIRECTION INPUT ;
    USE SIGNAL ;
    PORT
      LAYER met2 ;
        RECT 267.350 0.000 267.630 4.000 ;
    END
  END scramble_key_i[13]
  PIN scramble_key_i[14]
    DIRECTION INPUT ;
    USE SIGNAL ;
    PORT
      LAYER met2 ;
        RECT 270.570 0.000 270.850 4.000 ;
    END
  END scramble_key_i[14]
  PIN scramble_key_i[15]
    DIRECTION INPUT ;
    USE SIGNAL ;
    PORT
      LAYER met2 ;
        RECT 293.110 0.000 293.390 4.000 ;
    END
  END scramble_key_i[15]
  PIN scramble_key_i[16]
    DIRECTION INPUT ;
    USE SIGNAL ;
    PORT
      LAYER met2 ;
        RECT 277.010 0.000 277.290 4.000 ;
    END
  END scramble_key_i[16]
  PIN scramble_key_i[17]
    DIRECTION INPUT ;
    USE SIGNAL ;
    PORT
      LAYER met2 ;
        RECT 3.310 0.000 3.590 4.000 ;
    END
  END scramble_key_i[17]
  PIN scramble_key_i[18]
    DIRECTION INPUT ;
    USE SIGNAL ;
    PORT
      LAYER met2 ;
        RECT 283.450 0.000 283.730 4.000 ;
    END
  END scramble_key_i[18]
  PIN scramble_key_i[19]
    DIRECTION INPUT ;
    USE SIGNAL ;
    PORT
      LAYER met2 ;
        RECT 286.670 0.000 286.950 4.000 ;
    END
  END scramble_key_i[19]
  PIN scramble_key_i[1]
    DIRECTION INPUT ;
    USE SIGNAL ;
    PORT
      LAYER met2 ;
        RECT 309.210 0.000 309.490 4.000 ;
    END
  END scramble_key_i[1]
  PIN scramble_key_i[20]
    DIRECTION INPUT ;
    USE SIGNAL ;
    PORT
      LAYER met2 ;
        RECT 299.550 0.000 299.830 4.000 ;
    END
  END scramble_key_i[20]
  PIN scramble_key_i[21]
    DIRECTION INPUT ;
    USE SIGNAL ;
    PORT
      LAYER met2 ;
        RECT 302.770 0.000 303.050 4.000 ;
    END
  END scramble_key_i[21]
  PIN scramble_key_i[22]
    DIRECTION INPUT ;
    USE SIGNAL ;
    PORT
      LAYER met2 ;
        RECT 347.850 0.000 348.130 4.000 ;
    END
  END scramble_key_i[22]
  PIN scramble_key_i[23]
    DIRECTION INPUT ;
    USE SIGNAL ;
    PORT
      LAYER met2 ;
        RECT 305.990 0.000 306.270 4.000 ;
    END
  END scramble_key_i[23]
  PIN scramble_key_i[24]
    DIRECTION INPUT ;
    USE SIGNAL ;
    PORT
      LAYER met2 ;
        RECT 634.430 0.000 634.710 4.000 ;
    END
  END scramble_key_i[24]
  PIN scramble_key_i[25]
    DIRECTION INPUT ;
    USE SIGNAL ;
    PORT
      LAYER met2 ;
        RECT 615.110 0.000 615.390 4.000 ;
    END
  END scramble_key_i[25]
  PIN scramble_key_i[26]
    DIRECTION INPUT ;
    USE SIGNAL ;
    PORT
      LAYER met2 ;
        RECT 328.530 0.000 328.810 4.000 ;
    END
  END scramble_key_i[26]
  PIN scramble_key_i[27]
    DIRECTION INPUT ;
    USE SIGNAL ;
    PORT
      LAYER met2 ;
        RECT 318.870 0.000 319.150 4.000 ;
    END
  END scramble_key_i[27]
  PIN scramble_key_i[28]
    DIRECTION INPUT ;
    USE SIGNAL ;
    PORT
      LAYER met2 ;
        RECT 325.310 0.000 325.590 4.000 ;
    END
  END scramble_key_i[28]
  PIN scramble_key_i[29]
    DIRECTION INPUT ;
    USE SIGNAL ;
    PORT
      LAYER met2 ;
        RECT 338.190 0.000 338.470 4.000 ;
    END
  END scramble_key_i[29]
  PIN scramble_key_i[2]
    DIRECTION INPUT ;
    USE SIGNAL ;
    PORT
      LAYER met2 ;
        RECT 460.550 0.000 460.830 4.000 ;
    END
  END scramble_key_i[2]
  PIN scramble_key_i[30]
    DIRECTION INPUT ;
    USE SIGNAL ;
    PORT
      LAYER met2 ;
        RECT 376.830 0.000 377.110 4.000 ;
    END
  END scramble_key_i[30]
  PIN scramble_key_i[31]
    DIRECTION INPUT ;
    USE SIGNAL ;
    PORT
      LAYER met2 ;
        RECT 380.050 0.000 380.330 4.000 ;
    END
  END scramble_key_i[31]
  PIN scramble_key_i[32]
    DIRECTION INPUT ;
    USE SIGNAL ;
    PORT
      LAYER met2 ;
        RECT 341.410 0.000 341.690 4.000 ;
    END
  END scramble_key_i[32]
  PIN scramble_key_i[33]
    DIRECTION INPUT ;
    USE SIGNAL ;
    PORT
      LAYER met2 ;
        RECT 334.970 0.000 335.250 4.000 ;
    END
  END scramble_key_i[33]
  PIN scramble_key_i[34]
    DIRECTION INPUT ;
    USE SIGNAL ;
    PORT
      LAYER met2 ;
        RECT 344.630 0.000 344.910 4.000 ;
    END
  END scramble_key_i[34]
  PIN scramble_key_i[35]
    DIRECTION INPUT ;
    USE SIGNAL ;
    PORT
      LAYER met2 ;
        RECT 351.070 0.000 351.350 4.000 ;
    END
  END scramble_key_i[35]
  PIN scramble_key_i[36]
    DIRECTION INPUT ;
    USE SIGNAL ;
    PORT
      LAYER met2 ;
        RECT 354.290 0.000 354.570 4.000 ;
    END
  END scramble_key_i[36]
  PIN scramble_key_i[37]
    DIRECTION INPUT ;
    USE SIGNAL ;
    PORT
      LAYER met2 ;
        RECT 367.170 0.000 367.450 4.000 ;
    END
  END scramble_key_i[37]
  PIN scramble_key_i[38]
    DIRECTION INPUT ;
    USE SIGNAL ;
    PORT
      LAYER met2 ;
        RECT 357.510 0.000 357.790 4.000 ;
    END
  END scramble_key_i[38]
  PIN scramble_key_i[39]
    DIRECTION INPUT ;
    USE SIGNAL ;
    PORT
      LAYER met2 ;
        RECT 363.950 0.000 364.230 4.000 ;
    END
  END scramble_key_i[39]
  PIN scramble_key_i[3]
    DIRECTION INPUT ;
    USE SIGNAL ;
    PORT
      LAYER met2 ;
        RECT 405.810 0.000 406.090 4.000 ;
    END
  END scramble_key_i[3]
  PIN scramble_key_i[40]
    DIRECTION INPUT ;
    USE SIGNAL ;
    PORT
      LAYER met2 ;
        RECT 489.530 0.000 489.810 4.000 ;
    END
  END scramble_key_i[40]
  PIN scramble_key_i[41]
    DIRECTION INPUT ;
    USE SIGNAL ;
    PORT
      LAYER met2 ;
        RECT 370.390 0.000 370.670 4.000 ;
    END
  END scramble_key_i[41]
  PIN scramble_key_i[42]
    DIRECTION INPUT ;
    USE SIGNAL ;
    PORT
      LAYER met2 ;
        RECT 386.490 0.000 386.770 4.000 ;
    END
  END scramble_key_i[42]
  PIN scramble_key_i[43]
    DIRECTION INPUT ;
    USE SIGNAL ;
    PORT
      LAYER met2 ;
        RECT 418.690 0.000 418.970 4.000 ;
    END
  END scramble_key_i[43]
  PIN scramble_key_i[44]
    DIRECTION INPUT ;
    USE SIGNAL ;
    PORT
      LAYER met2 ;
        RECT 373.610 0.000 373.890 4.000 ;
    END
  END scramble_key_i[44]
  PIN scramble_key_i[45]
    DIRECTION INPUT ;
    USE SIGNAL ;
    PORT
      LAYER met2 ;
        RECT 383.270 0.000 383.550 4.000 ;
    END
  END scramble_key_i[45]
  PIN scramble_key_i[46]
    DIRECTION INPUT ;
    USE SIGNAL ;
    PORT
      LAYER met2 ;
        RECT 389.710 0.000 389.990 4.000 ;
    END
  END scramble_key_i[46]
  PIN scramble_key_i[47]
    DIRECTION INPUT ;
    USE SIGNAL ;
    PORT
      LAYER met2 ;
        RECT 392.930 0.000 393.210 4.000 ;
    END
  END scramble_key_i[47]
  PIN scramble_key_i[48]
    DIRECTION INPUT ;
    USE SIGNAL ;
    PORT
      LAYER met2 ;
        RECT 431.570 0.000 431.850 4.000 ;
    END
  END scramble_key_i[48]
  PIN scramble_key_i[49]
    DIRECTION INPUT ;
    USE SIGNAL ;
    PORT
      LAYER met2 ;
        RECT 524.950 0.000 525.230 4.000 ;
    END
  END scramble_key_i[49]
  PIN scramble_key_i[4]
    DIRECTION INPUT ;
    USE SIGNAL ;
    PORT
      LAYER met2 ;
        RECT 402.590 0.000 402.870 4.000 ;
    END
  END scramble_key_i[4]
  PIN scramble_key_i[50]
    DIRECTION INPUT ;
    USE SIGNAL ;
    PORT
      LAYER met2 ;
        RECT 415.470 0.000 415.750 4.000 ;
    END
  END scramble_key_i[50]
  PIN scramble_key_i[51]
    DIRECTION INPUT ;
    USE SIGNAL ;
    PORT
      LAYER met2 ;
        RECT 399.370 0.000 399.650 4.000 ;
    END
  END scramble_key_i[51]
  PIN scramble_key_i[52]
    DIRECTION INPUT ;
    USE SIGNAL ;
    PORT
      LAYER met2 ;
        RECT 409.030 0.000 409.310 4.000 ;
    END
  END scramble_key_i[52]
  PIN scramble_key_i[53]
    DIRECTION INPUT ;
    USE SIGNAL ;
    PORT
      LAYER met2 ;
        RECT 425.130 0.000 425.410 4.000 ;
    END
  END scramble_key_i[53]
  PIN scramble_key_i[54]
    DIRECTION INPUT ;
    USE SIGNAL ;
    PORT
      LAYER met2 ;
        RECT 547.490 0.000 547.770 4.000 ;
    END
  END scramble_key_i[54]
  PIN scramble_key_i[55]
    DIRECTION INPUT ;
    USE SIGNAL ;
    PORT
      LAYER met2 ;
        RECT 412.250 0.000 412.530 4.000 ;
    END
  END scramble_key_i[55]
  PIN scramble_key_i[56]
    DIRECTION INPUT ;
    USE SIGNAL ;
    PORT
      LAYER met2 ;
        RECT 421.910 0.000 422.190 4.000 ;
    END
  END scramble_key_i[56]
  PIN scramble_key_i[57]
    DIRECTION INPUT ;
    USE SIGNAL ;
    PORT
      LAYER met2 ;
        RECT 428.350 0.000 428.630 4.000 ;
    END
  END scramble_key_i[57]
  PIN scramble_key_i[58]
    DIRECTION INPUT ;
    USE SIGNAL ;
    PORT
      LAYER met2 ;
        RECT 470.210 0.000 470.490 4.000 ;
    END
  END scramble_key_i[58]
  PIN scramble_key_i[59]
    DIRECTION INPUT ;
    USE SIGNAL ;
    PORT
      LAYER met2 ;
        RECT 444.450 0.000 444.730 4.000 ;
    END
  END scramble_key_i[59]
  PIN scramble_key_i[5]
    DIRECTION INPUT ;
    USE SIGNAL ;
    PORT
      LAYER met2 ;
        RECT 434.790 0.000 435.070 4.000 ;
    END
  END scramble_key_i[5]
  PIN scramble_key_i[60]
    DIRECTION INPUT ;
    USE SIGNAL ;
    PORT
      LAYER met2 ;
        RECT 312.430 0.000 312.710 4.000 ;
    END
  END scramble_key_i[60]
  PIN scramble_key_i[61]
    DIRECTION INPUT ;
    USE SIGNAL ;
    PORT
      LAYER met2 ;
        RECT 6.530 0.000 6.810 4.000 ;
    END
  END scramble_key_i[61]
  PIN scramble_key_i[62]
    DIRECTION INPUT ;
    USE SIGNAL ;
    PORT
      LAYER met2 ;
        RECT 54.830 0.000 55.110 4.000 ;
    END
  END scramble_key_i[62]
  PIN scramble_key_i[63]
    DIRECTION INPUT ;
    USE SIGNAL ;
    PORT
      LAYER met2 ;
        RECT 447.670 0.000 447.950 4.000 ;
    END
  END scramble_key_i[63]
  PIN scramble_key_i[64]
    DIRECTION INPUT ;
    USE SIGNAL ;
    PORT
      LAYER met2 ;
        RECT 463.770 0.000 464.050 4.000 ;
    END
  END scramble_key_i[64]
  PIN scramble_key_i[65]
    DIRECTION INPUT ;
    USE SIGNAL ;
    PORT
      LAYER met2 ;
        RECT 457.330 0.000 457.610 4.000 ;
    END
  END scramble_key_i[65]
  PIN scramble_key_i[66]
    DIRECTION INPUT ;
    USE SIGNAL ;
    PORT
      LAYER met2 ;
        RECT 450.890 0.000 451.170 4.000 ;
    END
  END scramble_key_i[66]
  PIN scramble_key_i[67]
    DIRECTION INPUT ;
    USE SIGNAL ;
    PORT
      LAYER met2 ;
        RECT 505.630 0.000 505.910 4.000 ;
    END
  END scramble_key_i[67]
  PIN scramble_key_i[68]
    DIRECTION INPUT ;
    USE SIGNAL ;
    PORT
      LAYER met2 ;
        RECT 466.990 0.000 467.270 4.000 ;
    END
  END scramble_key_i[68]
  PIN scramble_key_i[69]
    DIRECTION INPUT ;
    USE SIGNAL ;
    PORT
      LAYER met2 ;
        RECT 508.850 0.000 509.130 4.000 ;
    END
  END scramble_key_i[69]
  PIN scramble_key_i[6]
    DIRECTION INPUT ;
    USE SIGNAL ;
    PORT
      LAYER met2 ;
        RECT 486.310 0.000 486.590 4.000 ;
    END
  END scramble_key_i[6]
  PIN scramble_key_i[70]
    DIRECTION INPUT ;
    USE SIGNAL ;
    PORT
      LAYER met2 ;
        RECT 473.430 0.000 473.710 4.000 ;
    END
  END scramble_key_i[70]
  PIN scramble_key_i[71]
    DIRECTION INPUT ;
    USE SIGNAL ;
    PORT
      LAYER met2 ;
        RECT 479.870 0.000 480.150 4.000 ;
    END
  END scramble_key_i[71]
  PIN scramble_key_i[72]
    DIRECTION INPUT ;
    USE SIGNAL ;
    PORT
      LAYER met2 ;
        RECT 22.630 0.000 22.910 4.000 ;
    END
  END scramble_key_i[72]
  PIN scramble_key_i[73]
    DIRECTION INPUT ;
    USE SIGNAL ;
    PORT
      LAYER met2 ;
        RECT 476.650 0.000 476.930 4.000 ;
    END
  END scramble_key_i[73]
  PIN scramble_key_i[74]
    DIRECTION INPUT ;
    USE SIGNAL ;
    PORT
      LAYER met2 ;
        RECT 502.410 0.000 502.690 4.000 ;
    END
  END scramble_key_i[74]
  PIN scramble_key_i[75]
    DIRECTION INPUT ;
    USE SIGNAL ;
    PORT
      LAYER met2 ;
        RECT 492.750 0.000 493.030 4.000 ;
    END
  END scramble_key_i[75]
  PIN scramble_key_i[76]
    DIRECTION INPUT ;
    USE SIGNAL ;
    PORT
      LAYER met2 ;
        RECT 495.970 0.000 496.250 4.000 ;
    END
  END scramble_key_i[76]
  PIN scramble_key_i[77]
    DIRECTION INPUT ;
    USE SIGNAL ;
    PORT
      LAYER met2 ;
        RECT 621.550 0.000 621.830 4.000 ;
    END
  END scramble_key_i[77]
  PIN scramble_key_i[78]
    DIRECTION INPUT ;
    USE SIGNAL ;
    PORT
      LAYER met2 ;
        RECT 499.190 0.000 499.470 4.000 ;
    END
  END scramble_key_i[78]
  PIN scramble_key_i[79]
    DIRECTION INPUT ;
    USE SIGNAL ;
    PORT
      LAYER met2 ;
        RECT 544.270 0.000 544.550 4.000 ;
    END
  END scramble_key_i[79]
  PIN scramble_key_i[7]
    DIRECTION INPUT ;
    USE SIGNAL ;
    PORT
      LAYER met2 ;
        RECT 637.650 0.000 637.930 4.000 ;
    END
  END scramble_key_i[7]
  PIN scramble_key_i[80]
    DIRECTION INPUT ;
    USE SIGNAL ;
    PORT
      LAYER met2 ;
        RECT 640.870 0.000 641.150 4.000 ;
    END
  END scramble_key_i[80]
  PIN scramble_key_i[81]
    DIRECTION INPUT ;
    USE SIGNAL ;
    PORT
      LAYER met2 ;
        RECT 512.070 0.000 512.350 4.000 ;
    END
  END scramble_key_i[81]
  PIN scramble_key_i[82]
    DIRECTION INPUT ;
    USE SIGNAL ;
    PORT
      LAYER met2 ;
        RECT 518.510 0.000 518.790 4.000 ;
    END
  END scramble_key_i[82]
  PIN scramble_key_i[83]
    DIRECTION INPUT ;
    USE SIGNAL ;
    PORT
      LAYER met2 ;
        RECT 521.730 0.000 522.010 4.000 ;
    END
  END scramble_key_i[83]
  PIN scramble_key_i[84]
    DIRECTION INPUT ;
    USE SIGNAL ;
    PORT
      LAYER met2 ;
        RECT 515.290 0.000 515.570 4.000 ;
    END
  END scramble_key_i[84]
  PIN scramble_key_i[85]
    DIRECTION INPUT ;
    USE SIGNAL ;
    PORT
      LAYER met2 ;
        RECT 541.050 0.000 541.330 4.000 ;
    END
  END scramble_key_i[85]
  PIN scramble_key_i[86]
    DIRECTION INPUT ;
    USE SIGNAL ;
    PORT
      LAYER met2 ;
        RECT 531.390 0.000 531.670 4.000 ;
    END
  END scramble_key_i[86]
  PIN scramble_key_i[87]
    DIRECTION INPUT ;
    USE SIGNAL ;
    PORT
      LAYER met2 ;
        RECT 534.610 0.000 534.890 4.000 ;
    END
  END scramble_key_i[87]
  PIN scramble_key_i[88]
    DIRECTION INPUT ;
    USE SIGNAL ;
    PORT
      LAYER met2 ;
        RECT 528.170 0.000 528.450 4.000 ;
    END
  END scramble_key_i[88]
  PIN scramble_key_i[89]
    DIRECTION INPUT ;
    USE SIGNAL ;
    PORT
      LAYER met2 ;
        RECT 537.830 0.000 538.110 4.000 ;
    END
  END scramble_key_i[89]
  PIN scramble_key_i[8]
    DIRECTION INPUT ;
    USE SIGNAL ;
    PORT
      LAYER met2 ;
        RECT 579.690 0.000 579.970 4.000 ;
    END
  END scramble_key_i[8]
  PIN scramble_key_i[90]
    DIRECTION INPUT ;
    USE SIGNAL ;
    PORT
      LAYER met2 ;
        RECT 586.130 0.000 586.410 4.000 ;
    END
  END scramble_key_i[90]
  PIN scramble_key_i[91]
    DIRECTION INPUT ;
    USE SIGNAL ;
    PORT
      LAYER met2 ;
        RECT 563.590 0.000 563.870 4.000 ;
    END
  END scramble_key_i[91]
  PIN scramble_key_i[92]
    DIRECTION INPUT ;
    USE SIGNAL ;
    PORT
      LAYER met2 ;
        RECT 550.710 0.000 550.990 4.000 ;
    END
  END scramble_key_i[92]
  PIN scramble_key_i[93]
    DIRECTION INPUT ;
    USE SIGNAL ;
    PORT
      LAYER met2 ;
        RECT 557.150 0.000 557.430 4.000 ;
    END
  END scramble_key_i[93]
  PIN scramble_key_i[94]
    DIRECTION INPUT ;
    USE SIGNAL ;
    PORT
      LAYER met2 ;
        RECT 560.370 0.000 560.650 4.000 ;
    END
  END scramble_key_i[94]
  PIN scramble_key_i[95]
    DIRECTION INPUT ;
    USE SIGNAL ;
    PORT
      LAYER met2 ;
        RECT 553.930 0.000 554.210 4.000 ;
    END
  END scramble_key_i[95]
  PIN scramble_key_i[96]
    DIRECTION INPUT ;
    USE SIGNAL ;
    PORT
      LAYER met2 ;
        RECT 602.230 0.000 602.510 4.000 ;
    END
  END scramble_key_i[96]
  PIN scramble_key_i[97]
    DIRECTION INPUT ;
    USE SIGNAL ;
    PORT
      LAYER met2 ;
        RECT 570.030 0.000 570.310 4.000 ;
    END
  END scramble_key_i[97]
  PIN scramble_key_i[98]
    DIRECTION INPUT ;
    USE SIGNAL ;
    PORT
      LAYER met2 ;
        RECT 573.250 0.000 573.530 4.000 ;
    END
  END scramble_key_i[98]
  PIN scramble_key_i[99]
    DIRECTION INPUT ;
    USE SIGNAL ;
    PORT
      LAYER met2 ;
        RECT 631.210 0.000 631.490 4.000 ;
    END
  END scramble_key_i[99]
  PIN scramble_key_i[9]
    DIRECTION INPUT ;
    USE SIGNAL ;
    PORT
      LAYER met2 ;
        RECT 576.470 0.000 576.750 4.000 ;
    END
  END scramble_key_i[9]
  PIN scramble_key_valid_i
    DIRECTION INPUT ;
    USE SIGNAL ;
    PORT
      LAYER met2 ;
        RECT 582.910 0.000 583.190 4.000 ;
    END
  END scramble_key_valid_i
  PIN scramble_nonce_i[0]
    DIRECTION INPUT ;
    USE SIGNAL ;
    PORT
      LAYER met2 ;
        RECT 624.770 0.000 625.050 4.000 ;
    END
  END scramble_nonce_i[0]
  PIN scramble_nonce_i[10]
    DIRECTION INPUT ;
    USE SIGNAL ;
    PORT
      LAYER met2 ;
        RECT 627.990 0.000 628.270 4.000 ;
    END
  END scramble_nonce_i[10]
  PIN scramble_nonce_i[11]
    DIRECTION INPUT ;
    USE SIGNAL ;
    PORT
      LAYER met2 ;
        RECT 589.350 0.000 589.630 4.000 ;
    END
  END scramble_nonce_i[11]
  PIN scramble_nonce_i[12]
    DIRECTION INPUT ;
    USE SIGNAL ;
    PORT
      LAYER met2 ;
        RECT 595.790 0.000 596.070 4.000 ;
    END
  END scramble_nonce_i[12]
  PIN scramble_nonce_i[13]
    DIRECTION INPUT ;
    USE SIGNAL ;
    PORT
      LAYER met2 ;
        RECT 599.010 0.000 599.290 4.000 ;
    END
  END scramble_nonce_i[13]
  PIN scramble_nonce_i[14]
    DIRECTION INPUT ;
    USE SIGNAL ;
    PORT
      LAYER met2 ;
        RECT 138.550 0.000 138.830 4.000 ;
    END
  END scramble_nonce_i[14]
  PIN scramble_nonce_i[15]
    DIRECTION INPUT ;
    USE SIGNAL ;
    PORT
      LAYER met2 ;
        RECT 618.330 0.000 618.610 4.000 ;
    END
  END scramble_nonce_i[15]
  PIN scramble_nonce_i[16]
    DIRECTION INPUT ;
    USE SIGNAL ;
    PORT
      LAYER met2 ;
        RECT 608.670 0.000 608.950 4.000 ;
    END
  END scramble_nonce_i[16]
  PIN scramble_nonce_i[17]
    DIRECTION INPUT ;
    USE SIGNAL ;
    PORT
      LAYER met2 ;
        RECT 611.890 0.000 612.170 4.000 ;
    END
  END scramble_nonce_i[17]
  PIN scramble_nonce_i[18]
    DIRECTION INPUT ;
    USE SIGNAL ;
    PORT
      LAYER met2 ;
        RECT 605.450 0.000 605.730 4.000 ;
    END
  END scramble_nonce_i[18]
  PIN scramble_nonce_i[19]
    DIRECTION INPUT ;
    USE SIGNAL ;
    PORT
      LAYER met2 ;
        RECT 1123.870 0.000 1124.150 4.000 ;
    END
  END scramble_nonce_i[19]
  PIN scramble_nonce_i[1]
    DIRECTION INPUT ;
    USE SIGNAL ;
    PORT
      LAYER met2 ;
        RECT 666.630 0.000 666.910 4.000 ;
    END
  END scramble_nonce_i[1]
  PIN scramble_nonce_i[20]
    DIRECTION INPUT ;
    USE SIGNAL ;
    PORT
      LAYER met2 ;
        RECT 673.070 0.000 673.350 4.000 ;
    END
  END scramble_nonce_i[20]
  PIN scramble_nonce_i[21]
    DIRECTION INPUT ;
    USE SIGNAL ;
    PORT
      LAYER met2 ;
        RECT 1082.010 0.000 1082.290 4.000 ;
    END
  END scramble_nonce_i[21]
  PIN scramble_nonce_i[22]
    DIRECTION INPUT ;
    USE SIGNAL ;
    PORT
      LAYER met2 ;
        RECT 1133.530 0.000 1133.810 4.000 ;
    END
  END scramble_nonce_i[22]
  PIN scramble_nonce_i[23]
    DIRECTION INPUT ;
    USE SIGNAL ;
    PORT
      LAYER met2 ;
        RECT 650.530 0.000 650.810 4.000 ;
    END
  END scramble_nonce_i[23]
  PIN scramble_nonce_i[24]
    DIRECTION INPUT ;
    USE SIGNAL ;
    PORT
      LAYER met2 ;
        RECT 1146.410 0.000 1146.690 4.000 ;
    END
  END scramble_nonce_i[24]
  PIN scramble_nonce_i[25]
    DIRECTION INPUT ;
    USE SIGNAL ;
    PORT
      LAYER met2 ;
        RECT 1120.650 0.000 1120.930 4.000 ;
    END
  END scramble_nonce_i[25]
  PIN scramble_nonce_i[26]
    DIRECTION INPUT ;
    USE SIGNAL ;
    PORT
      LAYER met2 ;
        RECT 1165.730 0.000 1166.010 4.000 ;
    END
  END scramble_nonce_i[26]
  PIN scramble_nonce_i[27]
    DIRECTION INPUT ;
    USE SIGNAL ;
    PORT
      LAYER met2 ;
        RECT 1188.270 0.000 1188.550 4.000 ;
    END
  END scramble_nonce_i[27]
  PIN scramble_nonce_i[28]
    DIRECTION INPUT ;
    USE SIGNAL ;
    PORT
      LAYER met2 ;
        RECT 1185.050 0.000 1185.330 4.000 ;
    END
  END scramble_nonce_i[28]
  PIN scramble_nonce_i[29]
    DIRECTION INPUT ;
    USE SIGNAL ;
    PORT
      LAYER met2 ;
        RECT 1168.950 0.000 1169.230 4.000 ;
    END
  END scramble_nonce_i[29]
  PIN scramble_nonce_i[2]
    DIRECTION INPUT ;
    USE SIGNAL ;
    PORT
      LAYER met2 ;
        RECT 663.410 0.000 663.690 4.000 ;
    END
  END scramble_nonce_i[2]
  PIN scramble_nonce_i[30]
    DIRECTION INPUT ;
    USE SIGNAL ;
    PORT
      LAYER met2 ;
        RECT 1104.550 0.000 1104.830 4.000 ;
    END
  END scramble_nonce_i[30]
  PIN scramble_nonce_i[31]
    DIRECTION INPUT ;
    USE SIGNAL ;
    PORT
      LAYER met2 ;
        RECT 892.030 0.000 892.310 4.000 ;
    END
  END scramble_nonce_i[31]
  PIN scramble_nonce_i[32]
    DIRECTION INPUT ;
    USE SIGNAL ;
    PORT
      LAYER met2 ;
        RECT 1117.430 0.000 1117.710 4.000 ;
    END
  END scramble_nonce_i[32]
  PIN scramble_nonce_i[33]
    DIRECTION INPUT ;
    USE SIGNAL ;
    PORT
      LAYER met2 ;
        RECT 1136.750 0.000 1137.030 4.000 ;
    END
  END scramble_nonce_i[33]
  PIN scramble_nonce_i[34]
    DIRECTION INPUT ;
    USE SIGNAL ;
    PORT
      LAYER met2 ;
        RECT 1059.470 0.000 1059.750 4.000 ;
    END
  END scramble_nonce_i[34]
  PIN scramble_nonce_i[35]
    DIRECTION INPUT ;
    USE SIGNAL ;
    PORT
      LAYER met2 ;
        RECT 1162.510 0.000 1162.790 4.000 ;
    END
  END scramble_nonce_i[35]
  PIN scramble_nonce_i[36]
    DIRECTION INPUT ;
    USE SIGNAL ;
    PORT
      LAYER met2 ;
        RECT 1139.970 0.000 1140.250 4.000 ;
    END
  END scramble_nonce_i[36]
  PIN scramble_nonce_i[37]
    DIRECTION INPUT ;
    USE SIGNAL ;
    PORT
      LAYER met2 ;
        RECT 1085.230 0.000 1085.510 4.000 ;
    END
  END scramble_nonce_i[37]
  PIN scramble_nonce_i[38]
    DIRECTION INPUT ;
    USE SIGNAL ;
    PORT
      LAYER met2 ;
        RECT 1107.770 0.000 1108.050 4.000 ;
    END
  END scramble_nonce_i[38]
  PIN scramble_nonce_i[39]
    DIRECTION INPUT ;
    USE SIGNAL ;
    PORT
      LAYER met2 ;
        RECT 1172.170 0.000 1172.450 4.000 ;
    END
  END scramble_nonce_i[39]
  PIN scramble_nonce_i[3]
    DIRECTION INPUT ;
    USE SIGNAL ;
    PORT
      LAYER met2 ;
        RECT 1094.890 0.000 1095.170 4.000 ;
    END
  END scramble_nonce_i[3]
  PIN scramble_nonce_i[40]
    DIRECTION INPUT ;
    USE SIGNAL ;
    PORT
      LAYER met2 ;
        RECT 1101.330 0.000 1101.610 4.000 ;
    END
  END scramble_nonce_i[40]
  PIN scramble_nonce_i[41]
    DIRECTION INPUT ;
    USE SIGNAL ;
    PORT
      LAYER met2 ;
        RECT 1062.690 0.000 1062.970 4.000 ;
    END
  END scramble_nonce_i[41]
  PIN scramble_nonce_i[42]
    DIRECTION INPUT ;
    USE SIGNAL ;
    PORT
      LAYER met2 ;
        RECT 1098.110 0.000 1098.390 4.000 ;
    END
  END scramble_nonce_i[42]
  PIN scramble_nonce_i[43]
    DIRECTION INPUT ;
    USE SIGNAL ;
    PORT
      LAYER met2 ;
        RECT 1130.310 0.000 1130.590 4.000 ;
    END
  END scramble_nonce_i[43]
  PIN scramble_nonce_i[44]
    DIRECTION INPUT ;
    USE SIGNAL ;
    PORT
      LAYER met2 ;
        RECT 1114.210 0.000 1114.490 4.000 ;
    END
  END scramble_nonce_i[44]
  PIN scramble_nonce_i[45]
    DIRECTION INPUT ;
    USE SIGNAL ;
    PORT
      LAYER met2 ;
        RECT 1181.830 0.000 1182.110 4.000 ;
    END
  END scramble_nonce_i[45]
  PIN scramble_nonce_i[46]
    DIRECTION INPUT ;
    USE SIGNAL ;
    PORT
      LAYER met2 ;
        RECT 1127.090 0.000 1127.370 4.000 ;
    END
  END scramble_nonce_i[46]
  PIN scramble_nonce_i[47]
    DIRECTION INPUT ;
    USE SIGNAL ;
    PORT
      LAYER met2 ;
        RECT 1175.390 0.000 1175.670 4.000 ;
    END
  END scramble_nonce_i[47]
  PIN scramble_nonce_i[48]
    DIRECTION INPUT ;
    USE SIGNAL ;
    PORT
      LAYER met2 ;
        RECT 888.810 0.000 889.090 4.000 ;
    END
  END scramble_nonce_i[48]
  PIN scramble_nonce_i[49]
    DIRECTION INPUT ;
    USE SIGNAL ;
    PORT
      LAYER met2 ;
        RECT 644.090 0.000 644.370 4.000 ;
    END
  END scramble_nonce_i[49]
  PIN scramble_nonce_i[4]
    DIRECTION INPUT ;
    USE SIGNAL ;
    PORT
      LAYER met2 ;
        RECT 669.850 0.000 670.130 4.000 ;
    END
  END scramble_nonce_i[4]
  PIN scramble_nonce_i[50]
    DIRECTION INPUT ;
    USE SIGNAL ;
    PORT
      LAYER met2 ;
        RECT 1088.450 0.000 1088.730 4.000 ;
    END
  END scramble_nonce_i[50]
  PIN scramble_nonce_i[51]
    DIRECTION INPUT ;
    USE SIGNAL ;
    PORT
      LAYER met2 ;
        RECT 1143.190 0.000 1143.470 4.000 ;
    END
  END scramble_nonce_i[51]
  PIN scramble_nonce_i[52]
    DIRECTION INPUT ;
    USE SIGNAL ;
    PORT
      LAYER met2 ;
        RECT 1065.910 0.000 1066.190 4.000 ;
    END
  END scramble_nonce_i[52]
  PIN scramble_nonce_i[53]
    DIRECTION INPUT ;
    USE SIGNAL ;
    PORT
      LAYER met2 ;
        RECT 660.190 0.000 660.470 4.000 ;
    END
  END scramble_nonce_i[53]
  PIN scramble_nonce_i[54]
    DIRECTION INPUT ;
    USE SIGNAL ;
    PORT
      LAYER met2 ;
        RECT 1149.630 0.000 1149.910 4.000 ;
    END
  END scramble_nonce_i[54]
  PIN scramble_nonce_i[55]
    DIRECTION INPUT ;
    USE SIGNAL ;
    PORT
      LAYER met2 ;
        RECT 1053.030 0.000 1053.310 4.000 ;
    END
  END scramble_nonce_i[55]
  PIN scramble_nonce_i[56]
    DIRECTION INPUT ;
    USE SIGNAL ;
    PORT
      LAYER met2 ;
        RECT 895.250 0.000 895.530 4.000 ;
    END
  END scramble_nonce_i[56]
  PIN scramble_nonce_i[57]
    DIRECTION INPUT ;
    USE SIGNAL ;
    PORT
      LAYER met2 ;
        RECT 647.310 0.000 647.590 4.000 ;
    END
  END scramble_nonce_i[57]
  PIN scramble_nonce_i[58]
    DIRECTION INPUT ;
    USE SIGNAL ;
    PORT
      LAYER met2 ;
        RECT 1075.570 0.000 1075.850 4.000 ;
    END
  END scramble_nonce_i[58]
  PIN scramble_nonce_i[59]
    DIRECTION INPUT ;
    USE SIGNAL ;
    PORT
      LAYER met2 ;
        RECT 1110.990 0.000 1111.270 4.000 ;
    END
  END scramble_nonce_i[59]
  PIN scramble_nonce_i[5]
    DIRECTION INPUT ;
    USE SIGNAL ;
    PORT
      LAYER met2 ;
        RECT 653.750 0.000 654.030 4.000 ;
    END
  END scramble_nonce_i[5]
  PIN scramble_nonce_i[60]
    DIRECTION INPUT ;
    USE SIGNAL ;
    PORT
      LAYER met2 ;
        RECT 1178.610 0.000 1178.890 4.000 ;
    END
  END scramble_nonce_i[60]
  PIN scramble_nonce_i[61]
    DIRECTION INPUT ;
    USE SIGNAL ;
    PORT
      LAYER met2 ;
        RECT 1152.850 0.000 1153.130 4.000 ;
    END
  END scramble_nonce_i[61]
  PIN scramble_nonce_i[62]
    DIRECTION INPUT ;
    USE SIGNAL ;
    PORT
      LAYER met2 ;
        RECT 656.970 0.000 657.250 4.000 ;
    END
  END scramble_nonce_i[62]
  PIN scramble_nonce_i[63]
    DIRECTION INPUT ;
    USE SIGNAL ;
    PORT
      LAYER met2 ;
        RECT 1156.070 0.000 1156.350 4.000 ;
    END
  END scramble_nonce_i[63]
  PIN scramble_nonce_i[6]
    DIRECTION INPUT ;
    USE SIGNAL ;
    PORT
      LAYER met2 ;
        RECT 1069.130 0.000 1069.410 4.000 ;
    END
  END scramble_nonce_i[6]
  PIN scramble_nonce_i[7]
    DIRECTION INPUT ;
    USE SIGNAL ;
    PORT
      LAYER met2 ;
        RECT 1159.290 0.000 1159.570 4.000 ;
    END
  END scramble_nonce_i[7]
  PIN scramble_nonce_i[8]
    DIRECTION INPUT ;
    USE SIGNAL ;
    PORT
      LAYER met2 ;
        RECT 1078.790 0.000 1079.070 4.000 ;
    END
  END scramble_nonce_i[8]
  PIN scramble_nonce_i[9]
    DIRECTION INPUT ;
    USE SIGNAL ;
    PORT
      LAYER met2 ;
        RECT 1072.350 0.000 1072.630 4.000 ;
    END
  END scramble_nonce_i[9]
  PIN scramble_req_o
    DIRECTION OUTPUT ;
    USE SIGNAL ;
    PORT
      LAYER met3 ;
        RECT 1396.000 326.440 1400.000 327.040 ;
    END
  END scramble_req_o
  PIN test_en_i
    DIRECTION INPUT ;
    USE SIGNAL ;
    ANTENNAGATEAREA 0.631200 ;
    ANTENNADIFFAREA 0.434700 ;
    PORT
      LAYER met3 ;
        RECT 1396.000 489.640 1400.000 490.240 ;
    END
  END test_en_i
  OBS
      LAYER nwell ;
        RECT 5.330 10.795 1394.450 1387.285 ;
      LAYER li1 ;
        RECT 5.520 10.795 1394.260 1387.285 ;
      LAYER met1 ;
        RECT 4.210 10.640 1397.410 1387.440 ;
      LAYER met2 ;
        RECT 4.230 1395.720 48.110 1397.925 ;
        RECT 48.950 1395.720 89.970 1397.925 ;
        RECT 90.810 1395.720 93.190 1397.925 ;
        RECT 94.030 1395.720 96.410 1397.925 ;
        RECT 97.250 1395.720 99.630 1397.925 ;
        RECT 100.470 1395.720 102.850 1397.925 ;
        RECT 103.690 1395.720 106.070 1397.925 ;
        RECT 106.910 1395.720 109.290 1397.925 ;
        RECT 110.130 1395.720 279.950 1397.925 ;
        RECT 280.790 1395.720 337.910 1397.925 ;
        RECT 338.750 1395.720 341.130 1397.925 ;
        RECT 341.970 1395.720 354.010 1397.925 ;
        RECT 354.850 1395.720 547.210 1397.925 ;
        RECT 548.050 1395.720 614.830 1397.925 ;
        RECT 615.670 1395.720 618.050 1397.925 ;
        RECT 618.890 1395.720 659.910 1397.925 ;
        RECT 660.750 1395.720 669.570 1397.925 ;
        RECT 670.410 1395.720 672.790 1397.925 ;
        RECT 673.630 1395.720 676.010 1397.925 ;
        RECT 676.850 1395.720 679.230 1397.925 ;
        RECT 680.070 1395.720 682.450 1397.925 ;
        RECT 683.290 1395.720 685.670 1397.925 ;
        RECT 686.510 1395.720 688.890 1397.925 ;
        RECT 689.730 1395.720 692.110 1397.925 ;
        RECT 692.950 1395.720 695.330 1397.925 ;
        RECT 696.170 1395.720 698.550 1397.925 ;
        RECT 699.390 1395.720 701.770 1397.925 ;
        RECT 702.610 1395.720 704.990 1397.925 ;
        RECT 705.830 1395.720 708.210 1397.925 ;
        RECT 709.050 1395.720 711.430 1397.925 ;
        RECT 712.270 1395.720 714.650 1397.925 ;
        RECT 715.490 1395.720 721.090 1397.925 ;
        RECT 721.930 1395.720 724.310 1397.925 ;
        RECT 725.150 1395.720 750.070 1397.925 ;
        RECT 750.910 1395.720 753.290 1397.925 ;
        RECT 754.130 1395.720 766.170 1397.925 ;
        RECT 767.010 1395.720 791.930 1397.925 ;
        RECT 792.770 1395.720 878.870 1397.925 ;
        RECT 879.710 1395.720 917.510 1397.925 ;
        RECT 918.350 1395.720 959.370 1397.925 ;
        RECT 960.210 1395.720 962.590 1397.925 ;
        RECT 963.430 1395.720 965.810 1397.925 ;
        RECT 966.650 1395.720 969.030 1397.925 ;
        RECT 969.870 1395.720 972.250 1397.925 ;
        RECT 973.090 1395.720 978.690 1397.925 ;
        RECT 979.530 1395.720 985.130 1397.925 ;
        RECT 985.970 1395.720 988.350 1397.925 ;
        RECT 989.190 1395.720 998.010 1397.925 ;
        RECT 998.850 1395.720 1023.770 1397.925 ;
        RECT 1024.610 1395.720 1033.430 1397.925 ;
        RECT 1034.270 1395.720 1039.870 1397.925 ;
        RECT 1040.710 1395.720 1052.750 1397.925 ;
        RECT 1053.590 1395.720 1055.970 1397.925 ;
        RECT 1056.810 1395.720 1065.630 1397.925 ;
        RECT 1066.470 1395.720 1068.850 1397.925 ;
        RECT 1069.690 1395.720 1072.070 1397.925 ;
        RECT 1072.910 1395.720 1075.290 1397.925 ;
        RECT 1076.130 1395.720 1081.730 1397.925 ;
        RECT 1082.570 1395.720 1084.950 1397.925 ;
        RECT 1085.790 1395.720 1088.170 1397.925 ;
        RECT 1089.010 1395.720 1091.390 1397.925 ;
        RECT 1092.230 1395.720 1094.610 1397.925 ;
        RECT 1095.450 1395.720 1097.830 1397.925 ;
        RECT 1098.670 1395.720 1101.050 1397.925 ;
        RECT 1101.890 1395.720 1104.270 1397.925 ;
        RECT 1105.110 1395.720 1107.490 1397.925 ;
        RECT 1108.330 1395.720 1110.710 1397.925 ;
        RECT 1111.550 1395.720 1113.930 1397.925 ;
        RECT 1114.770 1395.720 1117.150 1397.925 ;
        RECT 1117.990 1395.720 1120.370 1397.925 ;
        RECT 1121.210 1395.720 1123.590 1397.925 ;
        RECT 1124.430 1395.720 1126.810 1397.925 ;
        RECT 1127.650 1395.720 1130.030 1397.925 ;
        RECT 1130.870 1395.720 1133.250 1397.925 ;
        RECT 1134.090 1395.720 1136.470 1397.925 ;
        RECT 1137.310 1395.720 1139.690 1397.925 ;
        RECT 1140.530 1395.720 1146.130 1397.925 ;
        RECT 1146.970 1395.720 1149.350 1397.925 ;
        RECT 1150.190 1395.720 1152.570 1397.925 ;
        RECT 1153.410 1395.720 1155.790 1397.925 ;
        RECT 1156.630 1395.720 1165.450 1397.925 ;
        RECT 1166.290 1395.720 1178.330 1397.925 ;
        RECT 1179.170 1395.720 1184.770 1397.925 ;
        RECT 1185.610 1395.720 1194.430 1397.925 ;
        RECT 1195.270 1395.720 1210.530 1397.925 ;
        RECT 1211.370 1395.720 1384.410 1397.925 ;
        RECT 1385.250 1395.720 1397.380 1397.925 ;
        RECT 4.230 4.280 1397.380 1395.720 ;
        RECT 4.230 3.670 6.250 4.280 ;
        RECT 7.090 3.670 9.470 4.280 ;
        RECT 10.310 3.670 12.690 4.280 ;
        RECT 13.530 3.670 15.910 4.280 ;
        RECT 16.750 3.670 19.130 4.280 ;
        RECT 19.970 3.670 22.350 4.280 ;
        RECT 23.190 3.670 25.570 4.280 ;
        RECT 26.410 3.670 28.790 4.280 ;
        RECT 29.630 3.670 32.010 4.280 ;
        RECT 32.850 3.670 35.230 4.280 ;
        RECT 36.070 3.670 38.450 4.280 ;
        RECT 39.290 3.670 41.670 4.280 ;
        RECT 42.510 3.670 44.890 4.280 ;
        RECT 45.730 3.670 48.110 4.280 ;
        RECT 48.950 3.670 51.330 4.280 ;
        RECT 52.170 3.670 54.550 4.280 ;
        RECT 55.390 3.670 57.770 4.280 ;
        RECT 58.610 3.670 60.990 4.280 ;
        RECT 61.830 3.670 64.210 4.280 ;
        RECT 65.050 3.670 67.430 4.280 ;
        RECT 68.270 3.670 70.650 4.280 ;
        RECT 71.490 3.670 73.870 4.280 ;
        RECT 74.710 3.670 77.090 4.280 ;
        RECT 77.930 3.670 80.310 4.280 ;
        RECT 81.150 3.670 83.530 4.280 ;
        RECT 84.370 3.670 86.750 4.280 ;
        RECT 87.590 3.670 89.970 4.280 ;
        RECT 90.810 3.670 93.190 4.280 ;
        RECT 94.030 3.670 96.410 4.280 ;
        RECT 97.250 3.670 99.630 4.280 ;
        RECT 100.470 3.670 102.850 4.280 ;
        RECT 103.690 3.670 106.070 4.280 ;
        RECT 106.910 3.670 109.290 4.280 ;
        RECT 110.130 3.670 112.510 4.280 ;
        RECT 113.350 3.670 115.730 4.280 ;
        RECT 116.570 3.670 118.950 4.280 ;
        RECT 119.790 3.670 122.170 4.280 ;
        RECT 123.010 3.670 125.390 4.280 ;
        RECT 126.230 3.670 128.610 4.280 ;
        RECT 129.450 3.670 131.830 4.280 ;
        RECT 132.670 3.670 135.050 4.280 ;
        RECT 135.890 3.670 138.270 4.280 ;
        RECT 139.110 3.670 141.490 4.280 ;
        RECT 142.330 3.670 144.710 4.280 ;
        RECT 145.550 3.670 147.930 4.280 ;
        RECT 148.770 3.670 151.150 4.280 ;
        RECT 151.990 3.670 154.370 4.280 ;
        RECT 155.210 3.670 157.590 4.280 ;
        RECT 158.430 3.670 160.810 4.280 ;
        RECT 161.650 3.670 164.030 4.280 ;
        RECT 164.870 3.670 167.250 4.280 ;
        RECT 168.090 3.670 170.470 4.280 ;
        RECT 171.310 3.670 173.690 4.280 ;
        RECT 174.530 3.670 176.910 4.280 ;
        RECT 177.750 3.670 180.130 4.280 ;
        RECT 180.970 3.670 183.350 4.280 ;
        RECT 184.190 3.670 186.570 4.280 ;
        RECT 187.410 3.670 189.790 4.280 ;
        RECT 190.630 3.670 193.010 4.280 ;
        RECT 193.850 3.670 196.230 4.280 ;
        RECT 197.070 3.670 199.450 4.280 ;
        RECT 200.290 3.670 202.670 4.280 ;
        RECT 203.510 3.670 205.890 4.280 ;
        RECT 206.730 3.670 209.110 4.280 ;
        RECT 209.950 3.670 212.330 4.280 ;
        RECT 213.170 3.670 215.550 4.280 ;
        RECT 216.390 3.670 218.770 4.280 ;
        RECT 219.610 3.670 221.990 4.280 ;
        RECT 222.830 3.670 225.210 4.280 ;
        RECT 226.050 3.670 228.430 4.280 ;
        RECT 229.270 3.670 231.650 4.280 ;
        RECT 232.490 3.670 234.870 4.280 ;
        RECT 235.710 3.670 238.090 4.280 ;
        RECT 238.930 3.670 241.310 4.280 ;
        RECT 242.150 3.670 244.530 4.280 ;
        RECT 245.370 3.670 247.750 4.280 ;
        RECT 248.590 3.670 250.970 4.280 ;
        RECT 251.810 3.670 254.190 4.280 ;
        RECT 255.030 3.670 257.410 4.280 ;
        RECT 258.250 3.670 260.630 4.280 ;
        RECT 261.470 3.670 263.850 4.280 ;
        RECT 264.690 3.670 267.070 4.280 ;
        RECT 267.910 3.670 270.290 4.280 ;
        RECT 271.130 3.670 273.510 4.280 ;
        RECT 274.350 3.670 276.730 4.280 ;
        RECT 277.570 3.670 279.950 4.280 ;
        RECT 280.790 3.670 283.170 4.280 ;
        RECT 284.010 3.670 286.390 4.280 ;
        RECT 287.230 3.670 289.610 4.280 ;
        RECT 290.450 3.670 292.830 4.280 ;
        RECT 293.670 3.670 296.050 4.280 ;
        RECT 296.890 3.670 299.270 4.280 ;
        RECT 300.110 3.670 302.490 4.280 ;
        RECT 303.330 3.670 305.710 4.280 ;
        RECT 306.550 3.670 308.930 4.280 ;
        RECT 309.770 3.670 312.150 4.280 ;
        RECT 312.990 3.670 315.370 4.280 ;
        RECT 316.210 3.670 318.590 4.280 ;
        RECT 319.430 3.670 321.810 4.280 ;
        RECT 322.650 3.670 325.030 4.280 ;
        RECT 325.870 3.670 328.250 4.280 ;
        RECT 329.090 3.670 331.470 4.280 ;
        RECT 332.310 3.670 334.690 4.280 ;
        RECT 335.530 3.670 337.910 4.280 ;
        RECT 338.750 3.670 341.130 4.280 ;
        RECT 341.970 3.670 344.350 4.280 ;
        RECT 345.190 3.670 347.570 4.280 ;
        RECT 348.410 3.670 350.790 4.280 ;
        RECT 351.630 3.670 354.010 4.280 ;
        RECT 354.850 3.670 357.230 4.280 ;
        RECT 358.070 3.670 360.450 4.280 ;
        RECT 361.290 3.670 363.670 4.280 ;
        RECT 364.510 3.670 366.890 4.280 ;
        RECT 367.730 3.670 370.110 4.280 ;
        RECT 370.950 3.670 373.330 4.280 ;
        RECT 374.170 3.670 376.550 4.280 ;
        RECT 377.390 3.670 379.770 4.280 ;
        RECT 380.610 3.670 382.990 4.280 ;
        RECT 383.830 3.670 386.210 4.280 ;
        RECT 387.050 3.670 389.430 4.280 ;
        RECT 390.270 3.670 392.650 4.280 ;
        RECT 393.490 3.670 395.870 4.280 ;
        RECT 396.710 3.670 399.090 4.280 ;
        RECT 399.930 3.670 402.310 4.280 ;
        RECT 403.150 3.670 405.530 4.280 ;
        RECT 406.370 3.670 408.750 4.280 ;
        RECT 409.590 3.670 411.970 4.280 ;
        RECT 412.810 3.670 415.190 4.280 ;
        RECT 416.030 3.670 418.410 4.280 ;
        RECT 419.250 3.670 421.630 4.280 ;
        RECT 422.470 3.670 424.850 4.280 ;
        RECT 425.690 3.670 428.070 4.280 ;
        RECT 428.910 3.670 431.290 4.280 ;
        RECT 432.130 3.670 434.510 4.280 ;
        RECT 435.350 3.670 437.730 4.280 ;
        RECT 438.570 3.670 440.950 4.280 ;
        RECT 441.790 3.670 444.170 4.280 ;
        RECT 445.010 3.670 447.390 4.280 ;
        RECT 448.230 3.670 450.610 4.280 ;
        RECT 451.450 3.670 453.830 4.280 ;
        RECT 454.670 3.670 457.050 4.280 ;
        RECT 457.890 3.670 460.270 4.280 ;
        RECT 461.110 3.670 463.490 4.280 ;
        RECT 464.330 3.670 466.710 4.280 ;
        RECT 467.550 3.670 469.930 4.280 ;
        RECT 470.770 3.670 473.150 4.280 ;
        RECT 473.990 3.670 476.370 4.280 ;
        RECT 477.210 3.670 479.590 4.280 ;
        RECT 480.430 3.670 482.810 4.280 ;
        RECT 483.650 3.670 486.030 4.280 ;
        RECT 486.870 3.670 489.250 4.280 ;
        RECT 490.090 3.670 492.470 4.280 ;
        RECT 493.310 3.670 495.690 4.280 ;
        RECT 496.530 3.670 498.910 4.280 ;
        RECT 499.750 3.670 502.130 4.280 ;
        RECT 502.970 3.670 505.350 4.280 ;
        RECT 506.190 3.670 508.570 4.280 ;
        RECT 509.410 3.670 511.790 4.280 ;
        RECT 512.630 3.670 515.010 4.280 ;
        RECT 515.850 3.670 518.230 4.280 ;
        RECT 519.070 3.670 521.450 4.280 ;
        RECT 522.290 3.670 524.670 4.280 ;
        RECT 525.510 3.670 527.890 4.280 ;
        RECT 528.730 3.670 531.110 4.280 ;
        RECT 531.950 3.670 534.330 4.280 ;
        RECT 535.170 3.670 537.550 4.280 ;
        RECT 538.390 3.670 540.770 4.280 ;
        RECT 541.610 3.670 543.990 4.280 ;
        RECT 544.830 3.670 547.210 4.280 ;
        RECT 548.050 3.670 550.430 4.280 ;
        RECT 551.270 3.670 553.650 4.280 ;
        RECT 554.490 3.670 556.870 4.280 ;
        RECT 557.710 3.670 560.090 4.280 ;
        RECT 560.930 3.670 563.310 4.280 ;
        RECT 564.150 3.670 566.530 4.280 ;
        RECT 567.370 3.670 569.750 4.280 ;
        RECT 570.590 3.670 572.970 4.280 ;
        RECT 573.810 3.670 576.190 4.280 ;
        RECT 577.030 3.670 579.410 4.280 ;
        RECT 580.250 3.670 582.630 4.280 ;
        RECT 583.470 3.670 585.850 4.280 ;
        RECT 586.690 3.670 589.070 4.280 ;
        RECT 589.910 3.670 592.290 4.280 ;
        RECT 593.130 3.670 595.510 4.280 ;
        RECT 596.350 3.670 598.730 4.280 ;
        RECT 599.570 3.670 601.950 4.280 ;
        RECT 602.790 3.670 605.170 4.280 ;
        RECT 606.010 3.670 608.390 4.280 ;
        RECT 609.230 3.670 611.610 4.280 ;
        RECT 612.450 3.670 614.830 4.280 ;
        RECT 615.670 3.670 618.050 4.280 ;
        RECT 618.890 3.670 621.270 4.280 ;
        RECT 622.110 3.670 624.490 4.280 ;
        RECT 625.330 3.670 627.710 4.280 ;
        RECT 628.550 3.670 630.930 4.280 ;
        RECT 631.770 3.670 634.150 4.280 ;
        RECT 634.990 3.670 637.370 4.280 ;
        RECT 638.210 3.670 640.590 4.280 ;
        RECT 641.430 3.670 643.810 4.280 ;
        RECT 644.650 3.670 647.030 4.280 ;
        RECT 647.870 3.670 650.250 4.280 ;
        RECT 651.090 3.670 653.470 4.280 ;
        RECT 654.310 3.670 656.690 4.280 ;
        RECT 657.530 3.670 659.910 4.280 ;
        RECT 660.750 3.670 663.130 4.280 ;
        RECT 663.970 3.670 666.350 4.280 ;
        RECT 667.190 3.670 669.570 4.280 ;
        RECT 670.410 3.670 672.790 4.280 ;
        RECT 673.630 3.670 676.010 4.280 ;
        RECT 676.850 3.670 679.230 4.280 ;
        RECT 680.070 3.670 682.450 4.280 ;
        RECT 683.290 3.670 685.670 4.280 ;
        RECT 686.510 3.670 688.890 4.280 ;
        RECT 689.730 3.670 692.110 4.280 ;
        RECT 692.950 3.670 695.330 4.280 ;
        RECT 696.170 3.670 698.550 4.280 ;
        RECT 699.390 3.670 701.770 4.280 ;
        RECT 702.610 3.670 704.990 4.280 ;
        RECT 705.830 3.670 708.210 4.280 ;
        RECT 709.050 3.670 711.430 4.280 ;
        RECT 712.270 3.670 714.650 4.280 ;
        RECT 715.490 3.670 717.870 4.280 ;
        RECT 718.710 3.670 721.090 4.280 ;
        RECT 721.930 3.670 724.310 4.280 ;
        RECT 725.150 3.670 727.530 4.280 ;
        RECT 728.370 3.670 730.750 4.280 ;
        RECT 731.590 3.670 733.970 4.280 ;
        RECT 734.810 3.670 737.190 4.280 ;
        RECT 738.030 3.670 740.410 4.280 ;
        RECT 741.250 3.670 743.630 4.280 ;
        RECT 744.470 3.670 746.850 4.280 ;
        RECT 747.690 3.670 750.070 4.280 ;
        RECT 750.910 3.670 753.290 4.280 ;
        RECT 754.130 3.670 756.510 4.280 ;
        RECT 757.350 3.670 759.730 4.280 ;
        RECT 760.570 3.670 762.950 4.280 ;
        RECT 763.790 3.670 766.170 4.280 ;
        RECT 767.010 3.670 769.390 4.280 ;
        RECT 770.230 3.670 772.610 4.280 ;
        RECT 773.450 3.670 775.830 4.280 ;
        RECT 776.670 3.670 779.050 4.280 ;
        RECT 779.890 3.670 782.270 4.280 ;
        RECT 783.110 3.670 785.490 4.280 ;
        RECT 786.330 3.670 788.710 4.280 ;
        RECT 789.550 3.670 791.930 4.280 ;
        RECT 792.770 3.670 795.150 4.280 ;
        RECT 795.990 3.670 798.370 4.280 ;
        RECT 799.210 3.670 801.590 4.280 ;
        RECT 802.430 3.670 804.810 4.280 ;
        RECT 805.650 3.670 808.030 4.280 ;
        RECT 808.870 3.670 811.250 4.280 ;
        RECT 812.090 3.670 814.470 4.280 ;
        RECT 815.310 3.670 817.690 4.280 ;
        RECT 818.530 3.670 820.910 4.280 ;
        RECT 821.750 3.670 824.130 4.280 ;
        RECT 824.970 3.670 827.350 4.280 ;
        RECT 828.190 3.670 830.570 4.280 ;
        RECT 831.410 3.670 833.790 4.280 ;
        RECT 834.630 3.670 837.010 4.280 ;
        RECT 837.850 3.670 840.230 4.280 ;
        RECT 841.070 3.670 843.450 4.280 ;
        RECT 844.290 3.670 846.670 4.280 ;
        RECT 847.510 3.670 849.890 4.280 ;
        RECT 850.730 3.670 853.110 4.280 ;
        RECT 853.950 3.670 856.330 4.280 ;
        RECT 857.170 3.670 859.550 4.280 ;
        RECT 860.390 3.670 862.770 4.280 ;
        RECT 863.610 3.670 865.990 4.280 ;
        RECT 866.830 3.670 869.210 4.280 ;
        RECT 870.050 3.670 872.430 4.280 ;
        RECT 873.270 3.670 875.650 4.280 ;
        RECT 876.490 3.670 878.870 4.280 ;
        RECT 879.710 3.670 882.090 4.280 ;
        RECT 882.930 3.670 885.310 4.280 ;
        RECT 886.150 3.670 888.530 4.280 ;
        RECT 889.370 3.670 891.750 4.280 ;
        RECT 892.590 3.670 894.970 4.280 ;
        RECT 895.810 3.670 898.190 4.280 ;
        RECT 899.030 3.670 901.410 4.280 ;
        RECT 902.250 3.670 904.630 4.280 ;
        RECT 905.470 3.670 907.850 4.280 ;
        RECT 908.690 3.670 911.070 4.280 ;
        RECT 911.910 3.670 914.290 4.280 ;
        RECT 915.130 3.670 917.510 4.280 ;
        RECT 918.350 3.670 920.730 4.280 ;
        RECT 921.570 3.670 923.950 4.280 ;
        RECT 924.790 3.670 927.170 4.280 ;
        RECT 928.010 3.670 930.390 4.280 ;
        RECT 931.230 3.670 933.610 4.280 ;
        RECT 934.450 3.670 936.830 4.280 ;
        RECT 937.670 3.670 940.050 4.280 ;
        RECT 940.890 3.670 943.270 4.280 ;
        RECT 944.110 3.670 946.490 4.280 ;
        RECT 947.330 3.670 949.710 4.280 ;
        RECT 950.550 3.670 952.930 4.280 ;
        RECT 953.770 3.670 956.150 4.280 ;
        RECT 956.990 3.670 959.370 4.280 ;
        RECT 960.210 3.670 962.590 4.280 ;
        RECT 963.430 3.670 965.810 4.280 ;
        RECT 966.650 3.670 969.030 4.280 ;
        RECT 969.870 3.670 972.250 4.280 ;
        RECT 973.090 3.670 975.470 4.280 ;
        RECT 976.310 3.670 978.690 4.280 ;
        RECT 979.530 3.670 981.910 4.280 ;
        RECT 982.750 3.670 985.130 4.280 ;
        RECT 985.970 3.670 988.350 4.280 ;
        RECT 989.190 3.670 991.570 4.280 ;
        RECT 992.410 3.670 994.790 4.280 ;
        RECT 995.630 3.670 998.010 4.280 ;
        RECT 998.850 3.670 1001.230 4.280 ;
        RECT 1002.070 3.670 1004.450 4.280 ;
        RECT 1005.290 3.670 1007.670 4.280 ;
        RECT 1008.510 3.670 1010.890 4.280 ;
        RECT 1011.730 3.670 1014.110 4.280 ;
        RECT 1014.950 3.670 1017.330 4.280 ;
        RECT 1018.170 3.670 1020.550 4.280 ;
        RECT 1021.390 3.670 1023.770 4.280 ;
        RECT 1024.610 3.670 1026.990 4.280 ;
        RECT 1027.830 3.670 1030.210 4.280 ;
        RECT 1031.050 3.670 1033.430 4.280 ;
        RECT 1034.270 3.670 1036.650 4.280 ;
        RECT 1037.490 3.670 1039.870 4.280 ;
        RECT 1040.710 3.670 1043.090 4.280 ;
        RECT 1043.930 3.670 1046.310 4.280 ;
        RECT 1047.150 3.670 1049.530 4.280 ;
        RECT 1050.370 3.670 1052.750 4.280 ;
        RECT 1053.590 3.670 1055.970 4.280 ;
        RECT 1056.810 3.670 1059.190 4.280 ;
        RECT 1060.030 3.670 1062.410 4.280 ;
        RECT 1063.250 3.670 1065.630 4.280 ;
        RECT 1066.470 3.670 1068.850 4.280 ;
        RECT 1069.690 3.670 1072.070 4.280 ;
        RECT 1072.910 3.670 1075.290 4.280 ;
        RECT 1076.130 3.670 1078.510 4.280 ;
        RECT 1079.350 3.670 1081.730 4.280 ;
        RECT 1082.570 3.670 1084.950 4.280 ;
        RECT 1085.790 3.670 1088.170 4.280 ;
        RECT 1089.010 3.670 1091.390 4.280 ;
        RECT 1092.230 3.670 1094.610 4.280 ;
        RECT 1095.450 3.670 1097.830 4.280 ;
        RECT 1098.670 3.670 1101.050 4.280 ;
        RECT 1101.890 3.670 1104.270 4.280 ;
        RECT 1105.110 3.670 1107.490 4.280 ;
        RECT 1108.330 3.670 1110.710 4.280 ;
        RECT 1111.550 3.670 1113.930 4.280 ;
        RECT 1114.770 3.670 1117.150 4.280 ;
        RECT 1117.990 3.670 1120.370 4.280 ;
        RECT 1121.210 3.670 1123.590 4.280 ;
        RECT 1124.430 3.670 1126.810 4.280 ;
        RECT 1127.650 3.670 1130.030 4.280 ;
        RECT 1130.870 3.670 1133.250 4.280 ;
        RECT 1134.090 3.670 1136.470 4.280 ;
        RECT 1137.310 3.670 1139.690 4.280 ;
        RECT 1140.530 3.670 1142.910 4.280 ;
        RECT 1143.750 3.670 1146.130 4.280 ;
        RECT 1146.970 3.670 1149.350 4.280 ;
        RECT 1150.190 3.670 1152.570 4.280 ;
        RECT 1153.410 3.670 1155.790 4.280 ;
        RECT 1156.630 3.670 1159.010 4.280 ;
        RECT 1159.850 3.670 1162.230 4.280 ;
        RECT 1163.070 3.670 1165.450 4.280 ;
        RECT 1166.290 3.670 1168.670 4.280 ;
        RECT 1169.510 3.670 1171.890 4.280 ;
        RECT 1172.730 3.670 1175.110 4.280 ;
        RECT 1175.950 3.670 1178.330 4.280 ;
        RECT 1179.170 3.670 1181.550 4.280 ;
        RECT 1182.390 3.670 1184.770 4.280 ;
        RECT 1185.610 3.670 1187.990 4.280 ;
        RECT 1188.830 3.670 1287.810 4.280 ;
        RECT 1288.650 3.670 1291.030 4.280 ;
        RECT 1291.870 3.670 1294.250 4.280 ;
        RECT 1295.090 3.670 1297.470 4.280 ;
        RECT 1298.310 3.670 1300.690 4.280 ;
        RECT 1301.530 3.670 1303.910 4.280 ;
        RECT 1304.750 3.670 1307.130 4.280 ;
        RECT 1307.970 3.670 1365.090 4.280 ;
        RECT 1365.930 3.670 1371.530 4.280 ;
        RECT 1372.370 3.670 1397.380 4.280 ;
      LAYER met3 ;
        RECT 3.990 1397.040 1395.600 1397.905 ;
        RECT 3.990 1395.040 1396.000 1397.040 ;
        RECT 3.990 1393.640 1395.600 1395.040 ;
        RECT 3.990 1391.640 1396.000 1393.640 ;
        RECT 3.990 1390.240 1395.600 1391.640 ;
        RECT 3.990 1388.240 1396.000 1390.240 ;
        RECT 3.990 1386.840 1395.600 1388.240 ;
        RECT 3.990 1384.840 1396.000 1386.840 ;
        RECT 3.990 1383.440 1395.600 1384.840 ;
        RECT 3.990 1381.440 1396.000 1383.440 ;
        RECT 3.990 1380.040 1395.600 1381.440 ;
        RECT 3.990 1378.040 1396.000 1380.040 ;
        RECT 3.990 1376.640 1395.600 1378.040 ;
        RECT 3.990 1374.640 1396.000 1376.640 ;
        RECT 3.990 1373.240 1395.600 1374.640 ;
        RECT 3.990 1371.240 1396.000 1373.240 ;
        RECT 3.990 1369.840 1395.600 1371.240 ;
        RECT 3.990 1367.840 1396.000 1369.840 ;
        RECT 3.990 1366.440 1395.600 1367.840 ;
        RECT 3.990 1364.440 1396.000 1366.440 ;
        RECT 3.990 1363.040 1395.600 1364.440 ;
        RECT 3.990 1361.040 1396.000 1363.040 ;
        RECT 3.990 1359.640 1395.600 1361.040 ;
        RECT 3.990 1357.640 1396.000 1359.640 ;
        RECT 3.990 1356.240 1395.600 1357.640 ;
        RECT 3.990 1354.240 1396.000 1356.240 ;
        RECT 3.990 1352.840 1395.600 1354.240 ;
        RECT 3.990 1350.840 1396.000 1352.840 ;
        RECT 3.990 1349.440 1395.600 1350.840 ;
        RECT 3.990 1347.440 1396.000 1349.440 ;
        RECT 3.990 1346.040 1395.600 1347.440 ;
        RECT 3.990 1344.040 1396.000 1346.040 ;
        RECT 3.990 1342.640 1395.600 1344.040 ;
        RECT 3.990 1340.640 1396.000 1342.640 ;
        RECT 3.990 1339.240 1395.600 1340.640 ;
        RECT 3.990 1337.240 1396.000 1339.240 ;
        RECT 3.990 1335.840 1395.600 1337.240 ;
        RECT 3.990 1333.840 1396.000 1335.840 ;
        RECT 3.990 1332.440 1395.600 1333.840 ;
        RECT 3.990 1330.440 1396.000 1332.440 ;
        RECT 3.990 1329.040 1395.600 1330.440 ;
        RECT 3.990 1327.040 1396.000 1329.040 ;
        RECT 3.990 1325.640 1395.600 1327.040 ;
        RECT 3.990 1323.640 1396.000 1325.640 ;
        RECT 3.990 1322.240 1395.600 1323.640 ;
        RECT 3.990 1320.240 1396.000 1322.240 ;
        RECT 3.990 1318.840 1395.600 1320.240 ;
        RECT 3.990 1316.840 1396.000 1318.840 ;
        RECT 3.990 1315.440 1395.600 1316.840 ;
        RECT 3.990 1313.440 1396.000 1315.440 ;
        RECT 3.990 1312.040 1395.600 1313.440 ;
        RECT 3.990 1310.040 1396.000 1312.040 ;
        RECT 3.990 1308.640 1395.600 1310.040 ;
        RECT 3.990 1306.640 1396.000 1308.640 ;
        RECT 3.990 1305.240 1395.600 1306.640 ;
        RECT 3.990 1303.240 1396.000 1305.240 ;
        RECT 3.990 1301.840 1395.600 1303.240 ;
        RECT 3.990 1299.840 1396.000 1301.840 ;
        RECT 3.990 1298.440 1395.600 1299.840 ;
        RECT 3.990 1296.440 1396.000 1298.440 ;
        RECT 3.990 1295.040 1395.600 1296.440 ;
        RECT 3.990 1293.040 1396.000 1295.040 ;
        RECT 3.990 1291.640 1395.600 1293.040 ;
        RECT 3.990 1289.640 1396.000 1291.640 ;
        RECT 3.990 1288.240 1395.600 1289.640 ;
        RECT 3.990 1286.240 1396.000 1288.240 ;
        RECT 3.990 1284.840 1395.600 1286.240 ;
        RECT 3.990 1282.840 1396.000 1284.840 ;
        RECT 3.990 1281.440 1395.600 1282.840 ;
        RECT 3.990 1279.440 1396.000 1281.440 ;
        RECT 3.990 1278.040 1395.600 1279.440 ;
        RECT 3.990 1276.040 1396.000 1278.040 ;
        RECT 3.990 1274.640 1395.600 1276.040 ;
        RECT 3.990 1272.640 1396.000 1274.640 ;
        RECT 3.990 1271.240 1395.600 1272.640 ;
        RECT 3.990 1269.240 1396.000 1271.240 ;
        RECT 3.990 1267.840 1395.600 1269.240 ;
        RECT 3.990 1265.840 1396.000 1267.840 ;
        RECT 3.990 1264.440 1395.600 1265.840 ;
        RECT 3.990 1262.440 1396.000 1264.440 ;
        RECT 3.990 1261.040 1395.600 1262.440 ;
        RECT 3.990 1259.040 1396.000 1261.040 ;
        RECT 3.990 1257.640 1395.600 1259.040 ;
        RECT 3.990 1255.640 1396.000 1257.640 ;
        RECT 3.990 1254.240 1395.600 1255.640 ;
        RECT 3.990 1252.240 1396.000 1254.240 ;
        RECT 3.990 1250.840 1395.600 1252.240 ;
        RECT 3.990 1248.840 1396.000 1250.840 ;
        RECT 3.990 1247.440 1395.600 1248.840 ;
        RECT 3.990 1245.440 1396.000 1247.440 ;
        RECT 3.990 1244.040 1395.600 1245.440 ;
        RECT 3.990 1242.040 1396.000 1244.040 ;
        RECT 3.990 1240.640 1395.600 1242.040 ;
        RECT 3.990 1238.640 1396.000 1240.640 ;
        RECT 3.990 1237.240 1395.600 1238.640 ;
        RECT 3.990 1235.240 1396.000 1237.240 ;
        RECT 3.990 1233.840 1395.600 1235.240 ;
        RECT 3.990 1231.840 1396.000 1233.840 ;
        RECT 3.990 1230.440 1395.600 1231.840 ;
        RECT 3.990 1228.440 1396.000 1230.440 ;
        RECT 3.990 1227.040 1395.600 1228.440 ;
        RECT 3.990 1225.040 1396.000 1227.040 ;
        RECT 3.990 1223.640 1395.600 1225.040 ;
        RECT 3.990 1221.640 1396.000 1223.640 ;
        RECT 3.990 1220.240 1395.600 1221.640 ;
        RECT 3.990 1218.240 1396.000 1220.240 ;
        RECT 3.990 1216.840 1395.600 1218.240 ;
        RECT 3.990 1214.840 1396.000 1216.840 ;
        RECT 3.990 1213.440 1395.600 1214.840 ;
        RECT 3.990 1211.440 1396.000 1213.440 ;
        RECT 3.990 1210.040 1395.600 1211.440 ;
        RECT 3.990 1208.040 1396.000 1210.040 ;
        RECT 3.990 1206.640 1395.600 1208.040 ;
        RECT 3.990 1204.640 1396.000 1206.640 ;
        RECT 3.990 1203.240 1395.600 1204.640 ;
        RECT 3.990 1201.240 1396.000 1203.240 ;
        RECT 3.990 1199.840 1395.600 1201.240 ;
        RECT 3.990 1197.840 1396.000 1199.840 ;
        RECT 3.990 1196.440 1395.600 1197.840 ;
        RECT 3.990 1194.440 1396.000 1196.440 ;
        RECT 3.990 1193.040 1395.600 1194.440 ;
        RECT 3.990 1191.040 1396.000 1193.040 ;
        RECT 3.990 1189.640 1395.600 1191.040 ;
        RECT 3.990 1187.640 1396.000 1189.640 ;
        RECT 4.400 1186.240 1395.600 1187.640 ;
        RECT 3.990 1184.240 1396.000 1186.240 ;
        RECT 3.990 1182.840 1395.600 1184.240 ;
        RECT 3.990 1180.840 1396.000 1182.840 ;
        RECT 3.990 1179.440 1395.600 1180.840 ;
        RECT 3.990 1177.440 1396.000 1179.440 ;
        RECT 3.990 1176.040 1395.600 1177.440 ;
        RECT 3.990 1174.040 1396.000 1176.040 ;
        RECT 3.990 1172.640 1395.600 1174.040 ;
        RECT 3.990 1170.640 1396.000 1172.640 ;
        RECT 3.990 1169.240 1395.600 1170.640 ;
        RECT 3.990 1167.240 1396.000 1169.240 ;
        RECT 3.990 1165.840 1395.600 1167.240 ;
        RECT 3.990 1163.840 1396.000 1165.840 ;
        RECT 3.990 1162.440 1395.600 1163.840 ;
        RECT 3.990 1160.440 1396.000 1162.440 ;
        RECT 3.990 1159.040 1395.600 1160.440 ;
        RECT 3.990 1157.040 1396.000 1159.040 ;
        RECT 3.990 1155.640 1395.600 1157.040 ;
        RECT 3.990 1153.640 1396.000 1155.640 ;
        RECT 4.400 1152.240 1395.600 1153.640 ;
        RECT 3.990 1150.240 1396.000 1152.240 ;
        RECT 3.990 1148.840 1395.600 1150.240 ;
        RECT 3.990 1146.840 1396.000 1148.840 ;
        RECT 3.990 1145.440 1395.600 1146.840 ;
        RECT 3.990 1143.440 1396.000 1145.440 ;
        RECT 3.990 1142.040 1395.600 1143.440 ;
        RECT 3.990 1140.040 1396.000 1142.040 ;
        RECT 3.990 1138.640 1395.600 1140.040 ;
        RECT 3.990 1136.640 1396.000 1138.640 ;
        RECT 3.990 1135.240 1395.600 1136.640 ;
        RECT 3.990 1133.240 1396.000 1135.240 ;
        RECT 3.990 1131.840 1395.600 1133.240 ;
        RECT 3.990 1129.840 1396.000 1131.840 ;
        RECT 3.990 1128.440 1395.600 1129.840 ;
        RECT 3.990 1126.440 1396.000 1128.440 ;
        RECT 3.990 1125.040 1395.600 1126.440 ;
        RECT 3.990 1123.040 1396.000 1125.040 ;
        RECT 3.990 1121.640 1395.600 1123.040 ;
        RECT 3.990 1119.640 1396.000 1121.640 ;
        RECT 3.990 1118.240 1395.600 1119.640 ;
        RECT 3.990 1116.240 1396.000 1118.240 ;
        RECT 3.990 1114.840 1395.600 1116.240 ;
        RECT 3.990 1112.840 1396.000 1114.840 ;
        RECT 3.990 1111.440 1395.600 1112.840 ;
        RECT 3.990 1109.440 1396.000 1111.440 ;
        RECT 3.990 1108.040 1395.600 1109.440 ;
        RECT 3.990 1106.040 1396.000 1108.040 ;
        RECT 3.990 1104.640 1395.600 1106.040 ;
        RECT 3.990 1102.640 1396.000 1104.640 ;
        RECT 3.990 1101.240 1395.600 1102.640 ;
        RECT 3.990 1099.240 1396.000 1101.240 ;
        RECT 3.990 1097.840 1395.600 1099.240 ;
        RECT 3.990 1095.840 1396.000 1097.840 ;
        RECT 3.990 1094.440 1395.600 1095.840 ;
        RECT 3.990 1092.440 1396.000 1094.440 ;
        RECT 3.990 1091.040 1395.600 1092.440 ;
        RECT 3.990 1089.040 1396.000 1091.040 ;
        RECT 3.990 1087.640 1395.600 1089.040 ;
        RECT 3.990 1085.640 1396.000 1087.640 ;
        RECT 3.990 1084.240 1395.600 1085.640 ;
        RECT 3.990 1082.240 1396.000 1084.240 ;
        RECT 3.990 1080.840 1395.600 1082.240 ;
        RECT 3.990 1078.840 1396.000 1080.840 ;
        RECT 3.990 1077.440 1395.600 1078.840 ;
        RECT 3.990 1075.440 1396.000 1077.440 ;
        RECT 3.990 1074.040 1395.600 1075.440 ;
        RECT 3.990 1072.040 1396.000 1074.040 ;
        RECT 4.400 1070.640 1395.600 1072.040 ;
        RECT 3.990 1068.640 1396.000 1070.640 ;
        RECT 3.990 1067.240 1395.600 1068.640 ;
        RECT 3.990 1065.240 1396.000 1067.240 ;
        RECT 3.990 1063.840 1395.600 1065.240 ;
        RECT 3.990 1061.840 1396.000 1063.840 ;
        RECT 3.990 1060.440 1395.600 1061.840 ;
        RECT 3.990 1058.440 1396.000 1060.440 ;
        RECT 3.990 1057.040 1395.600 1058.440 ;
        RECT 3.990 1055.040 1396.000 1057.040 ;
        RECT 3.990 1053.640 1395.600 1055.040 ;
        RECT 3.990 1051.640 1396.000 1053.640 ;
        RECT 3.990 1050.240 1395.600 1051.640 ;
        RECT 3.990 1048.240 1396.000 1050.240 ;
        RECT 3.990 1046.840 1395.600 1048.240 ;
        RECT 3.990 1044.840 1396.000 1046.840 ;
        RECT 3.990 1043.440 1395.600 1044.840 ;
        RECT 3.990 1041.440 1396.000 1043.440 ;
        RECT 3.990 1040.040 1395.600 1041.440 ;
        RECT 3.990 1038.040 1396.000 1040.040 ;
        RECT 3.990 1036.640 1395.600 1038.040 ;
        RECT 3.990 1034.640 1396.000 1036.640 ;
        RECT 3.990 1033.240 1395.600 1034.640 ;
        RECT 3.990 1031.240 1396.000 1033.240 ;
        RECT 3.990 1029.840 1395.600 1031.240 ;
        RECT 3.990 1027.840 1396.000 1029.840 ;
        RECT 3.990 1026.440 1395.600 1027.840 ;
        RECT 3.990 1024.440 1396.000 1026.440 ;
        RECT 3.990 1023.040 1395.600 1024.440 ;
        RECT 3.990 1021.040 1396.000 1023.040 ;
        RECT 3.990 1019.640 1395.600 1021.040 ;
        RECT 3.990 1017.640 1396.000 1019.640 ;
        RECT 3.990 1016.240 1395.600 1017.640 ;
        RECT 3.990 1014.240 1396.000 1016.240 ;
        RECT 3.990 1012.840 1395.600 1014.240 ;
        RECT 3.990 1010.840 1396.000 1012.840 ;
        RECT 3.990 1009.440 1395.600 1010.840 ;
        RECT 3.990 1007.440 1396.000 1009.440 ;
        RECT 4.400 1006.040 1395.600 1007.440 ;
        RECT 3.990 1004.040 1396.000 1006.040 ;
        RECT 4.400 1002.640 1395.600 1004.040 ;
        RECT 3.990 1000.640 1396.000 1002.640 ;
        RECT 4.400 999.240 1395.600 1000.640 ;
        RECT 3.990 997.240 1396.000 999.240 ;
        RECT 3.990 995.840 1395.600 997.240 ;
        RECT 3.990 993.840 1396.000 995.840 ;
        RECT 3.990 992.440 1395.600 993.840 ;
        RECT 3.990 990.440 1396.000 992.440 ;
        RECT 3.990 989.040 1395.600 990.440 ;
        RECT 3.990 987.040 1396.000 989.040 ;
        RECT 4.400 985.640 1395.600 987.040 ;
        RECT 3.990 983.640 1396.000 985.640 ;
        RECT 3.990 982.240 1395.600 983.640 ;
        RECT 3.990 980.240 1396.000 982.240 ;
        RECT 3.990 978.840 1395.600 980.240 ;
        RECT 3.990 976.840 1396.000 978.840 ;
        RECT 3.990 975.440 1395.600 976.840 ;
        RECT 3.990 973.440 1396.000 975.440 ;
        RECT 3.990 972.040 1395.600 973.440 ;
        RECT 3.990 970.040 1396.000 972.040 ;
        RECT 3.990 968.640 1395.600 970.040 ;
        RECT 3.990 966.640 1396.000 968.640 ;
        RECT 3.990 965.240 1395.600 966.640 ;
        RECT 3.990 963.240 1396.000 965.240 ;
        RECT 3.990 961.840 1395.600 963.240 ;
        RECT 3.990 959.840 1396.000 961.840 ;
        RECT 3.990 958.440 1395.600 959.840 ;
        RECT 3.990 956.440 1396.000 958.440 ;
        RECT 3.990 955.040 1395.600 956.440 ;
        RECT 3.990 953.040 1396.000 955.040 ;
        RECT 3.990 951.640 1395.600 953.040 ;
        RECT 3.990 949.640 1396.000 951.640 ;
        RECT 3.990 948.240 1395.600 949.640 ;
        RECT 3.990 946.240 1396.000 948.240 ;
        RECT 3.990 944.840 1395.600 946.240 ;
        RECT 3.990 942.840 1396.000 944.840 ;
        RECT 4.400 941.440 1395.600 942.840 ;
        RECT 3.990 939.440 1396.000 941.440 ;
        RECT 3.990 938.040 1395.600 939.440 ;
        RECT 3.990 936.040 1396.000 938.040 ;
        RECT 3.990 934.640 1395.600 936.040 ;
        RECT 3.990 932.640 1396.000 934.640 ;
        RECT 3.990 931.240 1395.600 932.640 ;
        RECT 3.990 929.240 1396.000 931.240 ;
        RECT 3.990 927.840 1395.600 929.240 ;
        RECT 3.990 925.840 1396.000 927.840 ;
        RECT 3.990 924.440 1395.600 925.840 ;
        RECT 3.990 922.440 1396.000 924.440 ;
        RECT 3.990 921.040 1395.600 922.440 ;
        RECT 3.990 919.040 1396.000 921.040 ;
        RECT 3.990 917.640 1395.600 919.040 ;
        RECT 3.990 915.640 1396.000 917.640 ;
        RECT 3.990 914.240 1395.600 915.640 ;
        RECT 3.990 912.240 1396.000 914.240 ;
        RECT 3.990 910.840 1395.600 912.240 ;
        RECT 3.990 908.840 1396.000 910.840 ;
        RECT 3.990 907.440 1395.600 908.840 ;
        RECT 3.990 905.440 1396.000 907.440 ;
        RECT 3.990 904.040 1395.600 905.440 ;
        RECT 3.990 902.040 1396.000 904.040 ;
        RECT 3.990 900.640 1395.600 902.040 ;
        RECT 3.990 898.640 1396.000 900.640 ;
        RECT 3.990 897.240 1395.600 898.640 ;
        RECT 3.990 895.240 1396.000 897.240 ;
        RECT 3.990 893.840 1395.600 895.240 ;
        RECT 3.990 891.840 1396.000 893.840 ;
        RECT 3.990 890.440 1395.600 891.840 ;
        RECT 3.990 888.440 1396.000 890.440 ;
        RECT 3.990 887.040 1395.600 888.440 ;
        RECT 3.990 885.040 1396.000 887.040 ;
        RECT 3.990 883.640 1395.600 885.040 ;
        RECT 3.990 881.640 1396.000 883.640 ;
        RECT 3.990 880.240 1395.600 881.640 ;
        RECT 3.990 878.240 1396.000 880.240 ;
        RECT 3.990 876.840 1395.600 878.240 ;
        RECT 3.990 874.840 1396.000 876.840 ;
        RECT 3.990 873.440 1395.600 874.840 ;
        RECT 3.990 871.440 1396.000 873.440 ;
        RECT 3.990 870.040 1395.600 871.440 ;
        RECT 3.990 868.040 1396.000 870.040 ;
        RECT 3.990 866.640 1395.600 868.040 ;
        RECT 3.990 864.640 1396.000 866.640 ;
        RECT 3.990 863.240 1395.600 864.640 ;
        RECT 3.990 861.240 1396.000 863.240 ;
        RECT 3.990 859.840 1395.600 861.240 ;
        RECT 3.990 857.840 1396.000 859.840 ;
        RECT 3.990 856.440 1395.600 857.840 ;
        RECT 3.990 854.440 1396.000 856.440 ;
        RECT 3.990 853.040 1395.600 854.440 ;
        RECT 3.990 851.040 1396.000 853.040 ;
        RECT 3.990 849.640 1395.600 851.040 ;
        RECT 3.990 847.640 1396.000 849.640 ;
        RECT 3.990 846.240 1395.600 847.640 ;
        RECT 3.990 844.240 1396.000 846.240 ;
        RECT 3.990 842.840 1395.600 844.240 ;
        RECT 3.990 840.840 1396.000 842.840 ;
        RECT 3.990 839.440 1395.600 840.840 ;
        RECT 3.990 837.440 1396.000 839.440 ;
        RECT 3.990 836.040 1395.600 837.440 ;
        RECT 3.990 834.040 1396.000 836.040 ;
        RECT 3.990 832.640 1395.600 834.040 ;
        RECT 3.990 830.640 1396.000 832.640 ;
        RECT 4.400 829.240 1395.600 830.640 ;
        RECT 3.990 827.240 1396.000 829.240 ;
        RECT 3.990 825.840 1395.600 827.240 ;
        RECT 3.990 823.840 1396.000 825.840 ;
        RECT 3.990 822.440 1395.600 823.840 ;
        RECT 3.990 820.440 1396.000 822.440 ;
        RECT 3.990 819.040 1395.600 820.440 ;
        RECT 3.990 817.040 1396.000 819.040 ;
        RECT 3.990 815.640 1395.600 817.040 ;
        RECT 3.990 813.640 1396.000 815.640 ;
        RECT 3.990 812.240 1395.600 813.640 ;
        RECT 3.990 810.240 1396.000 812.240 ;
        RECT 3.990 808.840 1395.600 810.240 ;
        RECT 3.990 806.840 1396.000 808.840 ;
        RECT 3.990 805.440 1395.600 806.840 ;
        RECT 3.990 803.440 1396.000 805.440 ;
        RECT 3.990 802.040 1395.600 803.440 ;
        RECT 3.990 800.040 1396.000 802.040 ;
        RECT 3.990 798.640 1395.600 800.040 ;
        RECT 3.990 796.640 1396.000 798.640 ;
        RECT 3.990 795.240 1395.600 796.640 ;
        RECT 3.990 793.240 1396.000 795.240 ;
        RECT 3.990 791.840 1395.600 793.240 ;
        RECT 3.990 789.840 1396.000 791.840 ;
        RECT 3.990 788.440 1395.600 789.840 ;
        RECT 3.990 786.440 1396.000 788.440 ;
        RECT 3.990 785.040 1395.600 786.440 ;
        RECT 3.990 783.040 1396.000 785.040 ;
        RECT 3.990 781.640 1395.600 783.040 ;
        RECT 3.990 779.640 1396.000 781.640 ;
        RECT 3.990 778.240 1395.600 779.640 ;
        RECT 3.990 776.240 1396.000 778.240 ;
        RECT 3.990 774.840 1395.600 776.240 ;
        RECT 3.990 772.840 1396.000 774.840 ;
        RECT 3.990 771.440 1395.600 772.840 ;
        RECT 3.990 769.440 1396.000 771.440 ;
        RECT 3.990 768.040 1395.600 769.440 ;
        RECT 3.990 766.040 1396.000 768.040 ;
        RECT 3.990 764.640 1395.600 766.040 ;
        RECT 3.990 762.640 1396.000 764.640 ;
        RECT 3.990 761.240 1395.600 762.640 ;
        RECT 3.990 759.240 1396.000 761.240 ;
        RECT 4.400 757.840 1395.600 759.240 ;
        RECT 3.990 755.840 1396.000 757.840 ;
        RECT 3.990 754.440 1395.600 755.840 ;
        RECT 3.990 752.440 1396.000 754.440 ;
        RECT 3.990 751.040 1395.600 752.440 ;
        RECT 3.990 749.040 1396.000 751.040 ;
        RECT 3.990 747.640 1395.600 749.040 ;
        RECT 3.990 745.640 1396.000 747.640 ;
        RECT 3.990 744.240 1395.600 745.640 ;
        RECT 3.990 742.240 1396.000 744.240 ;
        RECT 3.990 740.840 1395.600 742.240 ;
        RECT 3.990 738.840 1396.000 740.840 ;
        RECT 3.990 737.440 1395.600 738.840 ;
        RECT 3.990 735.440 1396.000 737.440 ;
        RECT 3.990 734.040 1395.600 735.440 ;
        RECT 3.990 732.040 1396.000 734.040 ;
        RECT 3.990 730.640 1395.600 732.040 ;
        RECT 3.990 728.640 1396.000 730.640 ;
        RECT 3.990 727.240 1395.600 728.640 ;
        RECT 3.990 725.240 1396.000 727.240 ;
        RECT 3.990 723.840 1395.600 725.240 ;
        RECT 3.990 721.840 1396.000 723.840 ;
        RECT 3.990 720.440 1395.600 721.840 ;
        RECT 3.990 718.440 1396.000 720.440 ;
        RECT 3.990 717.040 1395.600 718.440 ;
        RECT 3.990 715.040 1396.000 717.040 ;
        RECT 3.990 713.640 1395.600 715.040 ;
        RECT 3.990 711.640 1396.000 713.640 ;
        RECT 3.990 710.240 1395.600 711.640 ;
        RECT 3.990 708.240 1396.000 710.240 ;
        RECT 3.990 706.840 1395.600 708.240 ;
        RECT 3.990 704.840 1396.000 706.840 ;
        RECT 3.990 703.440 1395.600 704.840 ;
        RECT 3.990 701.440 1396.000 703.440 ;
        RECT 3.990 700.040 1395.600 701.440 ;
        RECT 3.990 698.040 1396.000 700.040 ;
        RECT 3.990 696.640 1395.600 698.040 ;
        RECT 3.990 694.640 1396.000 696.640 ;
        RECT 3.990 693.240 1395.600 694.640 ;
        RECT 3.990 691.240 1396.000 693.240 ;
        RECT 3.990 689.840 1395.600 691.240 ;
        RECT 3.990 687.840 1396.000 689.840 ;
        RECT 3.990 686.440 1395.600 687.840 ;
        RECT 3.990 684.440 1396.000 686.440 ;
        RECT 3.990 683.040 1395.600 684.440 ;
        RECT 3.990 681.040 1396.000 683.040 ;
        RECT 3.990 679.640 1395.600 681.040 ;
        RECT 3.990 677.640 1396.000 679.640 ;
        RECT 3.990 676.240 1395.600 677.640 ;
        RECT 3.990 674.240 1396.000 676.240 ;
        RECT 3.990 672.840 1395.600 674.240 ;
        RECT 3.990 670.840 1396.000 672.840 ;
        RECT 3.990 669.440 1395.600 670.840 ;
        RECT 3.990 667.440 1396.000 669.440 ;
        RECT 3.990 666.040 1395.600 667.440 ;
        RECT 3.990 664.040 1396.000 666.040 ;
        RECT 3.990 662.640 1395.600 664.040 ;
        RECT 3.990 660.640 1396.000 662.640 ;
        RECT 3.990 659.240 1395.600 660.640 ;
        RECT 3.990 657.240 1396.000 659.240 ;
        RECT 3.990 655.840 1395.600 657.240 ;
        RECT 3.990 653.840 1396.000 655.840 ;
        RECT 3.990 652.440 1395.600 653.840 ;
        RECT 3.990 650.440 1396.000 652.440 ;
        RECT 3.990 649.040 1395.600 650.440 ;
        RECT 3.990 647.040 1396.000 649.040 ;
        RECT 3.990 645.640 1395.600 647.040 ;
        RECT 3.990 643.640 1396.000 645.640 ;
        RECT 3.990 642.240 1395.600 643.640 ;
        RECT 3.990 640.240 1396.000 642.240 ;
        RECT 3.990 638.840 1395.600 640.240 ;
        RECT 3.990 636.840 1396.000 638.840 ;
        RECT 4.400 635.440 1395.600 636.840 ;
        RECT 3.990 633.440 1396.000 635.440 ;
        RECT 3.990 632.040 1395.600 633.440 ;
        RECT 3.990 630.040 1396.000 632.040 ;
        RECT 3.990 628.640 1395.600 630.040 ;
        RECT 3.990 626.640 1396.000 628.640 ;
        RECT 3.990 625.240 1395.600 626.640 ;
        RECT 3.990 623.240 1396.000 625.240 ;
        RECT 3.990 621.840 1395.600 623.240 ;
        RECT 3.990 619.840 1396.000 621.840 ;
        RECT 3.990 618.440 1395.600 619.840 ;
        RECT 3.990 616.440 1396.000 618.440 ;
        RECT 3.990 615.040 1395.600 616.440 ;
        RECT 3.990 613.040 1396.000 615.040 ;
        RECT 3.990 611.640 1395.600 613.040 ;
        RECT 3.990 609.640 1396.000 611.640 ;
        RECT 3.990 608.240 1395.600 609.640 ;
        RECT 3.990 606.240 1396.000 608.240 ;
        RECT 3.990 604.840 1395.600 606.240 ;
        RECT 3.990 602.840 1396.000 604.840 ;
        RECT 3.990 601.440 1395.600 602.840 ;
        RECT 3.990 599.440 1396.000 601.440 ;
        RECT 3.990 598.040 1395.600 599.440 ;
        RECT 3.990 596.040 1396.000 598.040 ;
        RECT 3.990 594.640 1395.600 596.040 ;
        RECT 3.990 592.640 1396.000 594.640 ;
        RECT 3.990 591.240 1395.600 592.640 ;
        RECT 3.990 589.240 1396.000 591.240 ;
        RECT 3.990 587.840 1395.600 589.240 ;
        RECT 3.990 585.840 1396.000 587.840 ;
        RECT 3.990 584.440 1395.600 585.840 ;
        RECT 3.990 582.440 1396.000 584.440 ;
        RECT 3.990 581.040 1395.600 582.440 ;
        RECT 3.990 579.040 1396.000 581.040 ;
        RECT 3.990 577.640 1395.600 579.040 ;
        RECT 3.990 575.640 1396.000 577.640 ;
        RECT 4.400 574.240 1396.000 575.640 ;
        RECT 3.990 572.240 1396.000 574.240 ;
        RECT 3.990 570.840 1395.600 572.240 ;
        RECT 3.990 568.840 1396.000 570.840 ;
        RECT 3.990 567.440 1395.600 568.840 ;
        RECT 3.990 565.440 1396.000 567.440 ;
        RECT 3.990 564.040 1395.600 565.440 ;
        RECT 3.990 562.040 1396.000 564.040 ;
        RECT 3.990 560.640 1395.600 562.040 ;
        RECT 3.990 558.640 1396.000 560.640 ;
        RECT 3.990 557.240 1395.600 558.640 ;
        RECT 3.990 555.240 1396.000 557.240 ;
        RECT 3.990 553.840 1395.600 555.240 ;
        RECT 3.990 551.840 1396.000 553.840 ;
        RECT 3.990 550.440 1395.600 551.840 ;
        RECT 3.990 548.440 1396.000 550.440 ;
        RECT 3.990 547.040 1395.600 548.440 ;
        RECT 3.990 545.040 1396.000 547.040 ;
        RECT 3.990 543.640 1395.600 545.040 ;
        RECT 3.990 541.640 1396.000 543.640 ;
        RECT 3.990 540.240 1395.600 541.640 ;
        RECT 3.990 538.240 1396.000 540.240 ;
        RECT 3.990 536.840 1395.600 538.240 ;
        RECT 3.990 534.840 1396.000 536.840 ;
        RECT 3.990 533.440 1395.600 534.840 ;
        RECT 3.990 531.440 1396.000 533.440 ;
        RECT 3.990 530.040 1395.600 531.440 ;
        RECT 3.990 528.040 1396.000 530.040 ;
        RECT 3.990 526.640 1395.600 528.040 ;
        RECT 3.990 511.040 1396.000 526.640 ;
        RECT 3.990 509.640 1395.600 511.040 ;
        RECT 3.990 497.440 1396.000 509.640 ;
        RECT 3.990 496.040 1395.600 497.440 ;
        RECT 3.990 494.040 1396.000 496.040 ;
        RECT 3.990 492.640 1395.600 494.040 ;
        RECT 3.990 490.640 1396.000 492.640 ;
        RECT 3.990 489.240 1395.600 490.640 ;
        RECT 3.990 487.240 1396.000 489.240 ;
        RECT 4.400 485.840 1395.600 487.240 ;
        RECT 3.990 483.840 1396.000 485.840 ;
        RECT 3.990 482.440 1395.600 483.840 ;
        RECT 3.990 480.440 1396.000 482.440 ;
        RECT 3.990 479.040 1395.600 480.440 ;
        RECT 3.990 466.840 1396.000 479.040 ;
        RECT 3.990 465.440 1395.600 466.840 ;
        RECT 3.990 449.840 1396.000 465.440 ;
        RECT 3.990 448.440 1395.600 449.840 ;
        RECT 3.990 446.440 1396.000 448.440 ;
        RECT 3.990 445.040 1395.600 446.440 ;
        RECT 3.990 443.040 1396.000 445.040 ;
        RECT 3.990 441.640 1395.600 443.040 ;
        RECT 3.990 439.640 1396.000 441.640 ;
        RECT 3.990 438.240 1395.600 439.640 ;
        RECT 3.990 426.040 1396.000 438.240 ;
        RECT 3.990 424.640 1395.600 426.040 ;
        RECT 3.990 422.640 1396.000 424.640 ;
        RECT 4.400 421.240 1395.600 422.640 ;
        RECT 3.990 419.240 1396.000 421.240 ;
        RECT 3.990 417.840 1395.600 419.240 ;
        RECT 3.990 412.440 1396.000 417.840 ;
        RECT 3.990 411.040 1395.600 412.440 ;
        RECT 3.990 409.040 1396.000 411.040 ;
        RECT 3.990 407.640 1395.600 409.040 ;
        RECT 3.990 405.640 1396.000 407.640 ;
        RECT 3.990 404.240 1395.600 405.640 ;
        RECT 3.990 395.440 1396.000 404.240 ;
        RECT 4.400 394.040 1396.000 395.440 ;
        RECT 3.990 388.640 1396.000 394.040 ;
        RECT 3.990 387.240 1395.600 388.640 ;
        RECT 3.990 385.240 1396.000 387.240 ;
        RECT 3.990 383.840 1395.600 385.240 ;
        RECT 3.990 381.840 1396.000 383.840 ;
        RECT 3.990 380.440 1395.600 381.840 ;
        RECT 3.990 364.840 1396.000 380.440 ;
        RECT 3.990 363.440 1395.600 364.840 ;
        RECT 3.990 361.440 1396.000 363.440 ;
        RECT 3.990 360.040 1395.600 361.440 ;
        RECT 3.990 358.040 1396.000 360.040 ;
        RECT 3.990 356.640 1395.600 358.040 ;
        RECT 3.990 354.640 1396.000 356.640 ;
        RECT 3.990 353.240 1395.600 354.640 ;
        RECT 3.990 347.840 1396.000 353.240 ;
        RECT 3.990 346.440 1395.600 347.840 ;
        RECT 3.990 344.440 1396.000 346.440 ;
        RECT 3.990 343.040 1395.600 344.440 ;
        RECT 3.990 341.040 1396.000 343.040 ;
        RECT 4.400 339.640 1395.600 341.040 ;
        RECT 3.990 337.640 1396.000 339.640 ;
        RECT 3.990 336.240 1395.600 337.640 ;
        RECT 3.990 330.840 1396.000 336.240 ;
        RECT 4.400 329.440 1396.000 330.840 ;
        RECT 3.990 327.440 1396.000 329.440 ;
        RECT 3.990 326.040 1395.600 327.440 ;
        RECT 3.990 324.040 1396.000 326.040 ;
        RECT 3.990 322.640 1395.600 324.040 ;
        RECT 3.990 320.640 1396.000 322.640 ;
        RECT 3.990 319.240 1395.600 320.640 ;
        RECT 3.990 300.240 1396.000 319.240 ;
        RECT 4.400 298.840 1395.600 300.240 ;
        RECT 3.990 279.840 1396.000 298.840 ;
        RECT 4.400 278.440 1396.000 279.840 ;
        RECT 3.990 262.840 1396.000 278.440 ;
        RECT 3.990 261.440 1395.600 262.840 ;
        RECT 3.990 249.240 1396.000 261.440 ;
        RECT 4.400 247.840 1396.000 249.240 ;
        RECT 3.990 245.840 1396.000 247.840 ;
        RECT 4.400 244.440 1395.600 245.840 ;
        RECT 3.990 242.440 1396.000 244.440 ;
        RECT 4.400 241.040 1395.600 242.440 ;
        RECT 3.990 232.240 1396.000 241.040 ;
        RECT 4.400 230.840 1396.000 232.240 ;
        RECT 3.990 218.640 1396.000 230.840 ;
        RECT 3.990 217.240 1395.600 218.640 ;
        RECT 3.990 211.840 1396.000 217.240 ;
        RECT 3.990 210.440 1395.600 211.840 ;
        RECT 3.990 38.440 1396.000 210.440 ;
        RECT 4.400 37.040 1396.000 38.440 ;
        RECT 3.990 35.040 1396.000 37.040 ;
        RECT 4.400 33.640 1396.000 35.040 ;
        RECT 3.990 31.640 1396.000 33.640 ;
        RECT 4.400 30.240 1396.000 31.640 ;
        RECT 3.990 28.240 1396.000 30.240 ;
        RECT 4.400 26.840 1396.000 28.240 ;
        RECT 3.990 24.840 1396.000 26.840 ;
        RECT 4.400 23.440 1396.000 24.840 ;
        RECT 3.990 9.695 1396.000 23.440 ;
      LAYER met4 ;
        RECT 302.975 10.240 327.840 1385.665 ;
        RECT 330.240 10.240 331.140 1385.665 ;
        RECT 333.540 10.240 481.440 1385.665 ;
        RECT 483.840 10.240 484.740 1385.665 ;
        RECT 487.140 10.240 635.040 1385.665 ;
        RECT 637.440 10.240 638.340 1385.665 ;
        RECT 640.740 10.240 788.640 1385.665 ;
        RECT 791.040 10.240 791.940 1385.665 ;
        RECT 794.340 10.240 942.240 1385.665 ;
        RECT 944.640 10.240 945.540 1385.665 ;
        RECT 947.940 10.240 1095.840 1385.665 ;
        RECT 1098.240 10.240 1099.140 1385.665 ;
        RECT 1101.540 10.240 1249.440 1385.665 ;
        RECT 1251.840 10.240 1252.740 1385.665 ;
        RECT 1255.140 10.240 1386.145 1385.665 ;
        RECT 302.975 9.695 1386.145 10.240 ;
      LAYER met5 ;
        RECT 322.580 952.310 1379.420 957.900 ;
        RECT 322.580 799.130 1379.420 944.210 ;
        RECT 322.580 645.950 1379.420 791.030 ;
        RECT 322.580 492.770 1379.420 637.850 ;
        RECT 322.580 357.900 1379.420 484.670 ;
  END
END ibex_top
END LIBRARY

